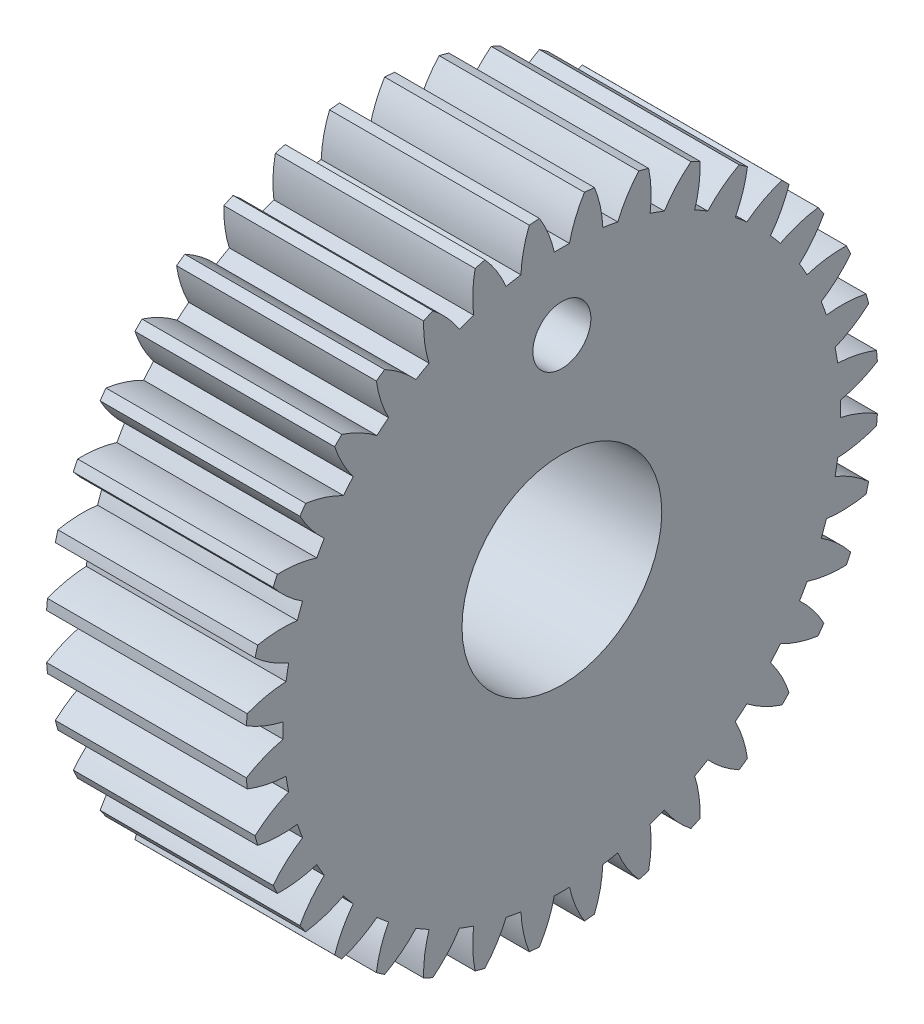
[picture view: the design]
ISO-10303-21;
HEADER;
FILE_DESCRIPTION(('STEP AP214'),'2;1');
FILE_NAME('part.step','',(''),(''),'','','');
FILE_SCHEMA(('AUTOMOTIVE_DESIGN { 1 0 10303 214 1 1 1 1 }'));
ENDSEC;
DATA;
#1=APPLICATION_CONTEXT('core data for automotive mechanical design processes');
#2=APPLICATION_PROTOCOL_DEFINITION('international standard','automotive_design',2000,#1);
#3=PRODUCT_CONTEXT('',#1,'mechanical');
#4=PRODUCT('Part','Part','',(#3));
#5=PRODUCT_RELATED_PRODUCT_CATEGORY('part','',(#4));
#6=PRODUCT_DEFINITION_FORMATION('','',#4);
#7=PRODUCT_DEFINITION_CONTEXT('part definition',#1,'design');
#8=PRODUCT_DEFINITION('design','',#6,#7);
#9=PRODUCT_DEFINITION_SHAPE('','',#8);
#10=(LENGTH_UNIT() NAMED_UNIT(*) SI_UNIT(.MILLI.,.METRE.));
#11=(NAMED_UNIT(*) PLANE_ANGLE_UNIT() SI_UNIT($,.RADIAN.));
#12=(NAMED_UNIT(*) SI_UNIT($,.STERADIAN.) SOLID_ANGLE_UNIT());
#13=UNCERTAINTY_MEASURE_WITH_UNIT(LENGTH_MEASURE(1.E-05),#10,'distance_accuracy_value','');
#14=(GEOMETRIC_REPRESENTATION_CONTEXT(3) GLOBAL_UNCERTAINTY_ASSIGNED_CONTEXT((#13)) GLOBAL_UNIT_ASSIGNED_CONTEXT((#10,
#11,#12)) REPRESENTATION_CONTEXT('',''));
#15=CARTESIAN_POINT('',(0.,0.,0.));
#16=DIRECTION('',(0.,0.,1.));
#17=DIRECTION('',(1.,0.,0.));
#18=AXIS2_PLACEMENT_3D('',#15,#16,#17);
#19=CARTESIAN_POINT('',(12.,0.,0.));
#20=DIRECTION('',(-1.,0.,0.));
#21=DIRECTION('',(0.,0.,1.));
#22=AXIS2_PLACEMENT_3D('',#19,#20,#21);
#23=PLANE('',#22);
#24=CARTESIAN_POINT('',(12.,12.2072193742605,0.));
#25=DIRECTION('',(-1.,0.,0.));
#26=DIRECTION('',(0.,0.,1.));
#27=AXIS2_PLACEMENT_3D('',#24,#25,#26);
#28=CIRCLE('',#27,1.74146852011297);
#29=CARTESIAN_POINT('',(12.,12.2072193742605,1.74146852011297));
#30=VERTEX_POINT('',#29);
#31=EDGE_CURVE('E1740',#30,#30,#28,.T.);
#32=ORIENTED_EDGE('',*,*,#31,.T.);
#33=EDGE_LOOP('',(#32));
#34=FACE_BOUND('',#33,.T.);
#35=CARTESIAN_POINT('',(12.,13.6407443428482,-10.001464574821));
#36=DIRECTION('',(-1.,0.,0.));
#37=DIRECTION('',(0.,-0.173648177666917,-0.984807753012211));
#38=AXIS2_PLACEMENT_3D('',#35,#36,#37);
#39=CIRCLE('',#38,7.2);
#40=CARTESIAN_POINT('',(12.,16.4095148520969,-3.35511897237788));
#41=VERTEX_POINT('',#40);
#42=CARTESIAN_POINT('',(12.,18.4287050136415,-4.624157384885));
#43=VERTEX_POINT('',#42);
#44=EDGE_CURVE('E934',#41,#43,#39,.T.);
#45=ORIENTED_EDGE('',*,*,#44,.F.);
#46=CARTESIAN_POINT('',(12.,0.,0.));
#47=DIRECTION('',(-1.,0.,0.));
#48=DIRECTION('',(0.,-0.173648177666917,-0.984807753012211));
#49=AXIS2_PLACEMENT_3D('',#46,#47,#48);
#50=CIRCLE('',#49,16.749);
#51=CARTESIAN_POINT('',(12.,16.5674182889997,-2.45960408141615));
#52=VERTEX_POINT('',#51);
#53=EDGE_CURVE('E1729',#52,#41,#50,.T.);
#54=ORIENTED_EDGE('',*,*,#53,.F.);
#55=CARTESIAN_POINT('',(12.,16.2388091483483,4.73289312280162));
#56=DIRECTION('',(-1.,0.,0.));
#57=DIRECTION('',(0.,-0.173648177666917,-0.984807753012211));
#58=AXIS2_PLACEMENT_3D('',#55,#56,#57);
#59=CIRCLE('',#58,7.2);
#60=CARTESIAN_POINT('',(12.,18.898873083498,-1.95770175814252));
#61=VERTEX_POINT('',#60);
#62=EDGE_CURVE('E924',#61,#52,#59,.T.);
#63=ORIENTED_EDGE('',*,*,#62,.F.);
#64=CARTESIAN_POINT('',(12.,0.,0.));
#65=DIRECTION('',(-1.,0.,0.));
#66=DIRECTION('',(0.,0.,1.));
#67=AXIS2_PLACEMENT_3D('',#64,#65,#66);
#68=CIRCLE('',#67,19.);
#69=CARTESIAN_POINT('',(12.,18.9517080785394,-1.3537950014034));
#70=VERTEX_POINT('',#69);
#71=EDGE_CURVE('E952',#70,#61,#68,.T.);
#72=ORIENTED_EDGE('',*,*,#71,.F.);
#73=CARTESIAN_POINT('',(12.,15.1702468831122,-7.48082945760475));
#74=DIRECTION('',(-1.,0.,0.));
#75=DIRECTION('',(0.,0.,-1.));
#76=AXIS2_PLACEMENT_3D('',#73,#74,#75);
#77=CIRCLE('',#76,7.2);
#78=CARTESIAN_POINT('',(12.,16.7428277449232,-0.454664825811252));
#79=VERTEX_POINT('',#78);
#80=EDGE_CURVE('E976',#79,#70,#77,.T.);
#81=ORIENTED_EDGE('',*,*,#80,.F.);
#82=CARTESIAN_POINT('',(12.,0.,0.));
#83=DIRECTION('',(-1.,0.,0.));
#84=DIRECTION('',(0.,0.,-1.));
#85=AXIS2_PLACEMENT_3D('',#82,#83,#84);
#86=CIRCLE('',#85,16.749);
#87=CARTESIAN_POINT('',(12.,16.7428277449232,0.454664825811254));
#88=VERTEX_POINT('',#87);
#89=EDGE_CURVE('E972',#88,#79,#86,.T.);
#90=ORIENTED_EDGE('',*,*,#89,.F.);
#91=CARTESIAN_POINT('',(12.,15.1702468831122,7.48082945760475));
#92=DIRECTION('',(-1.,0.,0.));
#93=DIRECTION('',(0.,0.,-1.));
#94=AXIS2_PLACEMENT_3D('',#91,#92,#93);
#95=CIRCLE('',#94,7.2);
#96=CARTESIAN_POINT('',(12.,18.9517080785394,1.3537950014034));
#97=VERTEX_POINT('',#96);
#98=EDGE_CURVE('E974',#97,#88,#95,.T.);
#99=ORIENTED_EDGE('',*,*,#98,.F.);
#100=CARTESIAN_POINT('',(12.,18.898873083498,1.95770175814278));
#101=VERTEX_POINT('',#100);
#102=EDGE_CURVE('E946',#101,#97,#68,.T.);
#103=ORIENTED_EDGE('',*,*,#102,.F.);
#104=CARTESIAN_POINT('',(12.,16.2388091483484,-4.73289312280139));
#105=DIRECTION('',(-1.,0.,0.));
#106=DIRECTION('',(0.,0.173648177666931,-0.984807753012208));
#107=AXIS2_PLACEMENT_3D('',#104,#105,#106);
#108=CIRCLE('',#107,7.2);
#109=CARTESIAN_POINT('',(12.,16.5674182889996,2.45960408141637));
#110=VERTEX_POINT('',#109);
#111=EDGE_CURVE('E995',#110,#101,#108,.T.);
#112=ORIENTED_EDGE('',*,*,#111,.F.);
#113=CARTESIAN_POINT('',(12.,0.,0.));
#114=DIRECTION('',(-1.,0.,0.));
#115=DIRECTION('',(0.,0.173648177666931,-0.984807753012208));
#116=AXIS2_PLACEMENT_3D('',#113,#114,#115);
#117=CIRCLE('',#116,16.749);
#118=CARTESIAN_POINT('',(12.,16.4095148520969,3.35511897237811));
#119=VERTEX_POINT('',#118);
#120=EDGE_CURVE('E991',#119,#110,#117,.T.);
#121=ORIENTED_EDGE('',*,*,#120,.F.);
#122=CARTESIAN_POINT('',(12.,13.6407443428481,10.0014645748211));
#123=DIRECTION('',(-1.,0.,0.));
#124=DIRECTION('',(0.,0.173648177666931,-0.984807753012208));
#125=AXIS2_PLACEMENT_3D('',#122,#123,#124);
#126=CIRCLE('',#125,7.2);
#127=CARTESIAN_POINT('',(12.,18.4287050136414,4.62415738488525));
#128=VERTEX_POINT('',#127);
#129=EDGE_CURVE('E993',#128,#119,#126,.T.);
#130=ORIENTED_EDGE('',*,*,#129,.F.);
#131=CARTESIAN_POINT('',(12.,18.2718053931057,5.20971474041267));
#132=VERTEX_POINT('',#131);
#133=EDGE_CURVE('E950',#132,#128,#68,.T.);
#134=ORIENTED_EDGE('',*,*,#133,.F.);
#135=CARTESIAN_POINT('',(12.,16.8139634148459,-1.8411502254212));
#136=DIRECTION('',(-1.,0.,0.));
#137=DIRECTION('',(0.,0.342020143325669,-0.939692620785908));
#138=AXIS2_PLACEMENT_3D('',#135,#136,#137);
#139=CIRCLE('',#138,7.2);
#140=CARTESIAN_POINT('',(12.,15.888616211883,5.29913916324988));
#141=VERTEX_POINT('',#140);
#142=EDGE_CURVE('E1016',#141,#132,#139,.T.);
#143=ORIENTED_EDGE('',*,*,#142,.F.);
#144=CARTESIAN_POINT('',(12.,0.,0.));
#145=DIRECTION('',(-1.,0.,0.));
#146=DIRECTION('',(0.,0.342020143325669,-0.939692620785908));
#147=AXIS2_PLACEMENT_3D('',#144,#145,#146);
#148=CIRCLE('',#147,16.749);
#149=CARTESIAN_POINT('',(12.,15.5776071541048,6.15362952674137));
#150=VERTEX_POINT('',#149);
#151=EDGE_CURVE('E1012',#150,#141,#148,.T.);
#152=ORIENTED_EDGE('',*,*,#151,.F.);
#153=CARTESIAN_POINT('',(12.,11.6967746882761,12.2182102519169));
#154=DIRECTION('',(-1.,0.,0.));
#155=DIRECTION('',(0.,0.342020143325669,-0.939692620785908));
#156=AXIS2_PLACEMENT_3D('',#153,#154,#155);
#157=CIRCLE('',#156,7.2);
#158=CARTESIAN_POINT('',(12.,17.3457550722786,7.75401708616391));
#159=VERTEX_POINT('',#158);
#160=EDGE_CURVE('E1014',#159,#150,#157,.T.);
#161=ORIENTED_EDGE('',*,*,#160,.F.);
#162=CARTESIAN_POINT('',(12.,17.0895581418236,8.30343317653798));
#163=VERTEX_POINT('',#162);
#164=EDGE_CURVE('E2058',#163,#159,#68,.T.);
#165=ORIENTED_EDGE('',*,*,#164,.F.);
#166=CARTESIAN_POINT('',(12.,16.8782339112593,1.10653508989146));
#167=DIRECTION('',(-1.,0.,0.));
#168=DIRECTION('',(0.,0.500000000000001,-0.866025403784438));
#169=AXIS2_PLACEMENT_3D('',#166,#167,#168);
#170=CIRCLE('',#169,7.2);
#171=CARTESIAN_POINT('',(12.,14.727046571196,7.97766258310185));
#172=VERTEX_POINT('',#171);
#173=EDGE_CURVE('E1038',#172,#163,#170,.T.);
#174=ORIENTED_EDGE('',*,*,#173,.F.);
#175=CARTESIAN_POINT('',(12.,0.,0.));
#176=DIRECTION('',(-1.,0.,0.));
#177=DIRECTION('',(0.,0.500000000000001,-0.866025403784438));
#178=AXIS2_PLACEMENT_3D('',#175,#176,#177);
#179=CIRCLE('',#178,16.749);
#180=CARTESIAN_POINT('',(12.,14.2723817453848,8.76516516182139));
#181=VERTEX_POINT('',#180);
#182=EDGE_CURVE('E1034',#181,#172,#179,.T.);
#183=ORIENTED_EDGE('',*,*,#182,.F.);
#184=CARTESIAN_POINT('',(12.,9.3974044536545,14.0637117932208));
#185=DIRECTION('',(-1.,0.,0.));
#186=DIRECTION('',(0.,0.500000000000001,-0.866025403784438));
#187=AXIS2_PLACEMENT_3D('',#184,#185,#186);
#188=CIRCLE('',#187,7.2);
#189=CARTESIAN_POINT('',(12.,15.7357631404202,10.6482749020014));
#190=VERTEX_POINT('',#189);
#191=EDGE_CURVE('E1036',#190,#181,#188,.T.);
#192=ORIENTED_EDGE('',*,*,#191,.F.);
#193=CARTESIAN_POINT('',(12.,15.3880533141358,11.1448559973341));
#194=VERTEX_POINT('',#193);
#195=EDGE_CURVE('E2053',#194,#190,#68,.T.);
#196=ORIENTED_EDGE('',*,*,#195,.F.);
#197=CARTESIAN_POINT('',(12.,16.4296678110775,4.02059889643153));
#198=DIRECTION('',(-1.,0.,0.));
#199=DIRECTION('',(0.,0.642787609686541,-0.766044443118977));
#200=AXIS2_PLACEMENT_3D('',#197,#198,#199);
#201=CIRCLE('',#200,7.2);
#202=CARTESIAN_POINT('',(12.,13.1180030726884,10.4137887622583));
#203=VERTEX_POINT('',#202);
#204=EDGE_CURVE('E1060',#203,#194,#201,.T.);
#205=ORIENTED_EDGE('',*,*,#204,.F.);
#206=CARTESIAN_POINT('',(12.,0.,0.));
#207=DIRECTION('',(-1.,0.,0.));
#208=DIRECTION('',(0.,0.642787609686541,-0.766044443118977));
#209=AXIS2_PLACEMENT_3D('',#206,#207,#208);
#210=CIRCLE('',#209,16.749);
#211=CARTESIAN_POINT('',(12.,12.5334972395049,11.110375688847));
#212=VERTEX_POINT('',#211);
#213=EDGE_CURVE('E1056',#212,#203,#210,.T.);
#214=ORIENTED_EDGE('',*,*,#213,.F.);
#215=CARTESIAN_POINT('',(12.,6.8124988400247,15.4818945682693));
#216=DIRECTION('',(-1.,0.,0.));
#217=DIRECTION('',(0.,0.642787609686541,-0.766044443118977));
#218=AXIS2_PLACEMENT_3D('',#215,#216,#217);
#219=CIRCLE('',#218,7.2);
#220=CARTESIAN_POINT('',(12.,13.6476480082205,13.2189902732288));
#221=VERTEX_POINT('',#220);
#222=EDGE_CURVE('E1058',#221,#212,#219,.T.);
#223=ORIENTED_EDGE('',*,*,#222,.F.);
#224=CARTESIAN_POINT('',(12.,13.2189902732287,13.6476480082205));
#225=VERTEX_POINT('',#224);
#226=EDGE_CURVE('E2048',#225,#221,#68,.T.);
#227=ORIENTED_EDGE('',*,*,#226,.F.);
#228=CARTESIAN_POINT('',(12.,15.4818945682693,6.81249884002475));
#229=DIRECTION('',(-1.,0.,0.));
#230=DIRECTION('',(0.,0.766044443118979,-0.642787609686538));
#231=AXIS2_PLACEMENT_3D('',#228,#229,#230);
#232=CIRCLE('',#231,7.2);
#233=CARTESIAN_POINT('',(12.,11.110375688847,12.5334972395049));
#234=VERTEX_POINT('',#233);
#235=EDGE_CURVE('E1082',#234,#225,#232,.T.);
#236=ORIENTED_EDGE('',*,*,#235,.F.);
#237=CARTESIAN_POINT('',(12.,0.,0.));
#238=DIRECTION('',(-1.,0.,0.));
#239=DIRECTION('',(0.,0.766044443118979,-0.642787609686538));
#240=AXIS2_PLACEMENT_3D('',#237,#238,#239);
#241=CIRCLE('',#240,16.749);
#242=CARTESIAN_POINT('',(12.,10.4137887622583,13.1180030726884));
#243=VERTEX_POINT('',#242);
#244=EDGE_CURVE('E1078',#243,#234,#241,.T.);
#245=ORIENTED_EDGE('',*,*,#244,.F.);
#246=CARTESIAN_POINT('',(12.,4.02059889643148,16.4296678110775));
#247=DIRECTION('',(-1.,0.,0.));
#248=DIRECTION('',(0.,0.766044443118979,-0.642787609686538));
#249=AXIS2_PLACEMENT_3D('',#246,#247,#248);
#250=CIRCLE('',#249,7.2);
#251=CARTESIAN_POINT('',(12.,11.1448559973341,15.3880533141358));
#252=VERTEX_POINT('',#251);
#253=EDGE_CURVE('E1080',#252,#243,#250,.T.);
#254=ORIENTED_EDGE('',*,*,#253,.F.);
#255=CARTESIAN_POINT('',(12.,10.6482749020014,15.7357631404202));
#256=VERTEX_POINT('',#255);
#257=EDGE_CURVE('E2043',#256,#252,#68,.T.);
#258=ORIENTED_EDGE('',*,*,#257,.F.);
#259=CARTESIAN_POINT('',(12.,14.0637117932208,9.39740445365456));
#260=DIRECTION('',(-1.,0.,0.));
#261=DIRECTION('',(0.,0.86602540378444,-0.499999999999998));
#262=AXIS2_PLACEMENT_3D('',#259,#260,#261);
#263=CIRCLE('',#262,7.2);
#264=CARTESIAN_POINT('',(12.,8.76516516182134,14.2723817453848));
#265=VERTEX_POINT('',#264);
#266=EDGE_CURVE('E1104',#265,#256,#263,.T.);
#267=ORIENTED_EDGE('',*,*,#266,.F.);
#268=CARTESIAN_POINT('',(12.,0.,0.));
#269=DIRECTION('',(-1.,0.,0.));
#270=DIRECTION('',(0.,0.86602540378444,-0.499999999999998));
#271=AXIS2_PLACEMENT_3D('',#268,#269,#270);
#272=CIRCLE('',#271,16.749);
#273=CARTESIAN_POINT('',(12.,7.97766258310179,14.7270465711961));
#274=VERTEX_POINT('',#273);
#275=EDGE_CURVE('E1100',#274,#265,#272,.T.);
#276=ORIENTED_EDGE('',*,*,#275,.F.);
#277=CARTESIAN_POINT('',(12.,1.1065350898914,16.8782339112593));
#278=DIRECTION('',(-1.,0.,0.));
#279=DIRECTION('',(0.,0.86602540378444,-0.499999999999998));
#280=AXIS2_PLACEMENT_3D('',#277,#278,#279);
#281=CIRCLE('',#280,7.2);
#282=CARTESIAN_POINT('',(12.,8.30343317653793,17.0895581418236));
#283=VERTEX_POINT('',#282);
#284=EDGE_CURVE('E1102',#283,#274,#281,.T.);
#285=ORIENTED_EDGE('',*,*,#284,.F.);
#286=CARTESIAN_POINT('',(12.,7.75401708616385,17.3457550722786));
#287=VERTEX_POINT('',#286);
#288=EDGE_CURVE('E2038',#287,#283,#68,.T.);
#289=ORIENTED_EDGE('',*,*,#288,.F.);
#290=CARTESIAN_POINT('',(12.,12.2182102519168,11.6967746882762));
#291=DIRECTION('',(-1.,0.,0.));
#292=DIRECTION('',(0.,0.939692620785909,-0.342020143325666));
#293=AXIS2_PLACEMENT_3D('',#290,#291,#292);
#294=CIRCLE('',#293,7.2);
#295=CARTESIAN_POINT('',(12.,6.15362952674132,15.5776071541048));
#296=VERTEX_POINT('',#295);
#297=EDGE_CURVE('E1126',#296,#287,#294,.T.);
#298=ORIENTED_EDGE('',*,*,#297,.F.);
#299=CARTESIAN_POINT('',(12.,0.,0.));
#300=DIRECTION('',(-1.,0.,0.));
#301=DIRECTION('',(0.,0.939692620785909,-0.342020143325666));
#302=AXIS2_PLACEMENT_3D('',#299,#300,#301);
#303=CIRCLE('',#302,16.749);
#304=CARTESIAN_POINT('',(12.,5.29913916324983,15.888616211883));
#305=VERTEX_POINT('',#304);
#306=EDGE_CURVE('E1122',#305,#296,#303,.T.);
#307=ORIENTED_EDGE('',*,*,#306,.F.);
#308=CARTESIAN_POINT('',(12.,-1.84115022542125,16.8139634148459));
#309=DIRECTION('',(-1.,0.,0.));
#310=DIRECTION('',(0.,0.939692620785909,-0.342020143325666));
#311=AXIS2_PLACEMENT_3D('',#308,#309,#310);
#312=CIRCLE('',#311,7.2);
#313=CARTESIAN_POINT('',(12.,5.20971474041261,18.2718053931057));
#314=VERTEX_POINT('',#313);
#315=EDGE_CURVE('E1124',#314,#305,#312,.T.);
#316=ORIENTED_EDGE('',*,*,#315,.F.);
#317=CARTESIAN_POINT('',(12.,4.62415738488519,18.4287050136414));
#318=VERTEX_POINT('',#317);
#319=EDGE_CURVE('E2033',#318,#314,#68,.T.);
#320=ORIENTED_EDGE('',*,*,#319,.F.);
#321=CARTESIAN_POINT('',(12.,10.0014645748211,13.6407443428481));
#322=DIRECTION('',(-1.,0.,0.));
#323=DIRECTION('',(0.,0.984807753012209,-0.173648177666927));
#324=AXIS2_PLACEMENT_3D('',#321,#322,#323);
#325=CIRCLE('',#324,7.2);
#326=CARTESIAN_POINT('',(12.,3.35511897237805,16.4095148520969));
#327=VERTEX_POINT('',#326);
#328=EDGE_CURVE('E1148',#327,#318,#325,.T.);
#329=ORIENTED_EDGE('',*,*,#328,.F.);
#330=CARTESIAN_POINT('',(12.,0.,0.));
#331=DIRECTION('',(-1.,0.,0.));
#332=DIRECTION('',(0.,0.984807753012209,-0.173648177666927));
#333=AXIS2_PLACEMENT_3D('',#330,#331,#332);
#334=CIRCLE('',#333,16.749);
#335=CARTESIAN_POINT('',(12.,2.45960408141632,16.5674182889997));
#336=VERTEX_POINT('',#335);
#337=EDGE_CURVE('E1144',#336,#327,#334,.T.);
#338=ORIENTED_EDGE('',*,*,#337,.F.);
#339=CARTESIAN_POINT('',(12.,-4.73289312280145,16.2388091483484));
#340=DIRECTION('',(-1.,0.,0.));
#341=DIRECTION('',(0.,0.984807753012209,-0.173648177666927));
#342=AXIS2_PLACEMENT_3D('',#339,#340,#341);
#343=CIRCLE('',#342,7.2);
#344=CARTESIAN_POINT('',(12.,1.95770175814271,18.898873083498));
#345=VERTEX_POINT('',#344);
#346=EDGE_CURVE('E1146',#345,#336,#343,.T.);
#347=ORIENTED_EDGE('',*,*,#346,.F.);
#348=CARTESIAN_POINT('',(12.,1.35379500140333,18.9517080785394));
#349=VERTEX_POINT('',#348);
#350=EDGE_CURVE('E2028',#349,#345,#68,.T.);
#351=ORIENTED_EDGE('',*,*,#350,.F.);
#352=CARTESIAN_POINT('',(12.,7.4808294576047,15.1702468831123));
#353=DIRECTION('',(-1.,0.,0.));
#354=DIRECTION('',(0.,1.,0.));
#355=AXIS2_PLACEMENT_3D('',#352,#353,#354);
#356=CIRCLE('',#355,7.2);
#357=CARTESIAN_POINT('',(12.,0.454664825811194,16.7428277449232));
#358=VERTEX_POINT('',#357);
#359=EDGE_CURVE('E1170',#358,#349,#356,.T.);
#360=ORIENTED_EDGE('',*,*,#359,.F.);
#361=CARTESIAN_POINT('',(12.,0.,0.));
#362=DIRECTION('',(-1.,0.,0.));
#363=DIRECTION('',(0.,1.,0.));
#364=AXIS2_PLACEMENT_3D('',#361,#362,#363);
#365=CIRCLE('',#364,16.749);
#366=CARTESIAN_POINT('',(12.,-0.454664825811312,16.7428277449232));
#367=VERTEX_POINT('',#366);
#368=EDGE_CURVE('E1166',#367,#358,#365,.T.);
#369=ORIENTED_EDGE('',*,*,#368,.F.);
#370=CARTESIAN_POINT('',(12.,-7.48082945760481,15.1702468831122));
#371=DIRECTION('',(-1.,0.,0.));
#372=DIRECTION('',(0.,1.,0.));
#373=AXIS2_PLACEMENT_3D('',#370,#371,#372);
#374=CIRCLE('',#373,7.2);
#375=CARTESIAN_POINT('',(12.,-1.35379500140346,18.9517080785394));
#376=VERTEX_POINT('',#375);
#377=EDGE_CURVE('E1168',#376,#367,#374,.T.);
#378=ORIENTED_EDGE('',*,*,#377,.F.);
#379=CARTESIAN_POINT('',(12.,-1.95770175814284,18.898873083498));
#380=VERTEX_POINT('',#379);
#381=EDGE_CURVE('E2023',#380,#376,#68,.T.);
#382=ORIENTED_EDGE('',*,*,#381,.F.);
#383=CARTESIAN_POINT('',(12.,4.73289312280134,16.2388091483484));
#384=DIRECTION('',(-1.,0.,0.));
#385=DIRECTION('',(0.,0.984807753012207,0.173648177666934));
#386=AXIS2_PLACEMENT_3D('',#383,#384,#385);
#387=CIRCLE('',#386,7.2);
#388=CARTESIAN_POINT('',(12.,-2.45960408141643,16.5674182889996));
#389=VERTEX_POINT('',#388);
#390=EDGE_CURVE('E1192',#389,#380,#387,.T.);
#391=ORIENTED_EDGE('',*,*,#390,.F.);
#392=CARTESIAN_POINT('',(12.,0.,0.));
#393=DIRECTION('',(-1.,0.,0.));
#394=DIRECTION('',(0.,0.984807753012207,0.173648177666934));
#395=AXIS2_PLACEMENT_3D('',#392,#393,#394);
#396=CIRCLE('',#395,16.749);
#397=CARTESIAN_POINT('',(12.,-3.35511897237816,16.4095148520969));
#398=VERTEX_POINT('',#397);
#399=EDGE_CURVE('E1188',#398,#389,#396,.T.);
#400=ORIENTED_EDGE('',*,*,#399,.F.);
#401=CARTESIAN_POINT('',(12.,-10.0014645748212,13.640744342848));
#402=DIRECTION('',(-1.,0.,0.));
#403=DIRECTION('',(0.,0.984807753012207,0.173648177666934));
#404=AXIS2_PLACEMENT_3D('',#401,#402,#403);
#405=CIRCLE('',#404,7.2);
#406=CARTESIAN_POINT('',(12.,-4.62415738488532,18.4287050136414));
#407=VERTEX_POINT('',#406);
#408=EDGE_CURVE('E1190',#407,#398,#405,.T.);
#409=ORIENTED_EDGE('',*,*,#408,.F.);
#410=CARTESIAN_POINT('',(12.,-5.20971474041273,18.2718053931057));
#411=VERTEX_POINT('',#410);
#412=EDGE_CURVE('E2018',#411,#407,#68,.T.);
#413=ORIENTED_EDGE('',*,*,#412,.F.);
#414=CARTESIAN_POINT('',(12.,1.84115022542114,16.8139634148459));
#415=DIRECTION('',(-1.,0.,0.));
#416=DIRECTION('',(0.,0.939692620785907,0.342020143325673));
#417=AXIS2_PLACEMENT_3D('',#414,#415,#416);
#418=CIRCLE('',#417,7.2);
#419=CARTESIAN_POINT('',(12.,-5.29913916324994,15.888616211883));
#420=VERTEX_POINT('',#419);
#421=EDGE_CURVE('E1214',#420,#411,#418,.T.);
#422=ORIENTED_EDGE('',*,*,#421,.F.);
#423=CARTESIAN_POINT('',(12.,0.,0.));
#424=DIRECTION('',(-1.,0.,0.));
#425=DIRECTION('',(0.,0.939692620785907,0.342020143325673));
#426=AXIS2_PLACEMENT_3D('',#423,#424,#425);
#427=CIRCLE('',#426,16.749);
#428=CARTESIAN_POINT('',(12.,-6.15362952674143,15.5776071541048));
#429=VERTEX_POINT('',#428);
#430=EDGE_CURVE('E1210',#429,#420,#427,.T.);
#431=ORIENTED_EDGE('',*,*,#430,.F.);
#432=CARTESIAN_POINT('',(12.,-12.2182102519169,11.6967746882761));
#433=DIRECTION('',(-1.,0.,0.));
#434=DIRECTION('',(0.,0.939692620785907,0.342020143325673));
#435=AXIS2_PLACEMENT_3D('',#432,#433,#434);
#436=CIRCLE('',#435,7.2);
#437=CARTESIAN_POINT('',(12.,-7.75401708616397,17.3457550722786));
#438=VERTEX_POINT('',#437);
#439=EDGE_CURVE('E1212',#438,#429,#436,.T.);
#440=ORIENTED_EDGE('',*,*,#439,.F.);
#441=CARTESIAN_POINT('',(12.,-8.30343317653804,17.0895581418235));
#442=VERTEX_POINT('',#441);
#443=EDGE_CURVE('E2013',#442,#438,#68,.T.);
#444=ORIENTED_EDGE('',*,*,#443,.F.);
#445=CARTESIAN_POINT('',(12.,-1.10653508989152,16.8782339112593));
#446=DIRECTION('',(-1.,0.,0.));
#447=DIRECTION('',(0.,0.866025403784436,0.500000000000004));
#448=AXIS2_PLACEMENT_3D('',#445,#446,#447);
#449=CIRCLE('',#448,7.2);
#450=CARTESIAN_POINT('',(12.,-7.9776625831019,14.727046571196));
#451=VERTEX_POINT('',#450);
#452=EDGE_CURVE('E1236',#451,#442,#449,.T.);
#453=ORIENTED_EDGE('',*,*,#452,.F.);
#454=CARTESIAN_POINT('',(12.,0.,0.));
#455=DIRECTION('',(-1.,0.,0.));
#456=DIRECTION('',(0.,0.866025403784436,0.500000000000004));
#457=AXIS2_PLACEMENT_3D('',#454,#455,#456);
#458=CIRCLE('',#457,16.749);
#459=CARTESIAN_POINT('',(12.,-8.76516516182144,14.2723817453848));
#460=VERTEX_POINT('',#459);
#461=EDGE_CURVE('E1232',#460,#451,#458,.T.);
#462=ORIENTED_EDGE('',*,*,#461,.F.);
#463=CARTESIAN_POINT('',(12.,-14.0637117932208,9.39740445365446));
#464=DIRECTION('',(-1.,0.,0.));
#465=DIRECTION('',(0.,0.866025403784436,0.500000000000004));
#466=AXIS2_PLACEMENT_3D('',#463,#464,#465);
#467=CIRCLE('',#466,7.2);
#468=CARTESIAN_POINT('',(12.,-10.6482749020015,15.7357631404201));
#469=VERTEX_POINT('',#468);
#470=EDGE_CURVE('E1234',#469,#460,#467,.T.);
#471=ORIENTED_EDGE('',*,*,#470,.F.);
#472=CARTESIAN_POINT('',(12.,-11.1448559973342,15.3880533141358));
#473=VERTEX_POINT('',#472);
#474=EDGE_CURVE('E2008',#473,#469,#68,.T.);
#475=ORIENTED_EDGE('',*,*,#474,.F.);
#476=CARTESIAN_POINT('',(12.,-4.02059889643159,16.4296678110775));
#477=DIRECTION('',(-1.,0.,0.));
#478=DIRECTION('',(0.,0.766044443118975,0.642787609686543));
#479=AXIS2_PLACEMENT_3D('',#476,#477,#478);
#480=CIRCLE('',#479,7.2);
#481=CARTESIAN_POINT('',(12.,-10.4137887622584,13.1180030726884));
#482=VERTEX_POINT('',#481);
#483=EDGE_CURVE('E1258',#482,#473,#480,.T.);
#484=ORIENTED_EDGE('',*,*,#483,.F.);
#485=CARTESIAN_POINT('',(12.,0.,0.));
#486=DIRECTION('',(-1.,0.,0.));
#487=DIRECTION('',(0.,0.766044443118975,0.642787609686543));
#488=AXIS2_PLACEMENT_3D('',#485,#486,#487);
#489=CIRCLE('',#488,16.749);
#490=CARTESIAN_POINT('',(12.,-11.1103756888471,12.5334972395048));
#491=VERTEX_POINT('',#490);
#492=EDGE_CURVE('E1254',#491,#482,#489,.T.);
#493=ORIENTED_EDGE('',*,*,#492,.F.);
#494=CARTESIAN_POINT('',(12.,-15.4818945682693,6.81249884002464));
#495=DIRECTION('',(-1.,0.,0.));
#496=DIRECTION('',(0.,0.766044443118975,0.642787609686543));
#497=AXIS2_PLACEMENT_3D('',#494,#495,#496);
#498=CIRCLE('',#497,7.2);
#499=CARTESIAN_POINT('',(12.,-13.2189902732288,13.6476480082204));
#500=VERTEX_POINT('',#499);
#501=EDGE_CURVE('E1256',#500,#491,#498,.T.);
#502=ORIENTED_EDGE('',*,*,#501,.F.);
#503=CARTESIAN_POINT('',(12.,-13.6476480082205,13.2189902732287));
#504=VERTEX_POINT('',#503);
#505=EDGE_CURVE('E2003',#504,#500,#68,.T.);
#506=ORIENTED_EDGE('',*,*,#505,.F.);
#507=CARTESIAN_POINT('',(12.,-6.8124988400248,15.4818945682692));
#508=DIRECTION('',(-1.,0.,0.));
#509=DIRECTION('',(0.,0.642787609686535,0.766044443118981));
#510=AXIS2_PLACEMENT_3D('',#507,#508,#509);
#511=CIRCLE('',#510,7.2);
#512=CARTESIAN_POINT('',(12.,-12.533497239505,11.110375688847));
#513=VERTEX_POINT('',#512);
#514=EDGE_CURVE('E1280',#513,#504,#511,.T.);
#515=ORIENTED_EDGE('',*,*,#514,.F.);
#516=CARTESIAN_POINT('',(12.,0.,0.));
#517=DIRECTION('',(-1.,0.,0.));
#518=DIRECTION('',(0.,0.642787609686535,0.766044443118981));
#519=AXIS2_PLACEMENT_3D('',#516,#517,#518);
#520=CIRCLE('',#519,16.749);
#521=CARTESIAN_POINT('',(12.,-13.1180030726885,10.4137887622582));
#522=VERTEX_POINT('',#521);
#523=EDGE_CURVE('E1276',#522,#513,#520,.T.);
#524=ORIENTED_EDGE('',*,*,#523,.F.);
#525=CARTESIAN_POINT('',(12.,-16.4296678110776,4.02059889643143));
#526=DIRECTION('',(-1.,0.,0.));
#527=DIRECTION('',(0.,0.642787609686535,0.766044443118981));
#528=AXIS2_PLACEMENT_3D('',#525,#526,#527);
#529=CIRCLE('',#528,7.2);
#530=CARTESIAN_POINT('',(12.,-15.3880533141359,11.144855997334));
#531=VERTEX_POINT('',#530);
#532=EDGE_CURVE('E1278',#531,#522,#529,.T.);
#533=ORIENTED_EDGE('',*,*,#532,.F.);
#534=CARTESIAN_POINT('',(12.,-15.7357631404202,10.6482749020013));
#535=VERTEX_POINT('',#534);
#536=EDGE_CURVE('E1998',#535,#531,#68,.T.);
#537=ORIENTED_EDGE('',*,*,#536,.F.);
#538=CARTESIAN_POINT('',(12.,-9.3974044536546,14.0637117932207));
#539=DIRECTION('',(-1.,0.,0.));
#540=DIRECTION('',(0.,0.499999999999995,0.866025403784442));
#541=AXIS2_PLACEMENT_3D('',#538,#539,#540);
#542=CIRCLE('',#541,7.2);
#543=CARTESIAN_POINT('',(12.,-14.2723817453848,8.76516516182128));
#544=VERTEX_POINT('',#543);
#545=EDGE_CURVE('E1302',#544,#535,#542,.T.);
#546=ORIENTED_EDGE('',*,*,#545,.F.);
#547=CARTESIAN_POINT('',(12.,0.,0.));
#548=DIRECTION('',(-1.,0.,0.));
#549=DIRECTION('',(0.,0.499999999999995,0.866025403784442));
#550=AXIS2_PLACEMENT_3D('',#547,#548,#549);
#551=CIRCLE('',#550,16.749);
#552=CARTESIAN_POINT('',(12.,-14.7270465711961,7.97766258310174));
#553=VERTEX_POINT('',#552);
#554=EDGE_CURVE('E1298',#553,#544,#551,.T.);
#555=ORIENTED_EDGE('',*,*,#554,.F.);
#556=CARTESIAN_POINT('',(12.,-16.8782339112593,1.10653508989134));
#557=DIRECTION('',(-1.,0.,0.));
#558=DIRECTION('',(0.,0.499999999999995,0.866025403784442));
#559=AXIS2_PLACEMENT_3D('',#556,#557,#558);
#560=CIRCLE('',#559,7.2);
#561=CARTESIAN_POINT('',(12.,-17.0895581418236,8.30343317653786));
#562=VERTEX_POINT('',#561);
#563=EDGE_CURVE('E1300',#562,#553,#560,.T.);
#564=ORIENTED_EDGE('',*,*,#563,.F.);
#565=CARTESIAN_POINT('',(12.,-17.3457550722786,7.75401708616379));
#566=VERTEX_POINT('',#565);
#567=EDGE_CURVE('E1993',#566,#562,#68,.T.);
#568=ORIENTED_EDGE('',*,*,#567,.F.);
#569=CARTESIAN_POINT('',(12.,-11.6967746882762,12.2182102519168));
#570=DIRECTION('',(-1.,0.,0.));
#571=DIRECTION('',(0.,0.342020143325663,0.939692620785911));
#572=AXIS2_PLACEMENT_3D('',#569,#570,#571);
#573=CIRCLE('',#572,7.2);
#574=CARTESIAN_POINT('',(12.,-15.5776071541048,6.15362952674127));
#575=VERTEX_POINT('',#574);
#576=EDGE_CURVE('E1324',#575,#566,#573,.T.);
#577=ORIENTED_EDGE('',*,*,#576,.F.);
#578=CARTESIAN_POINT('',(12.,0.,0.));
#579=DIRECTION('',(-1.,0.,0.));
#580=DIRECTION('',(0.,0.342020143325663,0.939692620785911));
#581=AXIS2_PLACEMENT_3D('',#578,#579,#580);
#582=CIRCLE('',#581,16.749);
#583=CARTESIAN_POINT('',(12.,-15.888616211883,5.29913916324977));
#584=VERTEX_POINT('',#583);
#585=EDGE_CURVE('E1320',#584,#575,#582,.T.);
#586=ORIENTED_EDGE('',*,*,#585,.F.);
#587=CARTESIAN_POINT('',(12.,-16.8139634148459,-1.84115022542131));
#588=DIRECTION('',(-1.,0.,0.));
#589=DIRECTION('',(0.,0.342020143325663,0.939692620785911));
#590=AXIS2_PLACEMENT_3D('',#587,#588,#589);
#591=CIRCLE('',#590,7.2);
#592=CARTESIAN_POINT('',(12.,-18.2718053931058,5.20971474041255));
#593=VERTEX_POINT('',#592);
#594=EDGE_CURVE('E1322',#593,#584,#591,.T.);
#595=ORIENTED_EDGE('',*,*,#594,.F.);
#596=CARTESIAN_POINT('',(12.,-18.4287050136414,4.62415738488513));
#597=VERTEX_POINT('',#596);
#598=EDGE_CURVE('E1988',#597,#593,#68,.T.);
#599=ORIENTED_EDGE('',*,*,#598,.F.);
#600=CARTESIAN_POINT('',(12.,-13.6407443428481,10.0014645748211));
#601=DIRECTION('',(-1.,0.,0.));
#602=DIRECTION('',(0.,0.173648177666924,0.984807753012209));
#603=AXIS2_PLACEMENT_3D('',#600,#601,#602);
#604=CIRCLE('',#603,7.2);
#605=CARTESIAN_POINT('',(12.,-16.4095148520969,3.355118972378));
#606=VERTEX_POINT('',#605);
#607=EDGE_CURVE('E1346',#606,#597,#604,.T.);
#608=ORIENTED_EDGE('',*,*,#607,.F.);
#609=CARTESIAN_POINT('',(12.,0.,0.));
#610=DIRECTION('',(-1.,0.,0.));
#611=DIRECTION('',(0.,0.173648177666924,0.984807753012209));
#612=AXIS2_PLACEMENT_3D('',#609,#610,#611);
#613=CIRCLE('',#612,16.749);
#614=CARTESIAN_POINT('',(12.,-16.5674182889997,2.45960408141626));
#615=VERTEX_POINT('',#614);
#616=EDGE_CURVE('E1342',#615,#606,#613,.T.);
#617=ORIENTED_EDGE('',*,*,#616,.F.);
#618=CARTESIAN_POINT('',(12.,-16.2388091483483,-4.7328931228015));
#619=DIRECTION('',(-1.,0.,0.));
#620=DIRECTION('',(0.,0.173648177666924,0.984807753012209));
#621=AXIS2_PLACEMENT_3D('',#618,#619,#620);
#622=CIRCLE('',#621,7.2);
#623=CARTESIAN_POINT('',(12.,-18.898873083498,1.95770175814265));
#624=VERTEX_POINT('',#623);
#625=EDGE_CURVE('E1344',#624,#615,#622,.T.);
#626=ORIENTED_EDGE('',*,*,#625,.F.);
#627=CARTESIAN_POINT('',(12.,-18.9517080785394,1.35379500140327));
#628=VERTEX_POINT('',#627);
#629=EDGE_CURVE('E1983',#628,#624,#68,.T.);
#630=ORIENTED_EDGE('',*,*,#629,.F.);
#631=CARTESIAN_POINT('',(12.,-15.1702468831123,7.48082945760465));
#632=DIRECTION('',(-1.,0.,0.));
#633=DIRECTION('',(0.,0.,1.));
#634=AXIS2_PLACEMENT_3D('',#631,#632,#633);
#635=CIRCLE('',#634,7.2);
#636=CARTESIAN_POINT('',(12.,-16.7428277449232,0.454664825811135));
#637=VERTEX_POINT('',#636);
#638=EDGE_CURVE('E1368',#637,#628,#635,.T.);
#639=ORIENTED_EDGE('',*,*,#638,.F.);
#640=CARTESIAN_POINT('',(12.,0.,0.));
#641=DIRECTION('',(-1.,0.,0.));
#642=DIRECTION('',(0.,0.,1.));
#643=AXIS2_PLACEMENT_3D('',#640,#641,#642);
#644=CIRCLE('',#643,16.749);
#645=CARTESIAN_POINT('',(12.,-16.7428277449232,-0.454664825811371));
#646=VERTEX_POINT('',#645);
#647=EDGE_CURVE('E1364',#646,#637,#644,.T.);
#648=ORIENTED_EDGE('',*,*,#647,.F.);
#649=CARTESIAN_POINT('',(12.,-15.1702468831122,-7.48082945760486));
#650=DIRECTION('',(-1.,0.,0.));
#651=DIRECTION('',(0.,0.,1.));
#652=AXIS2_PLACEMENT_3D('',#649,#650,#651);
#653=CIRCLE('',#652,7.2);
#654=CARTESIAN_POINT('',(12.,-18.9517080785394,-1.35379500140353));
#655=VERTEX_POINT('',#654);
#656=EDGE_CURVE('E1366',#655,#646,#653,.T.);
#657=ORIENTED_EDGE('',*,*,#656,.F.);
#658=CARTESIAN_POINT('',(12.,-18.898873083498,-1.9577017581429));
#659=VERTEX_POINT('',#658);
#660=EDGE_CURVE('E1978',#659,#655,#68,.T.);
#661=ORIENTED_EDGE('',*,*,#660,.F.);
#662=CARTESIAN_POINT('',(12.,-16.2388091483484,4.73289312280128));
#663=DIRECTION('',(-1.,0.,0.));
#664=DIRECTION('',(0.,-0.173648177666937,0.984807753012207));
#665=AXIS2_PLACEMENT_3D('',#662,#663,#664);
#666=CIRCLE('',#665,7.2);
#667=CARTESIAN_POINT('',(12.,-16.5674182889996,-2.45960408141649));
#668=VERTEX_POINT('',#667);
#669=EDGE_CURVE('E1390',#668,#659,#666,.T.);
#670=ORIENTED_EDGE('',*,*,#669,.F.);
#671=CARTESIAN_POINT('',(12.,0.,0.));
#672=DIRECTION('',(-1.,0.,0.));
#673=DIRECTION('',(0.,-0.173648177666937,0.984807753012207));
#674=AXIS2_PLACEMENT_3D('',#671,#672,#673);
#675=CIRCLE('',#674,16.749);
#676=CARTESIAN_POINT('',(12.,-16.4095148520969,-3.35511897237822));
#677=VERTEX_POINT('',#676);
#678=EDGE_CURVE('E1386',#677,#668,#675,.T.);
#679=ORIENTED_EDGE('',*,*,#678,.F.);
#680=CARTESIAN_POINT('',(12.,-13.640744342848,-10.0014645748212));
#681=DIRECTION('',(-1.,0.,0.));
#682=DIRECTION('',(0.,-0.173648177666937,0.984807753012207));
#683=AXIS2_PLACEMENT_3D('',#680,#681,#682);
#684=CIRCLE('',#683,7.2);
#685=CARTESIAN_POINT('',(12.,-18.4287050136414,-4.62415738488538));
#686=VERTEX_POINT('',#685);
#687=EDGE_CURVE('E1388',#686,#677,#684,.T.);
#688=ORIENTED_EDGE('',*,*,#687,.F.);
#689=CARTESIAN_POINT('',(12.,-18.2718053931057,-5.20971474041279));
#690=VERTEX_POINT('',#689);
#691=EDGE_CURVE('E1973',#690,#686,#68,.T.);
#692=ORIENTED_EDGE('',*,*,#691,.F.);
#693=CARTESIAN_POINT('',(12.,-16.8139634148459,1.84115022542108));
#694=DIRECTION('',(-1.,0.,0.));
#695=DIRECTION('',(0.,-0.342020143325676,0.939692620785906));
#696=AXIS2_PLACEMENT_3D('',#693,#694,#695);
#697=CIRCLE('',#696,7.2);
#698=CARTESIAN_POINT('',(12.,-15.888616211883,-5.29913916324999));
#699=VERTEX_POINT('',#698);
#700=EDGE_CURVE('E1412',#699,#690,#697,.T.);
#701=ORIENTED_EDGE('',*,*,#700,.F.);
#702=CARTESIAN_POINT('',(12.,0.,0.));
#703=DIRECTION('',(-1.,0.,0.));
#704=DIRECTION('',(0.,-0.342020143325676,0.939692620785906));
#705=AXIS2_PLACEMENT_3D('',#702,#703,#704);
#706=CIRCLE('',#705,16.749);
#707=CARTESIAN_POINT('',(12.,-15.5776071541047,-6.15362952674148));
#708=VERTEX_POINT('',#707);
#709=EDGE_CURVE('E1408',#708,#699,#706,.T.);
#710=ORIENTED_EDGE('',*,*,#709,.F.);
#711=CARTESIAN_POINT('',(12.,-11.696774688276,-12.2182102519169));
#712=DIRECTION('',(-1.,0.,0.));
#713=DIRECTION('',(0.,-0.342020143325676,0.939692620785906));
#714=AXIS2_PLACEMENT_3D('',#711,#712,#713);
#715=CIRCLE('',#714,7.2);
#716=CARTESIAN_POINT('',(12.,-17.3457550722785,-7.75401708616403));
#717=VERTEX_POINT('',#716);
#718=EDGE_CURVE('E1410',#717,#708,#715,.T.);
#719=ORIENTED_EDGE('',*,*,#718,.F.);
#720=CARTESIAN_POINT('',(12.,-17.0895581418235,-8.3034331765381));
#721=VERTEX_POINT('',#720);
#722=EDGE_CURVE('E1968',#721,#717,#68,.T.);
#723=ORIENTED_EDGE('',*,*,#722,.F.);
#724=CARTESIAN_POINT('',(12.,-16.8782339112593,-1.10653508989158));
#725=DIRECTION('',(-1.,0.,0.));
#726=DIRECTION('',(0.,-0.500000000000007,0.866025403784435));
#727=AXIS2_PLACEMENT_3D('',#724,#725,#726);
#728=CIRCLE('',#727,7.2);
#729=CARTESIAN_POINT('',(12.,-14.727046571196,-7.97766258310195));
#730=VERTEX_POINT('',#729);
#731=EDGE_CURVE('E1434',#730,#721,#728,.T.);
#732=ORIENTED_EDGE('',*,*,#731,.F.);
#733=CARTESIAN_POINT('',(12.,0.,0.));
#734=DIRECTION('',(-1.,0.,0.));
#735=DIRECTION('',(0.,-0.500000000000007,0.866025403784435));
#736=AXIS2_PLACEMENT_3D('',#733,#734,#735);
#737=CIRCLE('',#736,16.749);
#738=CARTESIAN_POINT('',(12.,-14.2723817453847,-8.76516516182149));
#739=VERTEX_POINT('',#738);
#740=EDGE_CURVE('E1430',#739,#730,#737,.T.);
#741=ORIENTED_EDGE('',*,*,#740,.F.);
#742=CARTESIAN_POINT('',(12.,-9.39740445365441,-14.0637117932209));
#743=DIRECTION('',(-1.,0.,0.));
#744=DIRECTION('',(0.,-0.500000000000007,0.866025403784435));
#745=AXIS2_PLACEMENT_3D('',#742,#743,#744);
#746=CIRCLE('',#745,7.2);
#747=CARTESIAN_POINT('',(12.,-15.7357631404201,-10.6482749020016));
#748=VERTEX_POINT('',#747);
#749=EDGE_CURVE('E1432',#748,#739,#746,.T.);
#750=ORIENTED_EDGE('',*,*,#749,.F.);
#751=CARTESIAN_POINT('',(12.,-15.3880533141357,-11.1448559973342));
#752=VERTEX_POINT('',#751);
#753=EDGE_CURVE('E1963',#752,#748,#68,.T.);
#754=ORIENTED_EDGE('',*,*,#753,.F.);
#755=CARTESIAN_POINT('',(12.,-16.4296678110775,-4.02059889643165));
#756=DIRECTION('',(-1.,0.,0.));
#757=DIRECTION('',(0.,-0.642787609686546,0.766044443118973));
#758=AXIS2_PLACEMENT_3D('',#755,#756,#757);
#759=CIRCLE('',#758,7.2);
#760=CARTESIAN_POINT('',(12.,-13.1180030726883,-10.4137887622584));
#761=VERTEX_POINT('',#760);
#762=EDGE_CURVE('E1456',#761,#752,#759,.T.);
#763=ORIENTED_EDGE('',*,*,#762,.F.);
#764=CARTESIAN_POINT('',(12.,0.,0.));
#765=DIRECTION('',(-1.,0.,0.));
#766=DIRECTION('',(0.,-0.642787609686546,0.766044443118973));
#767=AXIS2_PLACEMENT_3D('',#764,#765,#766);
#768=CIRCLE('',#767,16.749);
#769=CARTESIAN_POINT('',(12.,-12.5334972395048,-11.1103756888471));
#770=VERTEX_POINT('',#769);
#771=EDGE_CURVE('E1452',#770,#761,#768,.T.);
#772=ORIENTED_EDGE('',*,*,#771,.F.);
#773=CARTESIAN_POINT('',(12.,-6.81249884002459,-15.4818945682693));
#774=DIRECTION('',(-1.,0.,0.));
#775=DIRECTION('',(0.,-0.642787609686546,0.766044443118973));
#776=AXIS2_PLACEMENT_3D('',#773,#774,#775);
#777=CIRCLE('',#776,7.2);
#778=CARTESIAN_POINT('',(12.,-13.6476480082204,-13.2189902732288));
#779=VERTEX_POINT('',#778);
#780=EDGE_CURVE('E1454',#779,#770,#777,.T.);
#781=ORIENTED_EDGE('',*,*,#780,.F.);
#782=CARTESIAN_POINT('',(12.,-13.2189902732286,-13.6476480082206));
#783=VERTEX_POINT('',#782);
#784=EDGE_CURVE('E1958',#783,#779,#68,.T.);
#785=ORIENTED_EDGE('',*,*,#784,.F.);
#786=CARTESIAN_POINT('',(12.,-15.4818945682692,-6.81249884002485));
#787=DIRECTION('',(-1.,0.,0.));
#788=DIRECTION('',(0.,-0.766044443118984,0.642787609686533));
#789=AXIS2_PLACEMENT_3D('',#786,#787,#788);
#790=CIRCLE('',#789,7.2);
#791=CARTESIAN_POINT('',(12.,-11.1103756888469,-12.533497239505));
#792=VERTEX_POINT('',#791);
#793=EDGE_CURVE('E1478',#792,#783,#790,.T.);
#794=ORIENTED_EDGE('',*,*,#793,.F.);
#795=CARTESIAN_POINT('',(12.,0.,0.));
#796=DIRECTION('',(-1.,0.,0.));
#797=DIRECTION('',(0.,-0.766044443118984,0.642787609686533));
#798=AXIS2_PLACEMENT_3D('',#795,#796,#797);
#799=CIRCLE('',#798,16.749);
#800=CARTESIAN_POINT('',(12.,-10.4137887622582,-13.1180030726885));
#801=VERTEX_POINT('',#800);
#802=EDGE_CURVE('E1474',#801,#792,#799,.T.);
#803=ORIENTED_EDGE('',*,*,#802,.F.);
#804=CARTESIAN_POINT('',(12.,-4.02059889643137,-16.4296678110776));
#805=DIRECTION('',(-1.,0.,0.));
#806=DIRECTION('',(0.,-0.766044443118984,0.642787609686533));
#807=AXIS2_PLACEMENT_3D('',#804,#805,#806);
#808=CIRCLE('',#807,7.2);
#809=CARTESIAN_POINT('',(12.,-11.144855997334,-15.3880533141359));
#810=VERTEX_POINT('',#809);
#811=EDGE_CURVE('E1476',#810,#801,#808,.T.);
#812=ORIENTED_EDGE('',*,*,#811,.F.);
#813=CARTESIAN_POINT('',(12.,-10.6482749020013,-15.7357631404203));
#814=VERTEX_POINT('',#813);
#815=EDGE_CURVE('E1953',#814,#810,#68,.T.);
#816=ORIENTED_EDGE('',*,*,#815,.F.);
#817=CARTESIAN_POINT('',(12.,-14.0637117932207,-9.39740445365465));
#818=DIRECTION('',(-1.,0.,0.));
#819=DIRECTION('',(0.,-0.866025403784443,0.499999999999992));
#820=AXIS2_PLACEMENT_3D('',#817,#818,#819);
#821=CIRCLE('',#820,7.2);
#822=CARTESIAN_POINT('',(12.,-8.76516516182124,-14.2723817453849));
#823=VERTEX_POINT('',#822);
#824=EDGE_CURVE('E1500',#823,#814,#821,.T.);
#825=ORIENTED_EDGE('',*,*,#824,.F.);
#826=CARTESIAN_POINT('',(12.,0.,0.));
#827=DIRECTION('',(-1.,0.,0.));
#828=DIRECTION('',(0.,-0.866025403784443,0.499999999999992));
#829=AXIS2_PLACEMENT_3D('',#826,#827,#828);
#830=CIRCLE('',#829,16.749);
#831=CARTESIAN_POINT('',(12.,-7.97766258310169,-14.7270465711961));
#832=VERTEX_POINT('',#831);
#833=EDGE_CURVE('E1496',#832,#823,#830,.T.);
#834=ORIENTED_EDGE('',*,*,#833,.F.);
#835=CARTESIAN_POINT('',(12.,-1.10653508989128,-16.8782339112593));
#836=DIRECTION('',(-1.,0.,0.));
#837=DIRECTION('',(0.,-0.866025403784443,0.499999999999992));
#838=AXIS2_PLACEMENT_3D('',#835,#836,#837);
#839=CIRCLE('',#838,7.2);
#840=CARTESIAN_POINT('',(12.,-8.30343317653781,-17.0895581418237));
#841=VERTEX_POINT('',#840);
#842=EDGE_CURVE('E1498',#841,#832,#839,.T.);
#843=ORIENTED_EDGE('',*,*,#842,.F.);
#844=CARTESIAN_POINT('',(12.,-7.75401708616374,-17.3457550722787));
#845=VERTEX_POINT('',#844);
#846=EDGE_CURVE('E1948',#845,#841,#68,.T.);
#847=ORIENTED_EDGE('',*,*,#846,.F.);
#848=CARTESIAN_POINT('',(12.,-12.2182102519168,-11.6967746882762));
#849=DIRECTION('',(-1.,0.,0.));
#850=DIRECTION('',(0.,-0.939692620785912,0.34202014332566));
#851=AXIS2_PLACEMENT_3D('',#848,#849,#850);
#852=CIRCLE('',#851,7.2);
#853=CARTESIAN_POINT('',(12.,-6.15362952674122,-15.5776071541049));
#854=VERTEX_POINT('',#853);
#855=EDGE_CURVE('E1522',#854,#845,#852,.T.);
#856=ORIENTED_EDGE('',*,*,#855,.F.);
#857=CARTESIAN_POINT('',(12.,0.,0.));
#858=DIRECTION('',(-1.,0.,0.));
#859=DIRECTION('',(0.,-0.939692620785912,0.34202014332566));
#860=AXIS2_PLACEMENT_3D('',#857,#858,#859);
#861=CIRCLE('',#860,16.749);
#862=CARTESIAN_POINT('',(12.,-5.29913916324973,-15.8886162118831));
#863=VERTEX_POINT('',#862);
#864=EDGE_CURVE('E1518',#863,#854,#861,.T.);
#865=ORIENTED_EDGE('',*,*,#864,.F.);
#866=CARTESIAN_POINT('',(12.,1.84115022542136,-16.8139634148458));
#867=DIRECTION('',(-1.,0.,0.));
#868=DIRECTION('',(0.,-0.939692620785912,0.34202014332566));
#869=AXIS2_PLACEMENT_3D('',#866,#867,#868);
#870=CIRCLE('',#869,7.2);
#871=CARTESIAN_POINT('',(12.,-5.20971474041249,-18.2718053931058));
#872=VERTEX_POINT('',#871);
#873=EDGE_CURVE('E1520',#872,#863,#870,.T.);
#874=ORIENTED_EDGE('',*,*,#873,.F.);
#875=CARTESIAN_POINT('',(12.,-4.62415738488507,-18.4287050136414));
#876=VERTEX_POINT('',#875);
#877=EDGE_CURVE('E1943',#876,#872,#68,.T.);
#878=ORIENTED_EDGE('',*,*,#877,.F.);
#879=CARTESIAN_POINT('',(12.,-10.001464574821,-13.6407443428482));
#880=DIRECTION('',(-1.,0.,0.));
#881=DIRECTION('',(0.,-0.98480775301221,0.173648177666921));
#882=AXIS2_PLACEMENT_3D('',#879,#880,#881);
#883=CIRCLE('',#882,7.2);
#884=CARTESIAN_POINT('',(12.,-3.35511897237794,-16.4095148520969));
#885=VERTEX_POINT('',#884);
#886=EDGE_CURVE('E1544',#885,#876,#883,.T.);
#887=ORIENTED_EDGE('',*,*,#886,.F.);
#888=CARTESIAN_POINT('',(12.,0.,0.));
#889=DIRECTION('',(-1.,0.,0.));
#890=DIRECTION('',(0.,-0.98480775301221,0.173648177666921));
#891=AXIS2_PLACEMENT_3D('',#888,#889,#890);
#892=CIRCLE('',#891,16.749);
#893=CARTESIAN_POINT('',(12.,-2.4596040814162,-16.5674182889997));
#894=VERTEX_POINT('',#893);
#895=EDGE_CURVE('E1540',#894,#885,#892,.T.);
#896=ORIENTED_EDGE('',*,*,#895,.F.);
#897=CARTESIAN_POINT('',(12.,4.73289312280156,-16.2388091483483));
#898=DIRECTION('',(-1.,0.,0.));
#899=DIRECTION('',(0.,-0.98480775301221,0.173648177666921));
#900=AXIS2_PLACEMENT_3D('',#897,#898,#899);
#901=CIRCLE('',#900,7.2);
#902=CARTESIAN_POINT('',(12.,-1.95770175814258,-18.898873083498));
#903=VERTEX_POINT('',#902);
#904=EDGE_CURVE('E1542',#903,#894,#901,.T.);
#905=ORIENTED_EDGE('',*,*,#904,.F.);
#906=CARTESIAN_POINT('',(12.,-1.3537950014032,-18.9517080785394));
#907=VERTEX_POINT('',#906);
#908=EDGE_CURVE('E1938',#907,#903,#68,.T.);
#909=ORIENTED_EDGE('',*,*,#908,.F.);
#910=CARTESIAN_POINT('',(12.,-7.48082945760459,-15.1702468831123));
#911=DIRECTION('',(-1.,0.,0.));
#912=DIRECTION('',(0.,-1.,0.));
#913=AXIS2_PLACEMENT_3D('',#910,#911,#912);
#914=CIRCLE('',#913,7.2);
#915=CARTESIAN_POINT('',(12.,-0.454664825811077,-16.7428277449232));
#916=VERTEX_POINT('',#915);
#917=EDGE_CURVE('E1566',#916,#907,#914,.T.);
#918=ORIENTED_EDGE('',*,*,#917,.F.);
#919=CARTESIAN_POINT('',(12.,0.,0.));
#920=DIRECTION('',(-1.,0.,0.));
#921=DIRECTION('',(0.,-1.,0.));
#922=AXIS2_PLACEMENT_3D('',#919,#920,#921);
#923=CIRCLE('',#922,16.749);
#924=CARTESIAN_POINT('',(12.,0.454664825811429,-16.7428277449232));
#925=VERTEX_POINT('',#924);
#926=EDGE_CURVE('E1562',#925,#916,#923,.T.);
#927=ORIENTED_EDGE('',*,*,#926,.F.);
#928=CARTESIAN_POINT('',(12.,7.48082945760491,-15.1702468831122));
#929=DIRECTION('',(-1.,0.,0.));
#930=DIRECTION('',(0.,-1.,0.));
#931=AXIS2_PLACEMENT_3D('',#928,#929,#930);
#932=CIRCLE('',#931,7.2);
#933=CARTESIAN_POINT('',(12.,1.3537950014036,-18.9517080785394));
#934=VERTEX_POINT('',#933);
#935=EDGE_CURVE('E1564',#934,#925,#932,.T.);
#936=ORIENTED_EDGE('',*,*,#935,.F.);
#937=CARTESIAN_POINT('',(12.,1.95770175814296,-18.898873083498));
#938=VERTEX_POINT('',#937);
#939=EDGE_CURVE('E1933',#938,#934,#68,.T.);
#940=ORIENTED_EDGE('',*,*,#939,.F.);
#941=CARTESIAN_POINT('',(12.,-4.73289312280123,-16.2388091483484));
#942=DIRECTION('',(-1.,0.,0.));
#943=DIRECTION('',(0.,-0.984807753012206,-0.17364817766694));
#944=AXIS2_PLACEMENT_3D('',#941,#942,#943);
#945=CIRCLE('',#944,7.2);
#946=CARTESIAN_POINT('',(12.,2.45960408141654,-16.5674182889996));
#947=VERTEX_POINT('',#946);
#948=EDGE_CURVE('E1588',#947,#938,#945,.T.);
#949=ORIENTED_EDGE('',*,*,#948,.F.);
#950=CARTESIAN_POINT('',(12.,0.,0.));
#951=DIRECTION('',(-1.,0.,0.));
#952=DIRECTION('',(0.,-0.984807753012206,-0.17364817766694));
#953=AXIS2_PLACEMENT_3D('',#950,#951,#952);
#954=CIRCLE('',#953,16.749);
#955=CARTESIAN_POINT('',(12.,3.35511897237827,-16.4095148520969));
#956=VERTEX_POINT('',#955);
#957=EDGE_CURVE('E1584',#956,#947,#954,.T.);
#958=ORIENTED_EDGE('',*,*,#957,.F.);
#959=CARTESIAN_POINT('',(12.,10.0014645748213,-13.640744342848));
#960=DIRECTION('',(-1.,0.,0.));
#961=DIRECTION('',(0.,-0.984807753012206,-0.17364817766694));
#962=AXIS2_PLACEMENT_3D('',#959,#960,#961);
#963=CIRCLE('',#962,7.2);
#964=CARTESIAN_POINT('',(12.,4.62415738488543,-18.4287050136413));
#965=VERTEX_POINT('',#964);
#966=EDGE_CURVE('E1586',#965,#956,#963,.T.);
#967=ORIENTED_EDGE('',*,*,#966,.F.);
#968=CARTESIAN_POINT('',(12.,5.20971474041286,-18.2718053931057));
#969=VERTEX_POINT('',#968);
#970=EDGE_CURVE('E1928',#969,#965,#68,.T.);
#971=ORIENTED_EDGE('',*,*,#970,.F.);
#972=CARTESIAN_POINT('',(12.,-1.84115022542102,-16.8139634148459));
#973=DIRECTION('',(-1.,0.,0.));
#974=DIRECTION('',(0.,-0.939692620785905,-0.342020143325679));
#975=AXIS2_PLACEMENT_3D('',#972,#973,#974);
#976=CIRCLE('',#975,7.2);
#977=CARTESIAN_POINT('',(12.,5.29913916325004,-15.8886162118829));
#978=VERTEX_POINT('',#977);
#979=EDGE_CURVE('E1610',#978,#969,#976,.T.);
#980=ORIENTED_EDGE('',*,*,#979,.F.);
#981=CARTESIAN_POINT('',(12.,0.,0.));
#982=DIRECTION('',(-1.,0.,0.));
#983=DIRECTION('',(0.,-0.939692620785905,-0.342020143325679));
#984=AXIS2_PLACEMENT_3D('',#981,#982,#983);
#985=CIRCLE('',#984,16.749);
#986=CARTESIAN_POINT('',(12.,6.15362952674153,-15.5776071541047));
#987=VERTEX_POINT('',#986);
#988=EDGE_CURVE('E1606',#987,#978,#985,.T.);
#989=ORIENTED_EDGE('',*,*,#988,.F.);
#990=CARTESIAN_POINT('',(12.,12.218210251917,-11.696774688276));
#991=DIRECTION('',(-1.,0.,0.));
#992=DIRECTION('',(0.,-0.939692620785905,-0.342020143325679));
#993=AXIS2_PLACEMENT_3D('',#990,#991,#992);
#994=CIRCLE('',#993,7.2);
#995=CARTESIAN_POINT('',(12.,7.75401708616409,-17.3457550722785));
#996=VERTEX_POINT('',#995);
#997=EDGE_CURVE('E1608',#996,#987,#994,.T.);
#998=ORIENTED_EDGE('',*,*,#997,.F.);
#999=CARTESIAN_POINT('',(12.,8.30343317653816,-17.0895581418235));
#1000=VERTEX_POINT('',#999);
#1001=EDGE_CURVE('E1923',#1000,#996,#68,.T.);
#1002=ORIENTED_EDGE('',*,*,#1001,.F.);
#1003=CARTESIAN_POINT('',(12.,1.10653508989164,-16.8782339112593));
#1004=DIRECTION('',(-1.,0.,0.));
#1005=DIRECTION('',(0.,-0.866025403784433,-0.50000000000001));
#1006=AXIS2_PLACEMENT_3D('',#1003,#1004,#1005);
#1007=CIRCLE('',#1006,7.2);
#1008=CARTESIAN_POINT('',(12.,7.977662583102,-14.7270465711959));
#1009=VERTEX_POINT('',#1008);
#1010=EDGE_CURVE('E1632',#1009,#1000,#1007,.T.);
#1011=ORIENTED_EDGE('',*,*,#1010,.F.);
#1012=CARTESIAN_POINT('',(12.,0.,0.));
#1013=DIRECTION('',(-1.,0.,0.));
#1014=DIRECTION('',(0.,-0.866025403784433,-0.50000000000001));
#1015=AXIS2_PLACEMENT_3D('',#1012,#1013,#1014);
#1016=CIRCLE('',#1015,16.749);
#1017=CARTESIAN_POINT('',(12.,8.76516516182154,-14.2723817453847));
#1018=VERTEX_POINT('',#1017);
#1019=EDGE_CURVE('E1628',#1018,#1009,#1016,.T.);
#1020=ORIENTED_EDGE('',*,*,#1019,.F.);
#1021=CARTESIAN_POINT('',(12.,14.0637117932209,-9.39740445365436));
#1022=DIRECTION('',(-1.,0.,0.));
#1023=DIRECTION('',(0.,-0.866025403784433,-0.50000000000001));
#1024=AXIS2_PLACEMENT_3D('',#1021,#1022,#1023);
#1025=CIRCLE('',#1024,7.2);
#1026=CARTESIAN_POINT('',(12.,10.6482749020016,-15.7357631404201));
#1027=VERTEX_POINT('',#1026);
#1028=EDGE_CURVE('E1630',#1027,#1018,#1025,.T.);
#1029=ORIENTED_EDGE('',*,*,#1028,.F.);
#1030=CARTESIAN_POINT('',(12.,11.1448559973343,-15.3880533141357));
#1031=VERTEX_POINT('',#1030);
#1032=EDGE_CURVE('E1918',#1031,#1027,#68,.T.);
#1033=ORIENTED_EDGE('',*,*,#1032,.F.);
#1034=CARTESIAN_POINT('',(12.,4.0205988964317,-16.4296678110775));
#1035=DIRECTION('',(-1.,0.,0.));
#1036=DIRECTION('',(0.,-0.766044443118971,-0.642787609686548));
#1037=AXIS2_PLACEMENT_3D('',#1034,#1035,#1036);
#1038=CIRCLE('',#1037,7.2);
#1039=CARTESIAN_POINT('',(12.,10.4137887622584,-13.1180030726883));
#1040=VERTEX_POINT('',#1039);
#1041=EDGE_CURVE('E1654',#1040,#1031,#1038,.T.);
#1042=ORIENTED_EDGE('',*,*,#1041,.F.);
#1043=CARTESIAN_POINT('',(12.,0.,0.));
#1044=DIRECTION('',(-1.,0.,0.));
#1045=DIRECTION('',(0.,-0.766044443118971,-0.642787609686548));
#1046=AXIS2_PLACEMENT_3D('',#1043,#1044,#1045);
#1047=CIRCLE('',#1046,16.749);
#1048=CARTESIAN_POINT('',(12.,11.1103756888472,-12.5334972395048));
#1049=VERTEX_POINT('',#1048);
#1050=EDGE_CURVE('E1650',#1049,#1040,#1047,.T.);
#1051=ORIENTED_EDGE('',*,*,#1050,.F.);
#1052=CARTESIAN_POINT('',(12.,15.4818945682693,-6.81249884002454));
#1053=DIRECTION('',(-1.,0.,0.));
#1054=DIRECTION('',(0.,-0.766044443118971,-0.642787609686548));
#1055=AXIS2_PLACEMENT_3D('',#1052,#1053,#1054);
#1056=CIRCLE('',#1055,7.2);
#1057=CARTESIAN_POINT('',(12.,13.2189902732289,-13.6476480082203));
#1058=VERTEX_POINT('',#1057);
#1059=EDGE_CURVE('E1652',#1058,#1049,#1056,.T.);
#1060=ORIENTED_EDGE('',*,*,#1059,.F.);
#1061=CARTESIAN_POINT('',(12.,13.6476480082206,-13.2189902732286));
#1062=VERTEX_POINT('',#1061);
#1063=EDGE_CURVE('E1913',#1062,#1058,#68,.T.);
#1064=ORIENTED_EDGE('',*,*,#1063,.F.);
#1065=CARTESIAN_POINT('',(12.,6.81249884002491,-15.4818945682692));
#1066=DIRECTION('',(-1.,0.,0.));
#1067=DIRECTION('',(0.,-0.64278760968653,-0.766044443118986));
#1068=AXIS2_PLACEMENT_3D('',#1065,#1066,#1067);
#1069=CIRCLE('',#1068,7.2);
#1070=CARTESIAN_POINT('',(12.,12.533497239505,-11.1103756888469));
#1071=VERTEX_POINT('',#1070);
#1072=EDGE_CURVE('E1676',#1071,#1062,#1069,.T.);
#1073=ORIENTED_EDGE('',*,*,#1072,.F.);
#1074=CARTESIAN_POINT('',(12.,0.,0.));
#1075=DIRECTION('',(-1.,0.,0.));
#1076=DIRECTION('',(0.,-0.64278760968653,-0.766044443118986));
#1077=AXIS2_PLACEMENT_3D('',#1074,#1075,#1076);
#1078=CIRCLE('',#1077,16.749);
#1079=CARTESIAN_POINT('',(12.,13.1180030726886,-10.4137887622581));
#1080=VERTEX_POINT('',#1079);
#1081=EDGE_CURVE('E1672',#1080,#1071,#1078,.T.);
#1082=ORIENTED_EDGE('',*,*,#1081,.F.);
#1083=CARTESIAN_POINT('',(12.,16.4296678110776,-4.02059889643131));
#1084=DIRECTION('',(-1.,0.,0.));
#1085=DIRECTION('',(0.,-0.64278760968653,-0.766044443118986));
#1086=AXIS2_PLACEMENT_3D('',#1083,#1084,#1085);
#1087=CIRCLE('',#1086,7.2);
#1088=CARTESIAN_POINT('',(12.,15.388053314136,-11.1448559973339));
#1089=VERTEX_POINT('',#1088);
#1090=EDGE_CURVE('E1674',#1089,#1080,#1087,.T.);
#1091=ORIENTED_EDGE('',*,*,#1090,.F.);
#1092=CARTESIAN_POINT('',(12.,15.7357631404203,-10.6482749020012));
#1093=VERTEX_POINT('',#1092);
#1094=EDGE_CURVE('E1908',#1093,#1089,#68,.T.);
#1095=ORIENTED_EDGE('',*,*,#1094,.F.);
#1096=CARTESIAN_POINT('',(12.,9.3974044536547,-14.0637117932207));
#1097=DIRECTION('',(-1.,0.,0.));
#1098=DIRECTION('',(0.,-0.499999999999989,-0.866025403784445));
#1099=AXIS2_PLACEMENT_3D('',#1096,#1097,#1098);
#1100=CIRCLE('',#1099,7.2);
#1101=CARTESIAN_POINT('',(12.,14.2723817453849,-8.76516516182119));
#1102=VERTEX_POINT('',#1101);
#1103=EDGE_CURVE('E1698',#1102,#1093,#1100,.T.);
#1104=ORIENTED_EDGE('',*,*,#1103,.F.);
#1105=CARTESIAN_POINT('',(12.,0.,0.));
#1106=DIRECTION('',(-1.,0.,0.));
#1107=DIRECTION('',(0.,-0.499999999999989,-0.866025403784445));
#1108=AXIS2_PLACEMENT_3D('',#1105,#1106,#1107);
#1109=CIRCLE('',#1108,16.749);
#1110=CARTESIAN_POINT('',(12.,14.7270465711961,-7.97766258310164));
#1111=VERTEX_POINT('',#1110);
#1112=EDGE_CURVE('E1694',#1111,#1102,#1109,.T.);
#1113=ORIENTED_EDGE('',*,*,#1112,.F.);
#1114=CARTESIAN_POINT('',(12.,16.8782339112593,-1.10653508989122));
#1115=DIRECTION('',(-1.,0.,0.));
#1116=DIRECTION('',(0.,-0.499999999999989,-0.866025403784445));
#1117=AXIS2_PLACEMENT_3D('',#1114,#1115,#1116);
#1118=CIRCLE('',#1117,7.2);
#1119=CARTESIAN_POINT('',(12.,17.0895581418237,-8.30343317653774));
#1120=VERTEX_POINT('',#1119);
#1121=EDGE_CURVE('E1696',#1120,#1111,#1118,.T.);
#1122=ORIENTED_EDGE('',*,*,#1121,.F.);
#1123=CARTESIAN_POINT('',(12.,17.3457550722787,-7.75401708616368));
#1124=VERTEX_POINT('',#1123);
#1125=EDGE_CURVE('E1907',#1124,#1120,#68,.T.);
#1126=ORIENTED_EDGE('',*,*,#1125,.F.);
#1127=CARTESIAN_POINT('',(12.,11.6967746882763,-12.2182102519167));
#1128=DIRECTION('',(-1.,0.,0.));
#1129=DIRECTION('',(0.,-0.342020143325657,-0.939692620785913));
#1130=AXIS2_PLACEMENT_3D('',#1127,#1128,#1129);
#1131=CIRCLE('',#1130,7.2);
#1132=CARTESIAN_POINT('',(12.,15.5776071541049,-6.15362952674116));
#1133=VERTEX_POINT('',#1132);
#1134=EDGE_CURVE('E1719',#1133,#1124,#1131,.T.);
#1135=ORIENTED_EDGE('',*,*,#1134,.F.);
#1136=CARTESIAN_POINT('',(12.,0.,0.));
#1137=DIRECTION('',(-1.,0.,0.));
#1138=DIRECTION('',(0.,-0.342020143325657,-0.939692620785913));
#1139=AXIS2_PLACEMENT_3D('',#1136,#1137,#1138);
#1140=CIRCLE('',#1139,16.749);
#1141=CARTESIAN_POINT('',(12.,15.8886162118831,-5.29913916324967));
#1142=VERTEX_POINT('',#1141);
#1143=EDGE_CURVE('E1715',#1142,#1133,#1140,.T.);
#1144=ORIENTED_EDGE('',*,*,#1143,.F.);
#1145=CARTESIAN_POINT('',(12.,16.8139634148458,1.84115022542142));
#1146=DIRECTION('',(-1.,0.,0.));
#1147=DIRECTION('',(0.,-0.342020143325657,-0.939692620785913));
#1148=AXIS2_PLACEMENT_3D('',#1145,#1146,#1147);
#1149=CIRCLE('',#1148,7.2);
#1150=CARTESIAN_POINT('',(12.,18.2718053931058,-5.20971474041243));
#1151=VERTEX_POINT('',#1150);
#1152=EDGE_CURVE('E1717',#1151,#1142,#1149,.T.);
#1153=ORIENTED_EDGE('',*,*,#1152,.F.);
#1154=EDGE_CURVE('E1799',#43,#1151,#68,.T.);
#1155=ORIENTED_EDGE('',*,*,#1154,.F.);
#1156=EDGE_LOOP('',(#45,#54,#63,#72,#81,#90,#99,#103,#112,#121,#130,#134,#143,#152,#161,#165,
#174,#183,#192,#196,#205,#214,#223,#227,#236,#245,#254,#258,#267,#276,#285,#289,#298,#307,#316,
#320,#329,#338,#347,#351,#360,#369,#378,#382,#391,#400,#409,#413,#422,#431,#440,#444,#453,#462,
#471,#475,#484,#493,#502,#506,#515,#524,#533,#537,#546,#555,#564,#568,#577,#586,#595,#599,#608,
#617,#626,#630,#639,#648,#657,#661,#670,#679,#688,#692,#701,#710,#719,#723,#732,#741,#750,#754,
#763,#772,#781,#785,#794,#803,#812,#816,#825,#834,#843,#847,#856,#865,#874,#878,#887,#896,#905,
#909,#918,#927,#936,#940,#949,#958,#967,#971,#980,#989,#998,#1002,#1011,#1020,#1029,#1033,#1042,
#1051,#1060,#1064,#1073,#1082,#1091,#1095,#1104,#1113,#1122,#1126,#1135,#1144,#1153,#1155));
#1157=FACE_BOUND('',#1156,.T.);
#1158=CARTESIAN_POINT('',(12.,0.,0.));
#1159=DIRECTION('',(-1.,0.,0.));
#1160=DIRECTION('',(0.,0.,1.));
#1161=AXIS2_PLACEMENT_3D('',#1158,#1159,#1160);
#1162=CIRCLE('',#1161,6.);
#1163=CARTESIAN_POINT('',(12.,0.,6.));
#1164=VERTEX_POINT('',#1163);
#1165=EDGE_CURVE('E1734',#1164,#1164,#1162,.F.);
#1166=ORIENTED_EDGE('',*,*,#1165,.F.);
#1167=EDGE_LOOP('',(#1166));
#1168=FACE_BOUND('',#1167,.T.);
#1169=ADVANCED_FACE('F37',(#34,#1157,#1168),#23,.F.);
#1170=CARTESIAN_POINT('',(0.,0.,0.));
#1171=DIRECTION('',(1.,0.,0.));
#1172=DIRECTION('',(0.,0.,-1.));
#1173=AXIS2_PLACEMENT_3D('',#1170,#1171,#1172);
#1174=PLANE('',#1173);
#1175=CARTESIAN_POINT('',(0.,12.2072193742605,0.));
#1176=DIRECTION('',(-1.,0.,0.));
#1177=DIRECTION('',(0.,0.,1.));
#1178=AXIS2_PLACEMENT_3D('',#1175,#1176,#1177);
#1179=CIRCLE('',#1178,1.74146852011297);
#1180=CARTESIAN_POINT('',(0.,12.2072193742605,1.74146852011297));
#1181=VERTEX_POINT('',#1180);
#1182=EDGE_CURVE('E1737',#1181,#1181,#1179,.T.);
#1183=ORIENTED_EDGE('',*,*,#1182,.F.);
#1184=EDGE_LOOP('',(#1183));
#1185=FACE_BOUND('',#1184,.T.);
#1186=CARTESIAN_POINT('',(0.,13.6407443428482,-10.001464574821));
#1187=DIRECTION('',(-1.,0.,0.));
#1188=DIRECTION('',(0.,-0.173648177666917,-0.984807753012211));
#1189=AXIS2_PLACEMENT_3D('',#1186,#1187,#1188);
#1190=CIRCLE('',#1189,7.2);
#1191=CARTESIAN_POINT('',(0.,16.4095148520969,-3.35511897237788));
#1192=VERTEX_POINT('',#1191);
#1193=CARTESIAN_POINT('',(0.,18.4287050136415,-4.624157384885));
#1194=VERTEX_POINT('',#1193);
#1195=EDGE_CURVE('E52',#1192,#1194,#1190,.T.);
#1196=ORIENTED_EDGE('',*,*,#1195,.T.);
#1197=CARTESIAN_POINT('',(0.,0.,0.));
#1198=DIRECTION('',(-1.,0.,0.));
#1199=DIRECTION('',(0.,0.,1.));
#1200=AXIS2_PLACEMENT_3D('',#1197,#1198,#1199);
#1201=CIRCLE('',#1200,19.);
#1202=CARTESIAN_POINT('',(0.,18.2718053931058,-5.20971474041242));
#1203=VERTEX_POINT('',#1202);
#1204=EDGE_CURVE('E947',#1194,#1203,#1201,.T.);
#1205=ORIENTED_EDGE('',*,*,#1204,.T.);
#1206=CARTESIAN_POINT('',(0.,16.8139634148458,1.84115022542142));
#1207=DIRECTION('',(1.,0.,0.));
#1208=DIRECTION('',(0.,0.,-1.));
#1209=AXIS2_PLACEMENT_3D('',#1206,#1207,#1208);
#1210=CIRCLE('',#1209,7.2);
#1211=CARTESIAN_POINT('',(0.,15.8886162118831,-5.29913916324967));
#1212=VERTEX_POINT('',#1211);
#1213=EDGE_CURVE('E45',#1212,#1203,#1210,.T.);
#1214=ORIENTED_EDGE('',*,*,#1213,.F.);
#1215=CARTESIAN_POINT('',(0.,0.,0.));
#1216=DIRECTION('',(-1.,0.,0.));
#1217=DIRECTION('',(0.,-0.342020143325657,-0.939692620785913));
#1218=AXIS2_PLACEMENT_3D('',#1215,#1216,#1217);
#1219=CIRCLE('',#1218,16.749);
#1220=CARTESIAN_POINT('',(0.,15.5776071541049,-6.15362952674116));
#1221=VERTEX_POINT('',#1220);
#1222=EDGE_CURVE('E1721',#1212,#1221,#1219,.T.);
#1223=ORIENTED_EDGE('',*,*,#1222,.T.);
#1224=CARTESIAN_POINT('',(0.,11.6967746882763,-12.2182102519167));
#1225=DIRECTION('',(-1.,0.,0.));
#1226=DIRECTION('',(0.,-0.342020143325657,-0.939692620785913));
#1227=AXIS2_PLACEMENT_3D('',#1224,#1225,#1226);
#1228=CIRCLE('',#1227,7.2);
#1229=CARTESIAN_POINT('',(0.,17.3457550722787,-7.75401708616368));
#1230=VERTEX_POINT('',#1229);
#1231=EDGE_CURVE('E60',#1221,#1230,#1228,.T.);
#1232=ORIENTED_EDGE('',*,*,#1231,.T.);
#1233=CARTESIAN_POINT('',(0.,17.0895581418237,-8.30343317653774));
#1234=VERTEX_POINT('',#1233);
#1235=EDGE_CURVE('E953',#1230,#1234,#1201,.T.);
#1236=ORIENTED_EDGE('',*,*,#1235,.T.);
#1237=CARTESIAN_POINT('',(0.,16.8782339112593,-1.10653508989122));
#1238=DIRECTION('',(1.,0.,0.));
#1239=DIRECTION('',(0.,0.,-1.));
#1240=AXIS2_PLACEMENT_3D('',#1237,#1238,#1239);
#1241=CIRCLE('',#1240,7.2);
#1242=CARTESIAN_POINT('',(0.,14.7270465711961,-7.97766258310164));
#1243=VERTEX_POINT('',#1242);
#1244=EDGE_CURVE('E1893',#1243,#1234,#1241,.T.);
#1245=ORIENTED_EDGE('',*,*,#1244,.F.);
#1246=CARTESIAN_POINT('',(0.,0.,0.));
#1247=DIRECTION('',(-1.,0.,0.));
#1248=DIRECTION('',(0.,-0.499999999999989,-0.866025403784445));
#1249=AXIS2_PLACEMENT_3D('',#1246,#1247,#1248);
#1250=CIRCLE('',#1249,16.749);
#1251=CARTESIAN_POINT('',(0.,14.2723817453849,-8.76516516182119));
#1252=VERTEX_POINT('',#1251);
#1253=EDGE_CURVE('E1700',#1243,#1252,#1250,.T.);
#1254=ORIENTED_EDGE('',*,*,#1253,.T.);
#1255=CARTESIAN_POINT('',(0.,9.3974044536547,-14.0637117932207));
#1256=DIRECTION('',(-1.,0.,0.));
#1257=DIRECTION('',(0.,-0.499999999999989,-0.866025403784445));
#1258=AXIS2_PLACEMENT_3D('',#1255,#1256,#1257);
#1259=CIRCLE('',#1258,7.2);
#1260=CARTESIAN_POINT('',(0.,15.7357631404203,-10.6482749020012));
#1261=VERTEX_POINT('',#1260);
#1262=EDGE_CURVE('E1703',#1252,#1261,#1259,.T.);
#1263=ORIENTED_EDGE('',*,*,#1262,.T.);
#1264=CARTESIAN_POINT('',(0.,15.388053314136,-11.1448559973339));
#1265=VERTEX_POINT('',#1264);
#1266=EDGE_CURVE('E2181',#1261,#1265,#1201,.T.);
#1267=ORIENTED_EDGE('',*,*,#1266,.T.);
#1268=CARTESIAN_POINT('',(0.,16.4296678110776,-4.02059889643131));
#1269=DIRECTION('',(1.,0.,0.));
#1270=DIRECTION('',(0.,0.,-1.));
#1271=AXIS2_PLACEMENT_3D('',#1268,#1269,#1270);
#1272=CIRCLE('',#1271,7.2);
#1273=CARTESIAN_POINT('',(0.,13.1180030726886,-10.4137887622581));
#1274=VERTEX_POINT('',#1273);
#1275=EDGE_CURVE('E1890',#1274,#1265,#1272,.T.);
#1276=ORIENTED_EDGE('',*,*,#1275,.F.);
#1277=CARTESIAN_POINT('',(0.,0.,0.));
#1278=DIRECTION('',(-1.,0.,0.));
#1279=DIRECTION('',(0.,-0.64278760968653,-0.766044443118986));
#1280=AXIS2_PLACEMENT_3D('',#1277,#1278,#1279);
#1281=CIRCLE('',#1280,16.749);
#1282=CARTESIAN_POINT('',(0.,12.533497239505,-11.1103756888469));
#1283=VERTEX_POINT('',#1282);
#1284=EDGE_CURVE('E1678',#1274,#1283,#1281,.T.);
#1285=ORIENTED_EDGE('',*,*,#1284,.T.);
#1286=CARTESIAN_POINT('',(0.,6.81249884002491,-15.4818945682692));
#1287=DIRECTION('',(-1.,0.,0.));
#1288=DIRECTION('',(0.,-0.64278760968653,-0.766044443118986));
#1289=AXIS2_PLACEMENT_3D('',#1286,#1287,#1288);
#1290=CIRCLE('',#1289,7.2);
#1291=CARTESIAN_POINT('',(0.,13.6476480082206,-13.2189902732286));
#1292=VERTEX_POINT('',#1291);
#1293=EDGE_CURVE('E1681',#1283,#1292,#1290,.T.);
#1294=ORIENTED_EDGE('',*,*,#1293,.T.);
#1295=CARTESIAN_POINT('',(0.,13.2189902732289,-13.6476480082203));
#1296=VERTEX_POINT('',#1295);
#1297=EDGE_CURVE('E2178',#1292,#1296,#1201,.T.);
#1298=ORIENTED_EDGE('',*,*,#1297,.T.);
#1299=CARTESIAN_POINT('',(0.,15.4818945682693,-6.81249884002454));
#1300=DIRECTION('',(1.,0.,0.));
#1301=DIRECTION('',(0.,0.,-1.));
#1302=AXIS2_PLACEMENT_3D('',#1299,#1300,#1301);
#1303=CIRCLE('',#1302,7.2);
#1304=CARTESIAN_POINT('',(0.,11.1103756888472,-12.5334972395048));
#1305=VERTEX_POINT('',#1304);
#1306=EDGE_CURVE('E1887',#1305,#1296,#1303,.T.);
#1307=ORIENTED_EDGE('',*,*,#1306,.F.);
#1308=CARTESIAN_POINT('',(0.,0.,0.));
#1309=DIRECTION('',(-1.,0.,0.));
#1310=DIRECTION('',(0.,-0.766044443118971,-0.642787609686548));
#1311=AXIS2_PLACEMENT_3D('',#1308,#1309,#1310);
#1312=CIRCLE('',#1311,16.749);
#1313=CARTESIAN_POINT('',(0.,10.4137887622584,-13.1180030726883));
#1314=VERTEX_POINT('',#1313);
#1315=EDGE_CURVE('E1656',#1305,#1314,#1312,.T.);
#1316=ORIENTED_EDGE('',*,*,#1315,.T.);
#1317=CARTESIAN_POINT('',(0.,4.0205988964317,-16.4296678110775));
#1318=DIRECTION('',(-1.,0.,0.));
#1319=DIRECTION('',(0.,-0.766044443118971,-0.642787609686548));
#1320=AXIS2_PLACEMENT_3D('',#1317,#1318,#1319);
#1321=CIRCLE('',#1320,7.2);
#1322=CARTESIAN_POINT('',(0.,11.1448559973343,-15.3880533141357));
#1323=VERTEX_POINT('',#1322);
#1324=EDGE_CURVE('E1659',#1314,#1323,#1321,.T.);
#1325=ORIENTED_EDGE('',*,*,#1324,.T.);
#1326=CARTESIAN_POINT('',(0.,10.6482749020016,-15.7357631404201));
#1327=VERTEX_POINT('',#1326);
#1328=EDGE_CURVE('E2175',#1323,#1327,#1201,.T.);
#1329=ORIENTED_EDGE('',*,*,#1328,.T.);
#1330=CARTESIAN_POINT('',(0.,14.0637117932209,-9.39740445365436));
#1331=DIRECTION('',(1.,0.,0.));
#1332=DIRECTION('',(0.,0.,-1.));
#1333=AXIS2_PLACEMENT_3D('',#1330,#1331,#1332);
#1334=CIRCLE('',#1333,7.2);
#1335=CARTESIAN_POINT('',(0.,8.76516516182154,-14.2723817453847));
#1336=VERTEX_POINT('',#1335);
#1337=EDGE_CURVE('E1884',#1336,#1327,#1334,.T.);
#1338=ORIENTED_EDGE('',*,*,#1337,.F.);
#1339=CARTESIAN_POINT('',(0.,0.,0.));
#1340=DIRECTION('',(-1.,0.,0.));
#1341=DIRECTION('',(0.,-0.866025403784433,-0.50000000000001));
#1342=AXIS2_PLACEMENT_3D('',#1339,#1340,#1341);
#1343=CIRCLE('',#1342,16.749);
#1344=CARTESIAN_POINT('',(0.,7.977662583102,-14.7270465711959));
#1345=VERTEX_POINT('',#1344);
#1346=EDGE_CURVE('E1634',#1336,#1345,#1343,.T.);
#1347=ORIENTED_EDGE('',*,*,#1346,.T.);
#1348=CARTESIAN_POINT('',(0.,1.10653508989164,-16.8782339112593));
#1349=DIRECTION('',(-1.,0.,0.));
#1350=DIRECTION('',(0.,-0.866025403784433,-0.50000000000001));
#1351=AXIS2_PLACEMENT_3D('',#1348,#1349,#1350);
#1352=CIRCLE('',#1351,7.2);
#1353=CARTESIAN_POINT('',(0.,8.30343317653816,-17.0895581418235));
#1354=VERTEX_POINT('',#1353);
#1355=EDGE_CURVE('E1637',#1345,#1354,#1352,.T.);
#1356=ORIENTED_EDGE('',*,*,#1355,.T.);
#1357=CARTESIAN_POINT('',(0.,7.75401708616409,-17.3457550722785));
#1358=VERTEX_POINT('',#1357);
#1359=EDGE_CURVE('E2172',#1354,#1358,#1201,.T.);
#1360=ORIENTED_EDGE('',*,*,#1359,.T.);
#1361=CARTESIAN_POINT('',(0.,12.218210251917,-11.696774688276));
#1362=DIRECTION('',(1.,0.,0.));
#1363=DIRECTION('',(0.,0.,-1.));
#1364=AXIS2_PLACEMENT_3D('',#1361,#1362,#1363);
#1365=CIRCLE('',#1364,7.2);
#1366=CARTESIAN_POINT('',(0.,6.15362952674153,-15.5776071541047));
#1367=VERTEX_POINT('',#1366);
#1368=EDGE_CURVE('E1881',#1367,#1358,#1365,.T.);
#1369=ORIENTED_EDGE('',*,*,#1368,.F.);
#1370=CARTESIAN_POINT('',(0.,0.,0.));
#1371=DIRECTION('',(-1.,0.,0.));
#1372=DIRECTION('',(0.,-0.939692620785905,-0.342020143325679));
#1373=AXIS2_PLACEMENT_3D('',#1370,#1371,#1372);
#1374=CIRCLE('',#1373,16.749);
#1375=CARTESIAN_POINT('',(0.,5.29913916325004,-15.8886162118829));
#1376=VERTEX_POINT('',#1375);
#1377=EDGE_CURVE('E1612',#1367,#1376,#1374,.T.);
#1378=ORIENTED_EDGE('',*,*,#1377,.T.);
#1379=CARTESIAN_POINT('',(0.,-1.84115022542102,-16.8139634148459));
#1380=DIRECTION('',(-1.,0.,0.));
#1381=DIRECTION('',(0.,-0.939692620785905,-0.342020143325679));
#1382=AXIS2_PLACEMENT_3D('',#1379,#1380,#1381);
#1383=CIRCLE('',#1382,7.2);
#1384=CARTESIAN_POINT('',(0.,5.20971474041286,-18.2718053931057));
#1385=VERTEX_POINT('',#1384);
#1386=EDGE_CURVE('E1615',#1376,#1385,#1383,.T.);
#1387=ORIENTED_EDGE('',*,*,#1386,.T.);
#1388=CARTESIAN_POINT('',(0.,4.62415738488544,-18.4287050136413));
#1389=VERTEX_POINT('',#1388);
#1390=EDGE_CURVE('E2169',#1385,#1389,#1201,.T.);
#1391=ORIENTED_EDGE('',*,*,#1390,.T.);
#1392=CARTESIAN_POINT('',(0.,10.0014645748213,-13.640744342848));
#1393=DIRECTION('',(1.,0.,0.));
#1394=DIRECTION('',(0.,0.,-1.));
#1395=AXIS2_PLACEMENT_3D('',#1392,#1393,#1394);
#1396=CIRCLE('',#1395,7.2);
#1397=CARTESIAN_POINT('',(0.,3.35511897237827,-16.4095148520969));
#1398=VERTEX_POINT('',#1397);
#1399=EDGE_CURVE('E1878',#1398,#1389,#1396,.T.);
#1400=ORIENTED_EDGE('',*,*,#1399,.F.);
#1401=CARTESIAN_POINT('',(0.,0.,0.));
#1402=DIRECTION('',(-1.,0.,0.));
#1403=DIRECTION('',(0.,-0.984807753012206,-0.17364817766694));
#1404=AXIS2_PLACEMENT_3D('',#1401,#1402,#1403);
#1405=CIRCLE('',#1404,16.749);
#1406=CARTESIAN_POINT('',(0.,2.45960408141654,-16.5674182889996));
#1407=VERTEX_POINT('',#1406);
#1408=EDGE_CURVE('E1590',#1398,#1407,#1405,.T.);
#1409=ORIENTED_EDGE('',*,*,#1408,.T.);
#1410=CARTESIAN_POINT('',(0.,-4.73289312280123,-16.2388091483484));
#1411=DIRECTION('',(-1.,0.,0.));
#1412=DIRECTION('',(0.,-0.984807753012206,-0.17364817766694));
#1413=AXIS2_PLACEMENT_3D('',#1410,#1411,#1412);
#1414=CIRCLE('',#1413,7.2);
#1415=CARTESIAN_POINT('',(0.,1.95770175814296,-18.898873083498));
#1416=VERTEX_POINT('',#1415);
#1417=EDGE_CURVE('E1593',#1407,#1416,#1414,.T.);
#1418=ORIENTED_EDGE('',*,*,#1417,.T.);
#1419=CARTESIAN_POINT('',(0.,1.3537950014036,-18.9517080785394));
#1420=VERTEX_POINT('',#1419);
#1421=EDGE_CURVE('E2166',#1416,#1420,#1201,.T.);
#1422=ORIENTED_EDGE('',*,*,#1421,.T.);
#1423=CARTESIAN_POINT('',(0.,7.48082945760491,-15.1702468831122));
#1424=DIRECTION('',(1.,0.,0.));
#1425=DIRECTION('',(0.,0.,-1.));
#1426=AXIS2_PLACEMENT_3D('',#1423,#1424,#1425);
#1427=CIRCLE('',#1426,7.2);
#1428=CARTESIAN_POINT('',(0.,0.454664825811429,-16.7428277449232));
#1429=VERTEX_POINT('',#1428);
#1430=EDGE_CURVE('E1875',#1429,#1420,#1427,.T.);
#1431=ORIENTED_EDGE('',*,*,#1430,.F.);
#1432=CARTESIAN_POINT('',(0.,0.,0.));
#1433=DIRECTION('',(-1.,0.,0.));
#1434=DIRECTION('',(0.,-1.,0.));
#1435=AXIS2_PLACEMENT_3D('',#1432,#1433,#1434);
#1436=CIRCLE('',#1435,16.749);
#1437=CARTESIAN_POINT('',(0.,-0.454664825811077,-16.7428277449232));
#1438=VERTEX_POINT('',#1437);
#1439=EDGE_CURVE('E1568',#1429,#1438,#1436,.T.);
#1440=ORIENTED_EDGE('',*,*,#1439,.T.);
#1441=CARTESIAN_POINT('',(0.,-7.48082945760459,-15.1702468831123));
#1442=DIRECTION('',(-1.,0.,0.));
#1443=DIRECTION('',(0.,-1.,0.));
#1444=AXIS2_PLACEMENT_3D('',#1441,#1442,#1443);
#1445=CIRCLE('',#1444,7.2);
#1446=CARTESIAN_POINT('',(0.,-1.3537950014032,-18.9517080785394));
#1447=VERTEX_POINT('',#1446);
#1448=EDGE_CURVE('E1571',#1438,#1447,#1445,.T.);
#1449=ORIENTED_EDGE('',*,*,#1448,.T.);
#1450=CARTESIAN_POINT('',(0.,-1.95770175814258,-18.898873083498));
#1451=VERTEX_POINT('',#1450);
#1452=EDGE_CURVE('E2163',#1447,#1451,#1201,.T.);
#1453=ORIENTED_EDGE('',*,*,#1452,.T.);
#1454=CARTESIAN_POINT('',(0.,4.73289312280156,-16.2388091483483));
#1455=DIRECTION('',(1.,0.,0.));
#1456=DIRECTION('',(0.,0.,-1.));
#1457=AXIS2_PLACEMENT_3D('',#1454,#1455,#1456);
#1458=CIRCLE('',#1457,7.2);
#1459=CARTESIAN_POINT('',(0.,-2.4596040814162,-16.5674182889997));
#1460=VERTEX_POINT('',#1459);
#1461=EDGE_CURVE('E1872',#1460,#1451,#1458,.T.);
#1462=ORIENTED_EDGE('',*,*,#1461,.F.);
#1463=CARTESIAN_POINT('',(0.,0.,0.));
#1464=DIRECTION('',(-1.,0.,0.));
#1465=DIRECTION('',(0.,-0.98480775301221,0.173648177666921));
#1466=AXIS2_PLACEMENT_3D('',#1463,#1464,#1465);
#1467=CIRCLE('',#1466,16.749);
#1468=CARTESIAN_POINT('',(0.,-3.35511897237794,-16.4095148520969));
#1469=VERTEX_POINT('',#1468);
#1470=EDGE_CURVE('E1546',#1460,#1469,#1467,.T.);
#1471=ORIENTED_EDGE('',*,*,#1470,.T.);
#1472=CARTESIAN_POINT('',(0.,-10.001464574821,-13.6407443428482));
#1473=DIRECTION('',(-1.,0.,0.));
#1474=DIRECTION('',(0.,-0.98480775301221,0.173648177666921));
#1475=AXIS2_PLACEMENT_3D('',#1472,#1473,#1474);
#1476=CIRCLE('',#1475,7.2);
#1477=CARTESIAN_POINT('',(0.,-4.62415738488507,-18.4287050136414));
#1478=VERTEX_POINT('',#1477);
#1479=EDGE_CURVE('E1549',#1469,#1478,#1476,.T.);
#1480=ORIENTED_EDGE('',*,*,#1479,.T.);
#1481=CARTESIAN_POINT('',(0.,-5.20971474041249,-18.2718053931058));
#1482=VERTEX_POINT('',#1481);
#1483=EDGE_CURVE('E2160',#1478,#1482,#1201,.T.);
#1484=ORIENTED_EDGE('',*,*,#1483,.T.);
#1485=CARTESIAN_POINT('',(0.,1.84115022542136,-16.8139634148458));
#1486=DIRECTION('',(1.,0.,0.));
#1487=DIRECTION('',(0.,0.,-1.));
#1488=AXIS2_PLACEMENT_3D('',#1485,#1486,#1487);
#1489=CIRCLE('',#1488,7.2);
#1490=CARTESIAN_POINT('',(0.,-5.29913916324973,-15.8886162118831));
#1491=VERTEX_POINT('',#1490);
#1492=EDGE_CURVE('E1869',#1491,#1482,#1489,.T.);
#1493=ORIENTED_EDGE('',*,*,#1492,.F.);
#1494=CARTESIAN_POINT('',(0.,0.,0.));
#1495=DIRECTION('',(-1.,0.,0.));
#1496=DIRECTION('',(0.,-0.939692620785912,0.34202014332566));
#1497=AXIS2_PLACEMENT_3D('',#1494,#1495,#1496);
#1498=CIRCLE('',#1497,16.749);
#1499=CARTESIAN_POINT('',(0.,-6.15362952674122,-15.5776071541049));
#1500=VERTEX_POINT('',#1499);
#1501=EDGE_CURVE('E1524',#1491,#1500,#1498,.T.);
#1502=ORIENTED_EDGE('',*,*,#1501,.T.);
#1503=CARTESIAN_POINT('',(0.,-12.2182102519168,-11.6967746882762));
#1504=DIRECTION('',(-1.,0.,0.));
#1505=DIRECTION('',(0.,-0.939692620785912,0.34202014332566));
#1506=AXIS2_PLACEMENT_3D('',#1503,#1504,#1505);
#1507=CIRCLE('',#1506,7.2);
#1508=CARTESIAN_POINT('',(0.,-7.75401708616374,-17.3457550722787));
#1509=VERTEX_POINT('',#1508);
#1510=EDGE_CURVE('E1527',#1500,#1509,#1507,.T.);
#1511=ORIENTED_EDGE('',*,*,#1510,.T.);
#1512=CARTESIAN_POINT('',(0.,-8.3034331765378,-17.0895581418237));
#1513=VERTEX_POINT('',#1512);
#1514=EDGE_CURVE('E2157',#1509,#1513,#1201,.T.);
#1515=ORIENTED_EDGE('',*,*,#1514,.T.);
#1516=CARTESIAN_POINT('',(0.,-1.10653508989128,-16.8782339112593));
#1517=DIRECTION('',(1.,0.,0.));
#1518=DIRECTION('',(0.,0.,-1.));
#1519=AXIS2_PLACEMENT_3D('',#1516,#1517,#1518);
#1520=CIRCLE('',#1519,7.2);
#1521=CARTESIAN_POINT('',(0.,-7.97766258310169,-14.7270465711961));
#1522=VERTEX_POINT('',#1521);
#1523=EDGE_CURVE('E1866',#1522,#1513,#1520,.T.);
#1524=ORIENTED_EDGE('',*,*,#1523,.F.);
#1525=CARTESIAN_POINT('',(0.,0.,0.));
#1526=DIRECTION('',(-1.,0.,0.));
#1527=DIRECTION('',(0.,-0.866025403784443,0.499999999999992));
#1528=AXIS2_PLACEMENT_3D('',#1525,#1526,#1527);
#1529=CIRCLE('',#1528,16.749);
#1530=CARTESIAN_POINT('',(0.,-8.76516516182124,-14.2723817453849));
#1531=VERTEX_POINT('',#1530);
#1532=EDGE_CURVE('E1502',#1522,#1531,#1529,.T.);
#1533=ORIENTED_EDGE('',*,*,#1532,.T.);
#1534=CARTESIAN_POINT('',(0.,-14.0637117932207,-9.39740445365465));
#1535=DIRECTION('',(-1.,0.,0.));
#1536=DIRECTION('',(0.,-0.866025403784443,0.499999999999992));
#1537=AXIS2_PLACEMENT_3D('',#1534,#1535,#1536);
#1538=CIRCLE('',#1537,7.2);
#1539=CARTESIAN_POINT('',(0.,-10.6482749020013,-15.7357631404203));
#1540=VERTEX_POINT('',#1539);
#1541=EDGE_CURVE('E1505',#1531,#1540,#1538,.T.);
#1542=ORIENTED_EDGE('',*,*,#1541,.T.);
#1543=CARTESIAN_POINT('',(0.,-11.144855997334,-15.3880533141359));
#1544=VERTEX_POINT('',#1543);
#1545=EDGE_CURVE('E2154',#1540,#1544,#1201,.T.);
#1546=ORIENTED_EDGE('',*,*,#1545,.T.);
#1547=CARTESIAN_POINT('',(0.,-4.02059889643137,-16.4296678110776));
#1548=DIRECTION('',(1.,0.,0.));
#1549=DIRECTION('',(0.,0.,-1.));
#1550=AXIS2_PLACEMENT_3D('',#1547,#1548,#1549);
#1551=CIRCLE('',#1550,7.2);
#1552=CARTESIAN_POINT('',(0.,-10.4137887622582,-13.1180030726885));
#1553=VERTEX_POINT('',#1552);
#1554=EDGE_CURVE('E1863',#1553,#1544,#1551,.T.);
#1555=ORIENTED_EDGE('',*,*,#1554,.F.);
#1556=CARTESIAN_POINT('',(0.,0.,0.));
#1557=DIRECTION('',(-1.,0.,0.));
#1558=DIRECTION('',(0.,-0.766044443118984,0.642787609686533));
#1559=AXIS2_PLACEMENT_3D('',#1556,#1557,#1558);
#1560=CIRCLE('',#1559,16.749);
#1561=CARTESIAN_POINT('',(0.,-11.1103756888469,-12.533497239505));
#1562=VERTEX_POINT('',#1561);
#1563=EDGE_CURVE('E1480',#1553,#1562,#1560,.T.);
#1564=ORIENTED_EDGE('',*,*,#1563,.T.);
#1565=CARTESIAN_POINT('',(0.,-15.4818945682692,-6.81249884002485));
#1566=DIRECTION('',(-1.,0.,0.));
#1567=DIRECTION('',(0.,-0.766044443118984,0.642787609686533));
#1568=AXIS2_PLACEMENT_3D('',#1565,#1566,#1567);
#1569=CIRCLE('',#1568,7.2);
#1570=CARTESIAN_POINT('',(0.,-13.2189902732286,-13.6476480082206));
#1571=VERTEX_POINT('',#1570);
#1572=EDGE_CURVE('E1483',#1562,#1571,#1569,.T.);
#1573=ORIENTED_EDGE('',*,*,#1572,.T.);
#1574=CARTESIAN_POINT('',(0.,-13.6476480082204,-13.2189902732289));
#1575=VERTEX_POINT('',#1574);
#1576=EDGE_CURVE('E2151',#1571,#1575,#1201,.T.);
#1577=ORIENTED_EDGE('',*,*,#1576,.T.);
#1578=CARTESIAN_POINT('',(0.,-6.81249884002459,-15.4818945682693));
#1579=DIRECTION('',(1.,0.,0.));
#1580=DIRECTION('',(0.,0.,-1.));
#1581=AXIS2_PLACEMENT_3D('',#1578,#1579,#1580);
#1582=CIRCLE('',#1581,7.2);
#1583=CARTESIAN_POINT('',(0.,-12.5334972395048,-11.1103756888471));
#1584=VERTEX_POINT('',#1583);
#1585=EDGE_CURVE('E1860',#1584,#1575,#1582,.T.);
#1586=ORIENTED_EDGE('',*,*,#1585,.F.);
#1587=CARTESIAN_POINT('',(0.,0.,0.));
#1588=DIRECTION('',(-1.,0.,0.));
#1589=DIRECTION('',(0.,-0.642787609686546,0.766044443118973));
#1590=AXIS2_PLACEMENT_3D('',#1587,#1588,#1589);
#1591=CIRCLE('',#1590,16.749);
#1592=CARTESIAN_POINT('',(0.,-13.1180030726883,-10.4137887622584));
#1593=VERTEX_POINT('',#1592);
#1594=EDGE_CURVE('E1458',#1584,#1593,#1591,.T.);
#1595=ORIENTED_EDGE('',*,*,#1594,.T.);
#1596=CARTESIAN_POINT('',(0.,-16.4296678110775,-4.02059889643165));
#1597=DIRECTION('',(-1.,0.,0.));
#1598=DIRECTION('',(0.,-0.642787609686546,0.766044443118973));
#1599=AXIS2_PLACEMENT_3D('',#1596,#1597,#1598);
#1600=CIRCLE('',#1599,7.2);
#1601=CARTESIAN_POINT('',(0.,-15.3880533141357,-11.1448559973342));
#1602=VERTEX_POINT('',#1601);
#1603=EDGE_CURVE('E1461',#1593,#1602,#1600,.T.);
#1604=ORIENTED_EDGE('',*,*,#1603,.T.);
#1605=CARTESIAN_POINT('',(0.,-15.7357631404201,-10.6482749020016));
#1606=VERTEX_POINT('',#1605);
#1607=EDGE_CURVE('E2148',#1602,#1606,#1201,.T.);
#1608=ORIENTED_EDGE('',*,*,#1607,.T.);
#1609=CARTESIAN_POINT('',(0.,-9.39740445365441,-14.0637117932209));
#1610=DIRECTION('',(1.,0.,0.));
#1611=DIRECTION('',(0.,0.,-1.));
#1612=AXIS2_PLACEMENT_3D('',#1609,#1610,#1611);
#1613=CIRCLE('',#1612,7.2);
#1614=CARTESIAN_POINT('',(0.,-14.2723817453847,-8.76516516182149));
#1615=VERTEX_POINT('',#1614);
#1616=EDGE_CURVE('E1857',#1615,#1606,#1613,.T.);
#1617=ORIENTED_EDGE('',*,*,#1616,.F.);
#1618=CARTESIAN_POINT('',(0.,0.,0.));
#1619=DIRECTION('',(-1.,0.,0.));
#1620=DIRECTION('',(0.,-0.500000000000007,0.866025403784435));
#1621=AXIS2_PLACEMENT_3D('',#1618,#1619,#1620);
#1622=CIRCLE('',#1621,16.749);
#1623=CARTESIAN_POINT('',(0.,-14.727046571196,-7.97766258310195));
#1624=VERTEX_POINT('',#1623);
#1625=EDGE_CURVE('E1436',#1615,#1624,#1622,.T.);
#1626=ORIENTED_EDGE('',*,*,#1625,.T.);
#1627=CARTESIAN_POINT('',(0.,-16.8782339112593,-1.10653508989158));
#1628=DIRECTION('',(-1.,0.,0.));
#1629=DIRECTION('',(0.,-0.500000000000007,0.866025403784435));
#1630=AXIS2_PLACEMENT_3D('',#1627,#1628,#1629);
#1631=CIRCLE('',#1630,7.2);
#1632=CARTESIAN_POINT('',(0.,-17.0895581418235,-8.3034331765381));
#1633=VERTEX_POINT('',#1632);
#1634=EDGE_CURVE('E1439',#1624,#1633,#1631,.T.);
#1635=ORIENTED_EDGE('',*,*,#1634,.T.);
#1636=CARTESIAN_POINT('',(0.,-17.3457550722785,-7.75401708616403));
#1637=VERTEX_POINT('',#1636);
#1638=EDGE_CURVE('E2145',#1633,#1637,#1201,.T.);
#1639=ORIENTED_EDGE('',*,*,#1638,.T.);
#1640=CARTESIAN_POINT('',(0.,-11.696774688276,-12.2182102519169));
#1641=DIRECTION('',(1.,0.,0.));
#1642=DIRECTION('',(0.,0.,-1.));
#1643=AXIS2_PLACEMENT_3D('',#1640,#1641,#1642);
#1644=CIRCLE('',#1643,7.2);
#1645=CARTESIAN_POINT('',(0.,-15.5776071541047,-6.15362952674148));
#1646=VERTEX_POINT('',#1645);
#1647=EDGE_CURVE('E1854',#1646,#1637,#1644,.T.);
#1648=ORIENTED_EDGE('',*,*,#1647,.F.);
#1649=CARTESIAN_POINT('',(0.,0.,0.));
#1650=DIRECTION('',(-1.,0.,0.));
#1651=DIRECTION('',(0.,-0.342020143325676,0.939692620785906));
#1652=AXIS2_PLACEMENT_3D('',#1649,#1650,#1651);
#1653=CIRCLE('',#1652,16.749);
#1654=CARTESIAN_POINT('',(0.,-15.888616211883,-5.29913916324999));
#1655=VERTEX_POINT('',#1654);
#1656=EDGE_CURVE('E1414',#1646,#1655,#1653,.T.);
#1657=ORIENTED_EDGE('',*,*,#1656,.T.);
#1658=CARTESIAN_POINT('',(0.,-16.8139634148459,1.84115022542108));
#1659=DIRECTION('',(-1.,0.,0.));
#1660=DIRECTION('',(0.,-0.342020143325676,0.939692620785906));
#1661=AXIS2_PLACEMENT_3D('',#1658,#1659,#1660);
#1662=CIRCLE('',#1661,7.2);
#1663=CARTESIAN_POINT('',(0.,-18.2718053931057,-5.20971474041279));
#1664=VERTEX_POINT('',#1663);
#1665=EDGE_CURVE('E1417',#1655,#1664,#1662,.T.);
#1666=ORIENTED_EDGE('',*,*,#1665,.T.);
#1667=CARTESIAN_POINT('',(0.,-18.4287050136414,-4.62415738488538));
#1668=VERTEX_POINT('',#1667);
#1669=EDGE_CURVE('E2142',#1664,#1668,#1201,.T.);
#1670=ORIENTED_EDGE('',*,*,#1669,.T.);
#1671=CARTESIAN_POINT('',(0.,-13.640744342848,-10.0014645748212));
#1672=DIRECTION('',(1.,0.,0.));
#1673=DIRECTION('',(0.,0.,-1.));
#1674=AXIS2_PLACEMENT_3D('',#1671,#1672,#1673);
#1675=CIRCLE('',#1674,7.2);
#1676=CARTESIAN_POINT('',(0.,-16.4095148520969,-3.35511897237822));
#1677=VERTEX_POINT('',#1676);
#1678=EDGE_CURVE('E1851',#1677,#1668,#1675,.T.);
#1679=ORIENTED_EDGE('',*,*,#1678,.F.);
#1680=CARTESIAN_POINT('',(0.,0.,0.));
#1681=DIRECTION('',(-1.,0.,0.));
#1682=DIRECTION('',(0.,-0.173648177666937,0.984807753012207));
#1683=AXIS2_PLACEMENT_3D('',#1680,#1681,#1682);
#1684=CIRCLE('',#1683,16.749);
#1685=CARTESIAN_POINT('',(0.,-16.5674182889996,-2.45960408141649));
#1686=VERTEX_POINT('',#1685);
#1687=EDGE_CURVE('E1392',#1677,#1686,#1684,.T.);
#1688=ORIENTED_EDGE('',*,*,#1687,.T.);
#1689=CARTESIAN_POINT('',(0.,-16.2388091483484,4.73289312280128));
#1690=DIRECTION('',(-1.,0.,0.));
#1691=DIRECTION('',(0.,-0.173648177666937,0.984807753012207));
#1692=AXIS2_PLACEMENT_3D('',#1689,#1690,#1691);
#1693=CIRCLE('',#1692,7.2);
#1694=CARTESIAN_POINT('',(0.,-18.898873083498,-1.95770175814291));
#1695=VERTEX_POINT('',#1694);
#1696=EDGE_CURVE('E1395',#1686,#1695,#1693,.T.);
#1697=ORIENTED_EDGE('',*,*,#1696,.T.);
#1698=CARTESIAN_POINT('',(0.,-18.9517080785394,-1.35379500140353));
#1699=VERTEX_POINT('',#1698);
#1700=EDGE_CURVE('E2139',#1695,#1699,#1201,.T.);
#1701=ORIENTED_EDGE('',*,*,#1700,.T.);
#1702=CARTESIAN_POINT('',(0.,-15.1702468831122,-7.48082945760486));
#1703=DIRECTION('',(1.,0.,0.));
#1704=DIRECTION('',(0.,0.,-1.));
#1705=AXIS2_PLACEMENT_3D('',#1702,#1703,#1704);
#1706=CIRCLE('',#1705,7.2);
#1707=CARTESIAN_POINT('',(0.,-16.7428277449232,-0.454664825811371));
#1708=VERTEX_POINT('',#1707);
#1709=EDGE_CURVE('E1848',#1708,#1699,#1706,.T.);
#1710=ORIENTED_EDGE('',*,*,#1709,.F.);
#1711=CARTESIAN_POINT('',(0.,0.,0.));
#1712=DIRECTION('',(-1.,0.,0.));
#1713=DIRECTION('',(0.,0.,1.));
#1714=AXIS2_PLACEMENT_3D('',#1711,#1712,#1713);
#1715=CIRCLE('',#1714,16.749);
#1716=CARTESIAN_POINT('',(0.,-16.7428277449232,0.454664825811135));
#1717=VERTEX_POINT('',#1716);
#1718=EDGE_CURVE('E1370',#1708,#1717,#1715,.T.);
#1719=ORIENTED_EDGE('',*,*,#1718,.T.);
#1720=CARTESIAN_POINT('',(0.,-15.1702468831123,7.48082945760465));
#1721=DIRECTION('',(-1.,0.,0.));
#1722=DIRECTION('',(0.,0.,1.));
#1723=AXIS2_PLACEMENT_3D('',#1720,#1721,#1722);
#1724=CIRCLE('',#1723,7.2);
#1725=CARTESIAN_POINT('',(0.,-18.9517080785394,1.35379500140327));
#1726=VERTEX_POINT('',#1725);
#1727=EDGE_CURVE('E1373',#1717,#1726,#1724,.T.);
#1728=ORIENTED_EDGE('',*,*,#1727,.T.);
#1729=CARTESIAN_POINT('',(0.,-18.898873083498,1.95770175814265));
#1730=VERTEX_POINT('',#1729);
#1731=EDGE_CURVE('E2136',#1726,#1730,#1201,.T.);
#1732=ORIENTED_EDGE('',*,*,#1731,.T.);
#1733=CARTESIAN_POINT('',(0.,-16.2388091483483,-4.7328931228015));
#1734=DIRECTION('',(1.,0.,0.));
#1735=DIRECTION('',(0.,0.,-1.));
#1736=AXIS2_PLACEMENT_3D('',#1733,#1734,#1735);
#1737=CIRCLE('',#1736,7.2);
#1738=CARTESIAN_POINT('',(0.,-16.5674182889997,2.45960408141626));
#1739=VERTEX_POINT('',#1738);
#1740=EDGE_CURVE('E1845',#1739,#1730,#1737,.T.);
#1741=ORIENTED_EDGE('',*,*,#1740,.F.);
#1742=CARTESIAN_POINT('',(0.,0.,0.));
#1743=DIRECTION('',(-1.,0.,0.));
#1744=DIRECTION('',(0.,0.173648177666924,0.984807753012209));
#1745=AXIS2_PLACEMENT_3D('',#1742,#1743,#1744);
#1746=CIRCLE('',#1745,16.749);
#1747=CARTESIAN_POINT('',(0.,-16.4095148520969,3.355118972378));
#1748=VERTEX_POINT('',#1747);
#1749=EDGE_CURVE('E1348',#1739,#1748,#1746,.T.);
#1750=ORIENTED_EDGE('',*,*,#1749,.T.);
#1751=CARTESIAN_POINT('',(0.,-13.6407443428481,10.0014645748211));
#1752=DIRECTION('',(-1.,0.,0.));
#1753=DIRECTION('',(0.,0.173648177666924,0.984807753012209));
#1754=AXIS2_PLACEMENT_3D('',#1751,#1752,#1753);
#1755=CIRCLE('',#1754,7.2);
#1756=CARTESIAN_POINT('',(0.,-18.4287050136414,4.62415738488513));
#1757=VERTEX_POINT('',#1756);
#1758=EDGE_CURVE('E1351',#1748,#1757,#1755,.T.);
#1759=ORIENTED_EDGE('',*,*,#1758,.T.);
#1760=CARTESIAN_POINT('',(0.,-18.2718053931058,5.20971474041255));
#1761=VERTEX_POINT('',#1760);
#1762=EDGE_CURVE('E2133',#1757,#1761,#1201,.T.);
#1763=ORIENTED_EDGE('',*,*,#1762,.T.);
#1764=CARTESIAN_POINT('',(0.,-16.8139634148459,-1.84115022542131));
#1765=DIRECTION('',(1.,0.,0.));
#1766=DIRECTION('',(0.,0.,-1.));
#1767=AXIS2_PLACEMENT_3D('',#1764,#1765,#1766);
#1768=CIRCLE('',#1767,7.2);
#1769=CARTESIAN_POINT('',(0.,-15.888616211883,5.29913916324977));
#1770=VERTEX_POINT('',#1769);
#1771=EDGE_CURVE('E1842',#1770,#1761,#1768,.T.);
#1772=ORIENTED_EDGE('',*,*,#1771,.F.);
#1773=CARTESIAN_POINT('',(0.,0.,0.));
#1774=DIRECTION('',(-1.,0.,0.));
#1775=DIRECTION('',(0.,0.342020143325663,0.939692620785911));
#1776=AXIS2_PLACEMENT_3D('',#1773,#1774,#1775);
#1777=CIRCLE('',#1776,16.749);
#1778=CARTESIAN_POINT('',(0.,-15.5776071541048,6.15362952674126));
#1779=VERTEX_POINT('',#1778);
#1780=EDGE_CURVE('E1326',#1770,#1779,#1777,.T.);
#1781=ORIENTED_EDGE('',*,*,#1780,.T.);
#1782=CARTESIAN_POINT('',(0.,-11.6967746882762,12.2182102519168));
#1783=DIRECTION('',(-1.,0.,0.));
#1784=DIRECTION('',(0.,0.342020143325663,0.939692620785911));
#1785=AXIS2_PLACEMENT_3D('',#1782,#1783,#1784);
#1786=CIRCLE('',#1785,7.2);
#1787=CARTESIAN_POINT('',(0.,-17.3457550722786,7.75401708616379));
#1788=VERTEX_POINT('',#1787);
#1789=EDGE_CURVE('E1329',#1779,#1788,#1786,.T.);
#1790=ORIENTED_EDGE('',*,*,#1789,.T.);
#1791=CARTESIAN_POINT('',(0.,-17.0895581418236,8.30343317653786));
#1792=VERTEX_POINT('',#1791);
#1793=EDGE_CURVE('E2130',#1788,#1792,#1201,.T.);
#1794=ORIENTED_EDGE('',*,*,#1793,.T.);
#1795=CARTESIAN_POINT('',(0.,-16.8782339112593,1.10653508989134));
#1796=DIRECTION('',(1.,0.,0.));
#1797=DIRECTION('',(0.,0.,-1.));
#1798=AXIS2_PLACEMENT_3D('',#1795,#1796,#1797);
#1799=CIRCLE('',#1798,7.2);
#1800=CARTESIAN_POINT('',(0.,-14.7270465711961,7.97766258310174));
#1801=VERTEX_POINT('',#1800);
#1802=EDGE_CURVE('E1839',#1801,#1792,#1799,.T.);
#1803=ORIENTED_EDGE('',*,*,#1802,.F.);
#1804=CARTESIAN_POINT('',(0.,0.,0.));
#1805=DIRECTION('',(-1.,0.,0.));
#1806=DIRECTION('',(0.,0.499999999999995,0.866025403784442));
#1807=AXIS2_PLACEMENT_3D('',#1804,#1805,#1806);
#1808=CIRCLE('',#1807,16.749);
#1809=CARTESIAN_POINT('',(0.,-14.2723817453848,8.76516516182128));
#1810=VERTEX_POINT('',#1809);
#1811=EDGE_CURVE('E1304',#1801,#1810,#1808,.T.);
#1812=ORIENTED_EDGE('',*,*,#1811,.T.);
#1813=CARTESIAN_POINT('',(0.,-9.3974044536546,14.0637117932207));
#1814=DIRECTION('',(-1.,0.,0.));
#1815=DIRECTION('',(0.,0.499999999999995,0.866025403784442));
#1816=AXIS2_PLACEMENT_3D('',#1813,#1814,#1815);
#1817=CIRCLE('',#1816,7.2);
#1818=CARTESIAN_POINT('',(0.,-15.7357631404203,10.6482749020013));
#1819=VERTEX_POINT('',#1818);
#1820=EDGE_CURVE('E1307',#1810,#1819,#1817,.T.);
#1821=ORIENTED_EDGE('',*,*,#1820,.T.);
#1822=CARTESIAN_POINT('',(0.,-15.3880533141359,11.144855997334));
#1823=VERTEX_POINT('',#1822);
#1824=EDGE_CURVE('E2127',#1819,#1823,#1201,.T.);
#1825=ORIENTED_EDGE('',*,*,#1824,.T.);
#1826=CARTESIAN_POINT('',(0.,-16.4296678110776,4.02059889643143));
#1827=DIRECTION('',(1.,0.,0.));
#1828=DIRECTION('',(0.,0.,-1.));
#1829=AXIS2_PLACEMENT_3D('',#1826,#1827,#1828);
#1830=CIRCLE('',#1829,7.2);
#1831=CARTESIAN_POINT('',(0.,-13.1180030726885,10.4137887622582));
#1832=VERTEX_POINT('',#1831);
#1833=EDGE_CURVE('E1836',#1832,#1823,#1830,.T.);
#1834=ORIENTED_EDGE('',*,*,#1833,.F.);
#1835=CARTESIAN_POINT('',(0.,0.,0.));
#1836=DIRECTION('',(-1.,0.,0.));
#1837=DIRECTION('',(0.,0.642787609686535,0.766044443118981));
#1838=AXIS2_PLACEMENT_3D('',#1835,#1836,#1837);
#1839=CIRCLE('',#1838,16.749);
#1840=CARTESIAN_POINT('',(0.,-12.533497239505,11.110375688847));
#1841=VERTEX_POINT('',#1840);
#1842=EDGE_CURVE('E1282',#1832,#1841,#1839,.T.);
#1843=ORIENTED_EDGE('',*,*,#1842,.T.);
#1844=CARTESIAN_POINT('',(0.,-6.8124988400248,15.4818945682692));
#1845=DIRECTION('',(-1.,0.,0.));
#1846=DIRECTION('',(0.,0.642787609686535,0.766044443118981));
#1847=AXIS2_PLACEMENT_3D('',#1844,#1845,#1846);
#1848=CIRCLE('',#1847,7.2);
#1849=CARTESIAN_POINT('',(0.,-13.6476480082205,13.2189902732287));
#1850=VERTEX_POINT('',#1849);
#1851=EDGE_CURVE('E1285',#1841,#1850,#1848,.T.);
#1852=ORIENTED_EDGE('',*,*,#1851,.T.);
#1853=CARTESIAN_POINT('',(0.,-13.2189902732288,13.6476480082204));
#1854=VERTEX_POINT('',#1853);
#1855=EDGE_CURVE('E2124',#1850,#1854,#1201,.T.);
#1856=ORIENTED_EDGE('',*,*,#1855,.T.);
#1857=CARTESIAN_POINT('',(0.,-15.4818945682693,6.81249884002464));
#1858=DIRECTION('',(1.,0.,0.));
#1859=DIRECTION('',(0.,0.,-1.));
#1860=AXIS2_PLACEMENT_3D('',#1857,#1858,#1859);
#1861=CIRCLE('',#1860,7.2);
#1862=CARTESIAN_POINT('',(0.,-11.1103756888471,12.5334972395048));
#1863=VERTEX_POINT('',#1862);
#1864=EDGE_CURVE('E1833',#1863,#1854,#1861,.T.);
#1865=ORIENTED_EDGE('',*,*,#1864,.F.);
#1866=CARTESIAN_POINT('',(0.,0.,0.));
#1867=DIRECTION('',(-1.,0.,0.));
#1868=DIRECTION('',(0.,0.766044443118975,0.642787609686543));
#1869=AXIS2_PLACEMENT_3D('',#1866,#1867,#1868);
#1870=CIRCLE('',#1869,16.749);
#1871=CARTESIAN_POINT('',(0.,-10.4137887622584,13.1180030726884));
#1872=VERTEX_POINT('',#1871);
#1873=EDGE_CURVE('E1260',#1863,#1872,#1870,.T.);
#1874=ORIENTED_EDGE('',*,*,#1873,.T.);
#1875=CARTESIAN_POINT('',(0.,-4.02059889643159,16.4296678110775));
#1876=DIRECTION('',(-1.,0.,0.));
#1877=DIRECTION('',(0.,0.766044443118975,0.642787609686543));
#1878=AXIS2_PLACEMENT_3D('',#1875,#1876,#1877);
#1879=CIRCLE('',#1878,7.2);
#1880=CARTESIAN_POINT('',(0.,-11.1448559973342,15.3880533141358));
#1881=VERTEX_POINT('',#1880);
#1882=EDGE_CURVE('E1263',#1872,#1881,#1879,.T.);
#1883=ORIENTED_EDGE('',*,*,#1882,.T.);
#1884=CARTESIAN_POINT('',(0.,-10.6482749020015,15.7357631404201));
#1885=VERTEX_POINT('',#1884);
#1886=EDGE_CURVE('E2121',#1881,#1885,#1201,.T.);
#1887=ORIENTED_EDGE('',*,*,#1886,.T.);
#1888=CARTESIAN_POINT('',(0.,-14.0637117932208,9.39740445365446));
#1889=DIRECTION('',(1.,0.,0.));
#1890=DIRECTION('',(0.,0.,-1.));
#1891=AXIS2_PLACEMENT_3D('',#1888,#1889,#1890);
#1892=CIRCLE('',#1891,7.2);
#1893=CARTESIAN_POINT('',(0.,-8.76516516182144,14.2723817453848));
#1894=VERTEX_POINT('',#1893);
#1895=EDGE_CURVE('E1830',#1894,#1885,#1892,.T.);
#1896=ORIENTED_EDGE('',*,*,#1895,.F.);
#1897=CARTESIAN_POINT('',(0.,0.,0.));
#1898=DIRECTION('',(-1.,0.,0.));
#1899=DIRECTION('',(0.,0.866025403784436,0.500000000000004));
#1900=AXIS2_PLACEMENT_3D('',#1897,#1898,#1899);
#1901=CIRCLE('',#1900,16.749);
#1902=CARTESIAN_POINT('',(0.,-7.9776625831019,14.727046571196));
#1903=VERTEX_POINT('',#1902);
#1904=EDGE_CURVE('E1238',#1894,#1903,#1901,.T.);
#1905=ORIENTED_EDGE('',*,*,#1904,.T.);
#1906=CARTESIAN_POINT('',(0.,-1.10653508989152,16.8782339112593));
#1907=DIRECTION('',(-1.,0.,0.));
#1908=DIRECTION('',(0.,0.866025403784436,0.500000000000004));
#1909=AXIS2_PLACEMENT_3D('',#1906,#1907,#1908);
#1910=CIRCLE('',#1909,7.2);
#1911=CARTESIAN_POINT('',(0.,-8.30343317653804,17.0895581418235));
#1912=VERTEX_POINT('',#1911);
#1913=EDGE_CURVE('E1241',#1903,#1912,#1910,.T.);
#1914=ORIENTED_EDGE('',*,*,#1913,.T.);
#1915=CARTESIAN_POINT('',(0.,-7.75401708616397,17.3457550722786));
#1916=VERTEX_POINT('',#1915);
#1917=EDGE_CURVE('E2118',#1912,#1916,#1201,.T.);
#1918=ORIENTED_EDGE('',*,*,#1917,.T.);
#1919=CARTESIAN_POINT('',(0.,-12.2182102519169,11.6967746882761));
#1920=DIRECTION('',(1.,0.,0.));
#1921=DIRECTION('',(0.,0.,-1.));
#1922=AXIS2_PLACEMENT_3D('',#1919,#1920,#1921);
#1923=CIRCLE('',#1922,7.2);
#1924=CARTESIAN_POINT('',(0.,-6.15362952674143,15.5776071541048));
#1925=VERTEX_POINT('',#1924);
#1926=EDGE_CURVE('E1827',#1925,#1916,#1923,.T.);
#1927=ORIENTED_EDGE('',*,*,#1926,.F.);
#1928=CARTESIAN_POINT('',(0.,0.,0.));
#1929=DIRECTION('',(-1.,0.,0.));
#1930=DIRECTION('',(0.,0.939692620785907,0.342020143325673));
#1931=AXIS2_PLACEMENT_3D('',#1928,#1929,#1930);
#1932=CIRCLE('',#1931,16.749);
#1933=CARTESIAN_POINT('',(0.,-5.29913916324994,15.888616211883));
#1934=VERTEX_POINT('',#1933);
#1935=EDGE_CURVE('E1216',#1925,#1934,#1932,.T.);
#1936=ORIENTED_EDGE('',*,*,#1935,.T.);
#1937=CARTESIAN_POINT('',(0.,1.84115022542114,16.8139634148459));
#1938=DIRECTION('',(-1.,0.,0.));
#1939=DIRECTION('',(0.,0.939692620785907,0.342020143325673));
#1940=AXIS2_PLACEMENT_3D('',#1937,#1938,#1939);
#1941=CIRCLE('',#1940,7.2);
#1942=CARTESIAN_POINT('',(0.,-5.20971474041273,18.2718053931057));
#1943=VERTEX_POINT('',#1942);
#1944=EDGE_CURVE('E1219',#1934,#1943,#1941,.T.);
#1945=ORIENTED_EDGE('',*,*,#1944,.T.);
#1946=CARTESIAN_POINT('',(0.,-4.62415738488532,18.4287050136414));
#1947=VERTEX_POINT('',#1946);
#1948=EDGE_CURVE('E2115',#1943,#1947,#1201,.T.);
#1949=ORIENTED_EDGE('',*,*,#1948,.T.);
#1950=CARTESIAN_POINT('',(0.,-10.0014645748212,13.640744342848));
#1951=DIRECTION('',(1.,0.,0.));
#1952=DIRECTION('',(0.,0.,-1.));
#1953=AXIS2_PLACEMENT_3D('',#1950,#1951,#1952);
#1954=CIRCLE('',#1953,7.2);
#1955=CARTESIAN_POINT('',(0.,-3.35511897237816,16.4095148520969));
#1956=VERTEX_POINT('',#1955);
#1957=EDGE_CURVE('E1824',#1956,#1947,#1954,.T.);
#1958=ORIENTED_EDGE('',*,*,#1957,.F.);
#1959=CARTESIAN_POINT('',(0.,0.,0.));
#1960=DIRECTION('',(-1.,0.,0.));
#1961=DIRECTION('',(0.,0.984807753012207,0.173648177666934));
#1962=AXIS2_PLACEMENT_3D('',#1959,#1960,#1961);
#1963=CIRCLE('',#1962,16.749);
#1964=CARTESIAN_POINT('',(0.,-2.45960408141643,16.5674182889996));
#1965=VERTEX_POINT('',#1964);
#1966=EDGE_CURVE('E1194',#1956,#1965,#1963,.T.);
#1967=ORIENTED_EDGE('',*,*,#1966,.T.);
#1968=CARTESIAN_POINT('',(0.,4.73289312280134,16.2388091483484));
#1969=DIRECTION('',(-1.,0.,0.));
#1970=DIRECTION('',(0.,0.984807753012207,0.173648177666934));
#1971=AXIS2_PLACEMENT_3D('',#1968,#1969,#1970);
#1972=CIRCLE('',#1971,7.2);
#1973=CARTESIAN_POINT('',(0.,-1.95770175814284,18.898873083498));
#1974=VERTEX_POINT('',#1973);
#1975=EDGE_CURVE('E1197',#1965,#1974,#1972,.T.);
#1976=ORIENTED_EDGE('',*,*,#1975,.T.);
#1977=CARTESIAN_POINT('',(0.,-1.35379500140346,18.9517080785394));
#1978=VERTEX_POINT('',#1977);
#1979=EDGE_CURVE('E2112',#1974,#1978,#1201,.T.);
#1980=ORIENTED_EDGE('',*,*,#1979,.T.);
#1981=CARTESIAN_POINT('',(0.,-7.48082945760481,15.1702468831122));
#1982=DIRECTION('',(1.,0.,0.));
#1983=DIRECTION('',(0.,0.,-1.));
#1984=AXIS2_PLACEMENT_3D('',#1981,#1982,#1983);
#1985=CIRCLE('',#1984,7.2);
#1986=CARTESIAN_POINT('',(0.,-0.454664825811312,16.7428277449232));
#1987=VERTEX_POINT('',#1986);
#1988=EDGE_CURVE('E1821',#1987,#1978,#1985,.T.);
#1989=ORIENTED_EDGE('',*,*,#1988,.F.);
#1990=CARTESIAN_POINT('',(0.,0.,0.));
#1991=DIRECTION('',(-1.,0.,0.));
#1992=DIRECTION('',(0.,1.,0.));
#1993=AXIS2_PLACEMENT_3D('',#1990,#1991,#1992);
#1994=CIRCLE('',#1993,16.749);
#1995=CARTESIAN_POINT('',(0.,0.454664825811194,16.7428277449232));
#1996=VERTEX_POINT('',#1995);
#1997=EDGE_CURVE('E1172',#1987,#1996,#1994,.T.);
#1998=ORIENTED_EDGE('',*,*,#1997,.T.);
#1999=CARTESIAN_POINT('',(0.,7.4808294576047,15.1702468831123));
#2000=DIRECTION('',(-1.,0.,0.));
#2001=DIRECTION('',(0.,1.,0.));
#2002=AXIS2_PLACEMENT_3D('',#1999,#2000,#2001);
#2003=CIRCLE('',#2002,7.2);
#2004=CARTESIAN_POINT('',(0.,1.35379500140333,18.9517080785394));
#2005=VERTEX_POINT('',#2004);
#2006=EDGE_CURVE('E1175',#1996,#2005,#2003,.T.);
#2007=ORIENTED_EDGE('',*,*,#2006,.T.);
#2008=CARTESIAN_POINT('',(0.,1.95770175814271,18.898873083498));
#2009=VERTEX_POINT('',#2008);
#2010=EDGE_CURVE('E2109',#2005,#2009,#1201,.T.);
#2011=ORIENTED_EDGE('',*,*,#2010,.T.);
#2012=CARTESIAN_POINT('',(0.,-4.73289312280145,16.2388091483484));
#2013=DIRECTION('',(1.,0.,0.));
#2014=DIRECTION('',(0.,0.,-1.));
#2015=AXIS2_PLACEMENT_3D('',#2012,#2013,#2014);
#2016=CIRCLE('',#2015,7.2);
#2017=CARTESIAN_POINT('',(0.,2.45960408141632,16.5674182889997));
#2018=VERTEX_POINT('',#2017);
#2019=EDGE_CURVE('E1818',#2018,#2009,#2016,.T.);
#2020=ORIENTED_EDGE('',*,*,#2019,.F.);
#2021=CARTESIAN_POINT('',(0.,0.,0.));
#2022=DIRECTION('',(-1.,0.,0.));
#2023=DIRECTION('',(0.,0.984807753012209,-0.173648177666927));
#2024=AXIS2_PLACEMENT_3D('',#2021,#2022,#2023);
#2025=CIRCLE('',#2024,16.749);
#2026=CARTESIAN_POINT('',(0.,3.35511897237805,16.4095148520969));
#2027=VERTEX_POINT('',#2026);
#2028=EDGE_CURVE('E1150',#2018,#2027,#2025,.T.);
#2029=ORIENTED_EDGE('',*,*,#2028,.T.);
#2030=CARTESIAN_POINT('',(0.,10.0014645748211,13.6407443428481));
#2031=DIRECTION('',(-1.,0.,0.));
#2032=DIRECTION('',(0.,0.984807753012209,-0.173648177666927));
#2033=AXIS2_PLACEMENT_3D('',#2030,#2031,#2032);
#2034=CIRCLE('',#2033,7.2);
#2035=CARTESIAN_POINT('',(0.,4.62415738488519,18.4287050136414));
#2036=VERTEX_POINT('',#2035);
#2037=EDGE_CURVE('E1153',#2027,#2036,#2034,.T.);
#2038=ORIENTED_EDGE('',*,*,#2037,.T.);
#2039=CARTESIAN_POINT('',(0.,5.20971474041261,18.2718053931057));
#2040=VERTEX_POINT('',#2039);
#2041=EDGE_CURVE('E2106',#2036,#2040,#1201,.T.);
#2042=ORIENTED_EDGE('',*,*,#2041,.T.);
#2043=CARTESIAN_POINT('',(0.,-1.84115022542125,16.8139634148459));
#2044=DIRECTION('',(1.,0.,0.));
#2045=DIRECTION('',(0.,0.,-1.));
#2046=AXIS2_PLACEMENT_3D('',#2043,#2044,#2045);
#2047=CIRCLE('',#2046,7.2);
#2048=CARTESIAN_POINT('',(0.,5.29913916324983,15.888616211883));
#2049=VERTEX_POINT('',#2048);
#2050=EDGE_CURVE('E1815',#2049,#2040,#2047,.T.);
#2051=ORIENTED_EDGE('',*,*,#2050,.F.);
#2052=CARTESIAN_POINT('',(0.,0.,0.));
#2053=DIRECTION('',(-1.,0.,0.));
#2054=DIRECTION('',(0.,0.939692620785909,-0.342020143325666));
#2055=AXIS2_PLACEMENT_3D('',#2052,#2053,#2054);
#2056=CIRCLE('',#2055,16.749);
#2057=CARTESIAN_POINT('',(0.,6.15362952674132,15.5776071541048));
#2058=VERTEX_POINT('',#2057);
#2059=EDGE_CURVE('E1128',#2049,#2058,#2056,.T.);
#2060=ORIENTED_EDGE('',*,*,#2059,.T.);
#2061=CARTESIAN_POINT('',(0.,12.2182102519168,11.6967746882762));
#2062=DIRECTION('',(-1.,0.,0.));
#2063=DIRECTION('',(0.,0.939692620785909,-0.342020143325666));
#2064=AXIS2_PLACEMENT_3D('',#2061,#2062,#2063);
#2065=CIRCLE('',#2064,7.2);
#2066=CARTESIAN_POINT('',(0.,7.75401708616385,17.3457550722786));
#2067=VERTEX_POINT('',#2066);
#2068=EDGE_CURVE('E1131',#2058,#2067,#2065,.T.);
#2069=ORIENTED_EDGE('',*,*,#2068,.T.);
#2070=CARTESIAN_POINT('',(0.,8.30343317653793,17.0895581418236));
#2071=VERTEX_POINT('',#2070);
#2072=EDGE_CURVE('E2103',#2067,#2071,#1201,.T.);
#2073=ORIENTED_EDGE('',*,*,#2072,.T.);
#2074=CARTESIAN_POINT('',(0.,1.1065350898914,16.8782339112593));
#2075=DIRECTION('',(1.,0.,0.));
#2076=DIRECTION('',(0.,0.,-1.));
#2077=AXIS2_PLACEMENT_3D('',#2074,#2075,#2076);
#2078=CIRCLE('',#2077,7.2);
#2079=CARTESIAN_POINT('',(0.,7.97766258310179,14.7270465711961));
#2080=VERTEX_POINT('',#2079);
#2081=EDGE_CURVE('E1812',#2080,#2071,#2078,.T.);
#2082=ORIENTED_EDGE('',*,*,#2081,.F.);
#2083=CARTESIAN_POINT('',(0.,0.,0.));
#2084=DIRECTION('',(-1.,0.,0.));
#2085=DIRECTION('',(0.,0.86602540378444,-0.499999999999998));
#2086=AXIS2_PLACEMENT_3D('',#2083,#2084,#2085);
#2087=CIRCLE('',#2086,16.749);
#2088=CARTESIAN_POINT('',(0.,8.76516516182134,14.2723817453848));
#2089=VERTEX_POINT('',#2088);
#2090=EDGE_CURVE('E1106',#2080,#2089,#2087,.T.);
#2091=ORIENTED_EDGE('',*,*,#2090,.T.);
#2092=CARTESIAN_POINT('',(0.,14.0637117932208,9.39740445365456));
#2093=DIRECTION('',(-1.,0.,0.));
#2094=DIRECTION('',(0.,0.86602540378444,-0.499999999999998));
#2095=AXIS2_PLACEMENT_3D('',#2092,#2093,#2094);
#2096=CIRCLE('',#2095,7.2);
#2097=CARTESIAN_POINT('',(0.,10.6482749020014,15.7357631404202));
#2098=VERTEX_POINT('',#2097);
#2099=EDGE_CURVE('E1109',#2089,#2098,#2096,.T.);
#2100=ORIENTED_EDGE('',*,*,#2099,.T.);
#2101=CARTESIAN_POINT('',(0.,11.1448559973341,15.3880533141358));
#2102=VERTEX_POINT('',#2101);
#2103=EDGE_CURVE('E2100',#2098,#2102,#1201,.T.);
#2104=ORIENTED_EDGE('',*,*,#2103,.T.);
#2105=CARTESIAN_POINT('',(0.,4.02059889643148,16.4296678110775));
#2106=DIRECTION('',(1.,0.,0.));
#2107=DIRECTION('',(0.,0.,-1.));
#2108=AXIS2_PLACEMENT_3D('',#2105,#2106,#2107);
#2109=CIRCLE('',#2108,7.2);
#2110=CARTESIAN_POINT('',(0.,10.4137887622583,13.1180030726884));
#2111=VERTEX_POINT('',#2110);
#2112=EDGE_CURVE('E1809',#2111,#2102,#2109,.T.);
#2113=ORIENTED_EDGE('',*,*,#2112,.F.);
#2114=CARTESIAN_POINT('',(0.,0.,0.));
#2115=DIRECTION('',(-1.,0.,0.));
#2116=DIRECTION('',(0.,0.766044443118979,-0.642787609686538));
#2117=AXIS2_PLACEMENT_3D('',#2114,#2115,#2116);
#2118=CIRCLE('',#2117,16.749);
#2119=CARTESIAN_POINT('',(0.,11.110375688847,12.5334972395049));
#2120=VERTEX_POINT('',#2119);
#2121=EDGE_CURVE('E1084',#2111,#2120,#2118,.T.);
#2122=ORIENTED_EDGE('',*,*,#2121,.T.);
#2123=CARTESIAN_POINT('',(0.,15.4818945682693,6.81249884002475));
#2124=DIRECTION('',(-1.,0.,0.));
#2125=DIRECTION('',(0.,0.766044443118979,-0.642787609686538));
#2126=AXIS2_PLACEMENT_3D('',#2123,#2124,#2125);
#2127=CIRCLE('',#2126,7.2);
#2128=CARTESIAN_POINT('',(0.,13.2189902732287,13.6476480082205));
#2129=VERTEX_POINT('',#2128);
#2130=EDGE_CURVE('E1087',#2120,#2129,#2127,.T.);
#2131=ORIENTED_EDGE('',*,*,#2130,.T.);
#2132=CARTESIAN_POINT('',(0.,13.6476480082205,13.2189902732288));
#2133=VERTEX_POINT('',#2132);
#2134=EDGE_CURVE('E2097',#2129,#2133,#1201,.T.);
#2135=ORIENTED_EDGE('',*,*,#2134,.T.);
#2136=CARTESIAN_POINT('',(0.,6.8124988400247,15.4818945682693));
#2137=DIRECTION('',(1.,0.,0.));
#2138=DIRECTION('',(0.,0.,-1.));
#2139=AXIS2_PLACEMENT_3D('',#2136,#2137,#2138);
#2140=CIRCLE('',#2139,7.2);
#2141=CARTESIAN_POINT('',(0.,12.5334972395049,11.110375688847));
#2142=VERTEX_POINT('',#2141);
#2143=EDGE_CURVE('E1806',#2142,#2133,#2140,.T.);
#2144=ORIENTED_EDGE('',*,*,#2143,.F.);
#2145=CARTESIAN_POINT('',(0.,0.,0.));
#2146=DIRECTION('',(-1.,0.,0.));
#2147=DIRECTION('',(0.,0.642787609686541,-0.766044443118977));
#2148=AXIS2_PLACEMENT_3D('',#2145,#2146,#2147);
#2149=CIRCLE('',#2148,16.749);
#2150=CARTESIAN_POINT('',(0.,13.1180030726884,10.4137887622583));
#2151=VERTEX_POINT('',#2150);
#2152=EDGE_CURVE('E1062',#2142,#2151,#2149,.T.);
#2153=ORIENTED_EDGE('',*,*,#2152,.T.);
#2154=CARTESIAN_POINT('',(0.,16.4296678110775,4.02059889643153));
#2155=DIRECTION('',(-1.,0.,0.));
#2156=DIRECTION('',(0.,0.642787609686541,-0.766044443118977));
#2157=AXIS2_PLACEMENT_3D('',#2154,#2155,#2156);
#2158=CIRCLE('',#2157,7.2);
#2159=CARTESIAN_POINT('',(0.,15.3880533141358,11.1448559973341));
#2160=VERTEX_POINT('',#2159);
#2161=EDGE_CURVE('E1065',#2151,#2160,#2158,.T.);
#2162=ORIENTED_EDGE('',*,*,#2161,.T.);
#2163=CARTESIAN_POINT('',(0.,15.7357631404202,10.6482749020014));
#2164=VERTEX_POINT('',#2163);
#2165=EDGE_CURVE('E2096',#2160,#2164,#1201,.T.);
#2166=ORIENTED_EDGE('',*,*,#2165,.T.);
#2167=CARTESIAN_POINT('',(0.,9.3974044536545,14.0637117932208));
#2168=DIRECTION('',(1.,0.,0.));
#2169=DIRECTION('',(0.,0.,-1.));
#2170=AXIS2_PLACEMENT_3D('',#2167,#2168,#2169);
#2171=CIRCLE('',#2170,7.2);
#2172=CARTESIAN_POINT('',(0.,14.2723817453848,8.76516516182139));
#2173=VERTEX_POINT('',#2172);
#2174=EDGE_CURVE('E1803',#2173,#2164,#2171,.T.);
#2175=ORIENTED_EDGE('',*,*,#2174,.F.);
#2176=CARTESIAN_POINT('',(0.,0.,0.));
#2177=DIRECTION('',(-1.,0.,0.));
#2178=DIRECTION('',(0.,0.500000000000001,-0.866025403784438));
#2179=AXIS2_PLACEMENT_3D('',#2176,#2177,#2178);
#2180=CIRCLE('',#2179,16.749);
#2181=CARTESIAN_POINT('',(0.,14.727046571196,7.97766258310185));
#2182=VERTEX_POINT('',#2181);
#2183=EDGE_CURVE('E1040',#2173,#2182,#2180,.T.);
#2184=ORIENTED_EDGE('',*,*,#2183,.T.);
#2185=CARTESIAN_POINT('',(0.,16.8782339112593,1.10653508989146));
#2186=DIRECTION('',(-1.,0.,0.));
#2187=DIRECTION('',(0.,0.500000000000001,-0.866025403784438));
#2188=AXIS2_PLACEMENT_3D('',#2185,#2186,#2187);
#2189=CIRCLE('',#2188,7.2);
#2190=CARTESIAN_POINT('',(0.,17.0895581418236,8.30343317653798));
#2191=VERTEX_POINT('',#2190);
#2192=EDGE_CURVE('E1043',#2182,#2191,#2189,.T.);
#2193=ORIENTED_EDGE('',*,*,#2192,.T.);
#2194=CARTESIAN_POINT('',(0.,17.3457550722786,7.75401708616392));
#2195=VERTEX_POINT('',#2194);
#2196=EDGE_CURVE('E961',#2191,#2195,#1201,.T.);
#2197=ORIENTED_EDGE('',*,*,#2196,.T.);
#2198=CARTESIAN_POINT('',(0.,11.6967746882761,12.2182102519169));
#2199=DIRECTION('',(1.,0.,0.));
#2200=DIRECTION('',(0.,0.,-1.));
#2201=AXIS2_PLACEMENT_3D('',#2198,#2199,#2200);
#2202=CIRCLE('',#2201,7.2);
#2203=CARTESIAN_POINT('',(0.,15.5776071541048,6.15362952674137));
#2204=VERTEX_POINT('',#2203);
#2205=EDGE_CURVE('E1796',#2204,#2195,#2202,.T.);
#2206=ORIENTED_EDGE('',*,*,#2205,.F.);
#2207=CARTESIAN_POINT('',(0.,0.,0.));
#2208=DIRECTION('',(-1.,0.,0.));
#2209=DIRECTION('',(0.,0.342020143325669,-0.939692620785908));
#2210=AXIS2_PLACEMENT_3D('',#2207,#2208,#2209);
#2211=CIRCLE('',#2210,16.749);
#2212=CARTESIAN_POINT('',(0.,15.888616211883,5.29913916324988));
#2213=VERTEX_POINT('',#2212);
#2214=EDGE_CURVE('E1018',#2204,#2213,#2211,.T.);
#2215=ORIENTED_EDGE('',*,*,#2214,.T.);
#2216=CARTESIAN_POINT('',(0.,16.8139634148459,-1.8411502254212));
#2217=DIRECTION('',(-1.,0.,0.));
#2218=DIRECTION('',(0.,0.342020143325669,-0.939692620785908));
#2219=AXIS2_PLACEMENT_3D('',#2216,#2217,#2218);
#2220=CIRCLE('',#2219,7.2);
#2221=CARTESIAN_POINT('',(0.,18.2718053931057,5.20971474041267));
#2222=VERTEX_POINT('',#2221);
#2223=EDGE_CURVE('E1021',#2213,#2222,#2220,.T.);
#2224=ORIENTED_EDGE('',*,*,#2223,.T.);
#2225=CARTESIAN_POINT('',(0.,18.4287050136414,4.62415738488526));
#2226=VERTEX_POINT('',#2225);
#2227=EDGE_CURVE('E955',#2222,#2226,#1201,.T.);
#2228=ORIENTED_EDGE('',*,*,#2227,.T.);
#2229=CARTESIAN_POINT('',(0.,13.6407443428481,10.0014645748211));
#2230=DIRECTION('',(1.,0.,0.));
#2231=DIRECTION('',(0.,0.,-1.));
#2232=AXIS2_PLACEMENT_3D('',#2229,#2230,#2231);
#2233=CIRCLE('',#2232,7.2);
#2234=CARTESIAN_POINT('',(0.,16.4095148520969,3.35511897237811));
#2235=VERTEX_POINT('',#2234);
#2236=EDGE_CURVE('E1793',#2235,#2226,#2233,.T.);
#2237=ORIENTED_EDGE('',*,*,#2236,.F.);
#2238=CARTESIAN_POINT('',(0.,0.,0.));
#2239=DIRECTION('',(-1.,0.,0.));
#2240=DIRECTION('',(0.,0.173648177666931,-0.984807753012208));
#2241=AXIS2_PLACEMENT_3D('',#2238,#2239,#2240);
#2242=CIRCLE('',#2241,16.749);
#2243=CARTESIAN_POINT('',(0.,16.5674182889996,2.45960408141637));
#2244=VERTEX_POINT('',#2243);
#2245=EDGE_CURVE('E997',#2235,#2244,#2242,.T.);
#2246=ORIENTED_EDGE('',*,*,#2245,.T.);
#2247=CARTESIAN_POINT('',(0.,16.2388091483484,-4.73289312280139));
#2248=DIRECTION('',(-1.,0.,0.));
#2249=DIRECTION('',(0.,0.173648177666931,-0.984807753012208));
#2250=AXIS2_PLACEMENT_3D('',#2247,#2248,#2249);
#2251=CIRCLE('',#2250,7.2);
#2252=CARTESIAN_POINT('',(0.,18.898873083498,1.95770175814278));
#2253=VERTEX_POINT('',#2252);
#2254=EDGE_CURVE('E1000',#2244,#2253,#2251,.T.);
#2255=ORIENTED_EDGE('',*,*,#2254,.T.);
#2256=CARTESIAN_POINT('',(0.,18.9517080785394,1.3537950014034));
#2257=VERTEX_POINT('',#2256);
#2258=EDGE_CURVE('E949',#2253,#2257,#1201,.T.);
#2259=ORIENTED_EDGE('',*,*,#2258,.T.);
#2260=CARTESIAN_POINT('',(0.,15.1702468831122,7.48082945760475));
#2261=DIRECTION('',(1.,0.,0.));
#2262=DIRECTION('',(0.,0.,-1.));
#2263=AXIS2_PLACEMENT_3D('',#2260,#2261,#2262);
#2264=CIRCLE('',#2263,7.2);
#2265=CARTESIAN_POINT('',(0.,16.7428277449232,0.454664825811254));
#2266=VERTEX_POINT('',#2265);
#2267=EDGE_CURVE('E1792',#2266,#2257,#2264,.T.);
#2268=ORIENTED_EDGE('',*,*,#2267,.F.);
#2269=CARTESIAN_POINT('',(0.,0.,0.));
#2270=DIRECTION('',(-1.,0.,0.));
#2271=DIRECTION('',(0.,0.,-1.));
#2272=AXIS2_PLACEMENT_3D('',#2269,#2270,#2271);
#2273=CIRCLE('',#2272,16.749);
#2274=CARTESIAN_POINT('',(0.,16.7428277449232,-0.454664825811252));
#2275=VERTEX_POINT('',#2274);
#2276=EDGE_CURVE('E978',#2266,#2275,#2273,.T.);
#2277=ORIENTED_EDGE('',*,*,#2276,.T.);
#2278=CARTESIAN_POINT('',(0.,15.1702468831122,-7.48082945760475));
#2279=DIRECTION('',(-1.,0.,0.));
#2280=DIRECTION('',(0.,0.,-1.));
#2281=AXIS2_PLACEMENT_3D('',#2278,#2279,#2280);
#2282=CIRCLE('',#2281,7.2);
#2283=CARTESIAN_POINT('',(0.,18.9517080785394,-1.3537950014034));
#2284=VERTEX_POINT('',#2283);
#2285=EDGE_CURVE('E943',#2275,#2284,#2282,.T.);
#2286=ORIENTED_EDGE('',*,*,#2285,.T.);
#2287=CARTESIAN_POINT('',(0.,18.898873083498,-1.95770175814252));
#2288=VERTEX_POINT('',#2287);
#2289=EDGE_CURVE('E941',#2284,#2288,#1201,.T.);
#2290=ORIENTED_EDGE('',*,*,#2289,.T.);
#2291=CARTESIAN_POINT('',(0.,16.2388091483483,4.73289312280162));
#2292=DIRECTION('',(1.,0.,0.));
#2293=DIRECTION('',(0.,0.,-1.));
#2294=AXIS2_PLACEMENT_3D('',#2291,#2292,#2293);
#2295=CIRCLE('',#2294,7.2);
#2296=CARTESIAN_POINT('',(0.,16.5674182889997,-2.45960408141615));
#2297=VERTEX_POINT('',#2296);
#2298=EDGE_CURVE('E11',#2297,#2288,#2295,.T.);
#2299=ORIENTED_EDGE('',*,*,#2298,.F.);
#2300=CARTESIAN_POINT('',(0.,0.,0.));
#2301=DIRECTION('',(-1.,0.,0.));
#2302=DIRECTION('',(0.,-0.173648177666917,-0.984807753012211));
#2303=AXIS2_PLACEMENT_3D('',#2300,#2301,#2302);
#2304=CIRCLE('',#2303,16.749);
#2305=EDGE_CURVE('E931',#2297,#1192,#2304,.T.);
#2306=ORIENTED_EDGE('',*,*,#2305,.T.);
#2307=EDGE_LOOP('',(#1196,#1205,#1214,#1223,#1232,#1236,#1245,#1254,#1263,#1267,#1276,#1285,
#1294,#1298,#1307,#1316,#1325,#1329,#1338,#1347,#1356,#1360,#1369,#1378,#1387,#1391,#1400,#1409,
#1418,#1422,#1431,#1440,#1449,#1453,#1462,#1471,#1480,#1484,#1493,#1502,#1511,#1515,#1524,#1533,
#1542,#1546,#1555,#1564,#1573,#1577,#1586,#1595,#1604,#1608,#1617,#1626,#1635,#1639,#1648,#1657,
#1666,#1670,#1679,#1688,#1697,#1701,#1710,#1719,#1728,#1732,#1741,#1750,#1759,#1763,#1772,#1781,
#1790,#1794,#1803,#1812,#1821,#1825,#1834,#1843,#1852,#1856,#1865,#1874,#1883,#1887,#1896,#1905,
#1914,#1918,#1927,#1936,#1945,#1949,#1958,#1967,#1976,#1980,#1989,#1998,#2007,#2011,#2020,#2029,
#2038,#2042,#2051,#2060,#2069,#2073,#2082,#2091,#2100,#2104,#2113,#2122,#2131,#2135,#2144,#2153,
#2162,#2166,#2175,#2184,#2193,#2197,#2206,#2215,#2224,#2228,#2237,#2246,#2255,#2259,#2268,#2277,
#2286,#2290,#2299,#2306));
#2308=FACE_BOUND('',#2307,.T.);
#2309=CARTESIAN_POINT('',(0.,0.,0.));
#2310=DIRECTION('',(1.,0.,0.));
#2311=DIRECTION('',(0.,0.,-1.));
#2312=AXIS2_PLACEMENT_3D('',#2309,#2310,#2311);
#2313=CIRCLE('',#2312,6.);
#2314=CARTESIAN_POINT('',(0.,0.,-6.));
#2315=VERTEX_POINT('',#2314);
#2316=EDGE_CURVE('E40',#2315,#2315,#2313,.F.);
#2317=ORIENTED_EDGE('',*,*,#2316,.F.);
#2318=EDGE_LOOP('',(#2317));
#2319=FACE_BOUND('',#2318,.T.);
#2320=ADVANCED_FACE('F937',(#1185,#2308,#2319),#1174,.F.);
#2321=CARTESIAN_POINT('',(-10.,0.,0.));
#2322=DIRECTION('',(-1.,0.,0.));
#2323=DIRECTION('',(0.,0.,1.));
#2324=AXIS2_PLACEMENT_3D('',#2321,#2322,#2323);
#2325=CYLINDRICAL_SURFACE('',#2324,19.);
#2326=DIRECTION('',(-1.,0.,0.));
#2327=VECTOR('',#2326,1.);
#2328=CARTESIAN_POINT('',(6.,18.4287050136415,-4.624157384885));
#2329=LINE('',#2328,#2327);
#2330=EDGE_CURVE('E1725',#43,#1194,#2329,.T.);
#2331=ORIENTED_EDGE('',*,*,#2330,.F.);
#2332=ORIENTED_EDGE('',*,*,#1154,.T.);
#2333=DIRECTION('',(-1.,0.,0.));
#2334=VECTOR('',#2333,1.);
#2335=CARTESIAN_POINT('',(6.,18.2718053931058,-5.20971474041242));
#2336=LINE('',#2335,#2334);
#2337=EDGE_CURVE('E1708',#1203,#1151,#2336,.F.);
#2338=ORIENTED_EDGE('',*,*,#2337,.F.);
#2339=ORIENTED_EDGE('',*,*,#1204,.F.);
#2340=EDGE_LOOP('',(#2331,#2332,#2338,#2339));
#2341=FACE_BOUND('',#2340,.T.);
#2342=ADVANCED_FACE('F1750',(#2341),#2325,.T.);
#2343=DIRECTION('',(-1.,0.,0.));
#2344=VECTOR('',#2343,1.);
#2345=CARTESIAN_POINT('',(6.,18.898873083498,-1.95770175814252));
#2346=LINE('',#2345,#2344);
#2347=EDGE_CURVE('E927',#2288,#61,#2346,.F.);
#2348=ORIENTED_EDGE('',*,*,#2347,.F.);
#2349=ORIENTED_EDGE('',*,*,#2289,.F.);
#2350=DIRECTION('',(-1.,0.,0.));
#2351=VECTOR('',#2350,1.);
#2352=CARTESIAN_POINT('',(6.,18.9517080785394,-1.3537950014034));
#2353=LINE('',#2352,#2351);
#2354=EDGE_CURVE('E956',#70,#2284,#2353,.T.);
#2355=ORIENTED_EDGE('',*,*,#2354,.F.);
#2356=ORIENTED_EDGE('',*,*,#71,.T.);
#2357=EDGE_LOOP('',(#2348,#2349,#2355,#2356));
#2358=FACE_BOUND('',#2357,.T.);
#2359=ADVANCED_FACE('F1757',(#2358),#2325,.T.);
#2360=DIRECTION('',(-1.,0.,0.));
#2361=VECTOR('',#2360,1.);
#2362=CARTESIAN_POINT('',(6.,17.3457550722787,-7.75401708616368));
#2363=LINE('',#2362,#2361);
#2364=EDGE_CURVE('E1706',#1124,#1230,#2363,.T.);
#2365=ORIENTED_EDGE('',*,*,#2364,.F.);
#2366=ORIENTED_EDGE('',*,*,#1125,.T.);
#2367=DIRECTION('',(-1.,0.,0.));
#2368=VECTOR('',#2367,1.);
#2369=CARTESIAN_POINT('',(6.,17.0895581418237,-8.30343317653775));
#2370=LINE('',#2369,#2368);
#2371=EDGE_CURVE('E1686',#1234,#1120,#2370,.F.);
#2372=ORIENTED_EDGE('',*,*,#2371,.F.);
#2373=ORIENTED_EDGE('',*,*,#1235,.F.);
#2374=EDGE_LOOP('',(#2365,#2366,#2372,#2373));
#2375=FACE_BOUND('',#2374,.T.);
#2376=ADVANCED_FACE('F2193',(#2375),#2325,.T.);
#2377=DIRECTION('',(-1.,0.,0.));
#2378=VECTOR('',#2377,1.);
#2379=CARTESIAN_POINT('',(6.,15.7357631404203,-10.6482749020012));
#2380=LINE('',#2379,#2378);
#2381=EDGE_CURVE('E1684',#1093,#1261,#2380,.T.);
#2382=ORIENTED_EDGE('',*,*,#2381,.F.);
#2383=ORIENTED_EDGE('',*,*,#1094,.T.);
#2384=DIRECTION('',(-1.,0.,0.));
#2385=VECTOR('',#2384,1.);
#2386=CARTESIAN_POINT('',(6.,15.388053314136,-11.1448559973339));
#2387=LINE('',#2386,#2385);
#2388=EDGE_CURVE('E1664',#1265,#1089,#2387,.F.);
#2389=ORIENTED_EDGE('',*,*,#2388,.F.);
#2390=ORIENTED_EDGE('',*,*,#1266,.F.);
#2391=EDGE_LOOP('',(#2382,#2383,#2389,#2390));
#2392=FACE_BOUND('',#2391,.T.);
#2393=ADVANCED_FACE('F2195',(#2392),#2325,.T.);
#2394=DIRECTION('',(-1.,0.,0.));
#2395=VECTOR('',#2394,1.);
#2396=CARTESIAN_POINT('',(6.,13.6476480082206,-13.2189902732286));
#2397=LINE('',#2396,#2395);
#2398=EDGE_CURVE('E1662',#1062,#1292,#2397,.T.);
#2399=ORIENTED_EDGE('',*,*,#2398,.F.);
#2400=ORIENTED_EDGE('',*,*,#1063,.T.);
#2401=DIRECTION('',(-1.,0.,0.));
#2402=VECTOR('',#2401,1.);
#2403=CARTESIAN_POINT('',(6.,13.2189902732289,-13.6476480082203));
#2404=LINE('',#2403,#2402);
#2405=EDGE_CURVE('E1642',#1296,#1058,#2404,.F.);
#2406=ORIENTED_EDGE('',*,*,#2405,.F.);
#2407=ORIENTED_EDGE('',*,*,#1297,.F.);
#2408=EDGE_LOOP('',(#2399,#2400,#2406,#2407));
#2409=FACE_BOUND('',#2408,.T.);
#2410=ADVANCED_FACE('F2200',(#2409),#2325,.T.);
#2411=DIRECTION('',(-1.,0.,0.));
#2412=VECTOR('',#2411,1.);
#2413=CARTESIAN_POINT('',(6.,11.1448559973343,-15.3880533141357));
#2414=LINE('',#2413,#2412);
#2415=EDGE_CURVE('E1640',#1031,#1323,#2414,.T.);
#2416=ORIENTED_EDGE('',*,*,#2415,.F.);
#2417=ORIENTED_EDGE('',*,*,#1032,.T.);
#2418=DIRECTION('',(-1.,0.,0.));
#2419=VECTOR('',#2418,1.);
#2420=CARTESIAN_POINT('',(6.,10.6482749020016,-15.7357631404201));
#2421=LINE('',#2420,#2419);
#2422=EDGE_CURVE('E1620',#1327,#1027,#2421,.F.);
#2423=ORIENTED_EDGE('',*,*,#2422,.F.);
#2424=ORIENTED_EDGE('',*,*,#1328,.F.);
#2425=EDGE_LOOP('',(#2416,#2417,#2423,#2424));
#2426=FACE_BOUND('',#2425,.T.);
#2427=ADVANCED_FACE('F3376',(#2426),#2325,.T.);
#2428=DIRECTION('',(-1.,0.,0.));
#2429=VECTOR('',#2428,1.);
#2430=CARTESIAN_POINT('',(6.,8.30343317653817,-17.0895581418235));
#2431=LINE('',#2430,#2429);
#2432=EDGE_CURVE('E1618',#1000,#1354,#2431,.T.);
#2433=ORIENTED_EDGE('',*,*,#2432,.F.);
#2434=ORIENTED_EDGE('',*,*,#1001,.T.);
#2435=DIRECTION('',(-1.,0.,0.));
#2436=VECTOR('',#2435,1.);
#2437=CARTESIAN_POINT('',(6.,7.75401708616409,-17.3457550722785));
#2438=LINE('',#2437,#2436);
#2439=EDGE_CURVE('E1598',#1358,#996,#2438,.F.);
#2440=ORIENTED_EDGE('',*,*,#2439,.F.);
#2441=ORIENTED_EDGE('',*,*,#1359,.F.);
#2442=EDGE_LOOP('',(#2433,#2434,#2440,#2441));
#2443=FACE_BOUND('',#2442,.T.);
#2444=ADVANCED_FACE('F3369',(#2443),#2325,.T.);
#2445=DIRECTION('',(-1.,0.,0.));
#2446=VECTOR('',#2445,1.);
#2447=CARTESIAN_POINT('',(6.,5.20971474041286,-18.2718053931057));
#2448=LINE('',#2447,#2446);
#2449=EDGE_CURVE('E1596',#969,#1385,#2448,.T.);
#2450=ORIENTED_EDGE('',*,*,#2449,.F.);
#2451=ORIENTED_EDGE('',*,*,#970,.T.);
#2452=DIRECTION('',(-1.,0.,0.));
#2453=VECTOR('',#2452,1.);
#2454=CARTESIAN_POINT('',(6.,4.62415738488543,-18.4287050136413));
#2455=LINE('',#2454,#2453);
#2456=EDGE_CURVE('E1576',#1389,#965,#2455,.F.);
#2457=ORIENTED_EDGE('',*,*,#2456,.F.);
#2458=ORIENTED_EDGE('',*,*,#1390,.F.);
#2459=EDGE_LOOP('',(#2450,#2451,#2457,#2458));
#2460=FACE_BOUND('',#2459,.T.);
#2461=ADVANCED_FACE('F3362',(#2460),#2325,.T.);
#2462=DIRECTION('',(-1.,0.,0.));
#2463=VECTOR('',#2462,1.);
#2464=CARTESIAN_POINT('',(6.,1.95770175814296,-18.898873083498));
#2465=LINE('',#2464,#2463);
#2466=EDGE_CURVE('E1574',#938,#1416,#2465,.T.);
#2467=ORIENTED_EDGE('',*,*,#2466,.F.);
#2468=ORIENTED_EDGE('',*,*,#939,.T.);
#2469=DIRECTION('',(-1.,0.,0.));
#2470=VECTOR('',#2469,1.);
#2471=CARTESIAN_POINT('',(6.,1.3537950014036,-18.9517080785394));
#2472=LINE('',#2471,#2470);
#2473=EDGE_CURVE('E1554',#1420,#934,#2472,.F.);
#2474=ORIENTED_EDGE('',*,*,#2473,.F.);
#2475=ORIENTED_EDGE('',*,*,#1421,.F.);
#2476=EDGE_LOOP('',(#2467,#2468,#2474,#2475));
#2477=FACE_BOUND('',#2476,.T.);
#2478=ADVANCED_FACE('F3355',(#2477),#2325,.T.);
#2479=DIRECTION('',(-1.,0.,0.));
#2480=VECTOR('',#2479,1.);
#2481=CARTESIAN_POINT('',(6.,-1.3537950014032,-18.9517080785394));
#2482=LINE('',#2481,#2480);
#2483=EDGE_CURVE('E1552',#907,#1447,#2482,.T.);
#2484=ORIENTED_EDGE('',*,*,#2483,.F.);
#2485=ORIENTED_EDGE('',*,*,#908,.T.);
#2486=DIRECTION('',(-1.,0.,0.));
#2487=VECTOR('',#2486,1.);
#2488=CARTESIAN_POINT('',(6.,-1.95770175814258,-18.898873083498));
#2489=LINE('',#2488,#2487);
#2490=EDGE_CURVE('E1532',#1451,#903,#2489,.F.);
#2491=ORIENTED_EDGE('',*,*,#2490,.F.);
#2492=ORIENTED_EDGE('',*,*,#1452,.F.);
#2493=EDGE_LOOP('',(#2484,#2485,#2491,#2492));
#2494=FACE_BOUND('',#2493,.T.);
#2495=ADVANCED_FACE('F3348',(#2494),#2325,.T.);
#2496=DIRECTION('',(-1.,0.,0.));
#2497=VECTOR('',#2496,1.);
#2498=CARTESIAN_POINT('',(6.,-4.62415738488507,-18.4287050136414));
#2499=LINE('',#2498,#2497);
#2500=EDGE_CURVE('E1530',#876,#1478,#2499,.T.);
#2501=ORIENTED_EDGE('',*,*,#2500,.F.);
#2502=ORIENTED_EDGE('',*,*,#877,.T.);
#2503=DIRECTION('',(-1.,0.,0.));
#2504=VECTOR('',#2503,1.);
#2505=CARTESIAN_POINT('',(6.,-5.20971474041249,-18.2718053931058));
#2506=LINE('',#2505,#2504);
#2507=EDGE_CURVE('E1510',#1482,#872,#2506,.F.);
#2508=ORIENTED_EDGE('',*,*,#2507,.F.);
#2509=ORIENTED_EDGE('',*,*,#1483,.F.);
#2510=EDGE_LOOP('',(#2501,#2502,#2508,#2509));
#2511=FACE_BOUND('',#2510,.T.);
#2512=ADVANCED_FACE('F3341',(#2511),#2325,.T.);
#2513=DIRECTION('',(-1.,0.,0.));
#2514=VECTOR('',#2513,1.);
#2515=CARTESIAN_POINT('',(6.,-7.75401708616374,-17.3457550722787));
#2516=LINE('',#2515,#2514);
#2517=EDGE_CURVE('E1508',#845,#1509,#2516,.T.);
#2518=ORIENTED_EDGE('',*,*,#2517,.F.);
#2519=ORIENTED_EDGE('',*,*,#846,.T.);
#2520=DIRECTION('',(-1.,0.,0.));
#2521=VECTOR('',#2520,1.);
#2522=CARTESIAN_POINT('',(6.,-8.30343317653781,-17.0895581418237));
#2523=LINE('',#2522,#2521);
#2524=EDGE_CURVE('E1488',#1513,#841,#2523,.F.);
#2525=ORIENTED_EDGE('',*,*,#2524,.F.);
#2526=ORIENTED_EDGE('',*,*,#1514,.F.);
#2527=EDGE_LOOP('',(#2518,#2519,#2525,#2526));
#2528=FACE_BOUND('',#2527,.T.);
#2529=ADVANCED_FACE('F3334',(#2528),#2325,.T.);
#2530=DIRECTION('',(-1.,0.,0.));
#2531=VECTOR('',#2530,1.);
#2532=CARTESIAN_POINT('',(6.,-10.6482749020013,-15.7357631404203));
#2533=LINE('',#2532,#2531);
#2534=EDGE_CURVE('E1486',#814,#1540,#2533,.T.);
#2535=ORIENTED_EDGE('',*,*,#2534,.F.);
#2536=ORIENTED_EDGE('',*,*,#815,.T.);
#2537=DIRECTION('',(-1.,0.,0.));
#2538=VECTOR('',#2537,1.);
#2539=CARTESIAN_POINT('',(6.,-11.144855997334,-15.3880533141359));
#2540=LINE('',#2539,#2538);
#2541=EDGE_CURVE('E1466',#1544,#810,#2540,.F.);
#2542=ORIENTED_EDGE('',*,*,#2541,.F.);
#2543=ORIENTED_EDGE('',*,*,#1545,.F.);
#2544=EDGE_LOOP('',(#2535,#2536,#2542,#2543));
#2545=FACE_BOUND('',#2544,.T.);
#2546=ADVANCED_FACE('F3327',(#2545),#2325,.T.);
#2547=DIRECTION('',(-1.,0.,0.));
#2548=VECTOR('',#2547,1.);
#2549=CARTESIAN_POINT('',(6.,-13.2189902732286,-13.6476480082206));
#2550=LINE('',#2549,#2548);
#2551=EDGE_CURVE('E1464',#783,#1571,#2550,.T.);
#2552=ORIENTED_EDGE('',*,*,#2551,.F.);
#2553=ORIENTED_EDGE('',*,*,#784,.T.);
#2554=DIRECTION('',(-1.,0.,0.));
#2555=VECTOR('',#2554,1.);
#2556=CARTESIAN_POINT('',(6.,-13.6476480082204,-13.2189902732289));
#2557=LINE('',#2556,#2555);
#2558=EDGE_CURVE('E1444',#1575,#779,#2557,.F.);
#2559=ORIENTED_EDGE('',*,*,#2558,.F.);
#2560=ORIENTED_EDGE('',*,*,#1576,.F.);
#2561=EDGE_LOOP('',(#2552,#2553,#2559,#2560));
#2562=FACE_BOUND('',#2561,.T.);
#2563=ADVANCED_FACE('F3320',(#2562),#2325,.T.);
#2564=DIRECTION('',(-1.,0.,0.));
#2565=VECTOR('',#2564,1.);
#2566=CARTESIAN_POINT('',(6.,-15.3880533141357,-11.1448559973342));
#2567=LINE('',#2566,#2565);
#2568=EDGE_CURVE('E1442',#752,#1602,#2567,.T.);
#2569=ORIENTED_EDGE('',*,*,#2568,.F.);
#2570=ORIENTED_EDGE('',*,*,#753,.T.);
#2571=DIRECTION('',(-1.,0.,0.));
#2572=VECTOR('',#2571,1.);
#2573=CARTESIAN_POINT('',(6.,-15.7357631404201,-10.6482749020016));
#2574=LINE('',#2573,#2572);
#2575=EDGE_CURVE('E1422',#1606,#748,#2574,.F.);
#2576=ORIENTED_EDGE('',*,*,#2575,.F.);
#2577=ORIENTED_EDGE('',*,*,#1607,.F.);
#2578=EDGE_LOOP('',(#2569,#2570,#2576,#2577));
#2579=FACE_BOUND('',#2578,.T.);
#2580=ADVANCED_FACE('F3313',(#2579),#2325,.T.);
#2581=DIRECTION('',(-1.,0.,0.));
#2582=VECTOR('',#2581,1.);
#2583=CARTESIAN_POINT('',(6.,-17.0895581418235,-8.30343317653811));
#2584=LINE('',#2583,#2582);
#2585=EDGE_CURVE('E1420',#721,#1633,#2584,.T.);
#2586=ORIENTED_EDGE('',*,*,#2585,.F.);
#2587=ORIENTED_EDGE('',*,*,#722,.T.);
#2588=DIRECTION('',(-1.,0.,0.));
#2589=VECTOR('',#2588,1.);
#2590=CARTESIAN_POINT('',(6.,-17.3457550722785,-7.75401708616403));
#2591=LINE('',#2590,#2589);
#2592=EDGE_CURVE('E1400',#1637,#717,#2591,.F.);
#2593=ORIENTED_EDGE('',*,*,#2592,.F.);
#2594=ORIENTED_EDGE('',*,*,#1638,.F.);
#2595=EDGE_LOOP('',(#2586,#2587,#2593,#2594));
#2596=FACE_BOUND('',#2595,.T.);
#2597=ADVANCED_FACE('F3306',(#2596),#2325,.T.);
#2598=DIRECTION('',(-1.,0.,0.));
#2599=VECTOR('',#2598,1.);
#2600=CARTESIAN_POINT('',(6.,-18.2718053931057,-5.20971474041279));
#2601=LINE('',#2600,#2599);
#2602=EDGE_CURVE('E1398',#690,#1664,#2601,.T.);
#2603=ORIENTED_EDGE('',*,*,#2602,.F.);
#2604=ORIENTED_EDGE('',*,*,#691,.T.);
#2605=DIRECTION('',(-1.,0.,0.));
#2606=VECTOR('',#2605,1.);
#2607=CARTESIAN_POINT('',(6.,-18.4287050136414,-4.62415738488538));
#2608=LINE('',#2607,#2606);
#2609=EDGE_CURVE('E1378',#1668,#686,#2608,.F.);
#2610=ORIENTED_EDGE('',*,*,#2609,.F.);
#2611=ORIENTED_EDGE('',*,*,#1669,.F.);
#2612=EDGE_LOOP('',(#2603,#2604,#2610,#2611));
#2613=FACE_BOUND('',#2612,.T.);
#2614=ADVANCED_FACE('F3299',(#2613),#2325,.T.);
#2615=DIRECTION('',(-1.,0.,0.));
#2616=VECTOR('',#2615,1.);
#2617=CARTESIAN_POINT('',(6.,-18.898873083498,-1.9577017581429));
#2618=LINE('',#2617,#2616);
#2619=EDGE_CURVE('E1376',#659,#1695,#2618,.T.);
#2620=ORIENTED_EDGE('',*,*,#2619,.F.);
#2621=ORIENTED_EDGE('',*,*,#660,.T.);
#2622=DIRECTION('',(-1.,0.,0.));
#2623=VECTOR('',#2622,1.);
#2624=CARTESIAN_POINT('',(6.,-18.9517080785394,-1.35379500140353));
#2625=LINE('',#2624,#2623);
#2626=EDGE_CURVE('E1356',#1699,#655,#2625,.F.);
#2627=ORIENTED_EDGE('',*,*,#2626,.F.);
#2628=ORIENTED_EDGE('',*,*,#1700,.F.);
#2629=EDGE_LOOP('',(#2620,#2621,#2627,#2628));
#2630=FACE_BOUND('',#2629,.T.);
#2631=ADVANCED_FACE('F3292',(#2630),#2325,.T.);
#2632=DIRECTION('',(-1.,0.,0.));
#2633=VECTOR('',#2632,1.);
#2634=CARTESIAN_POINT('',(6.,-18.9517080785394,1.35379500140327));
#2635=LINE('',#2634,#2633);
#2636=EDGE_CURVE('E1354',#628,#1726,#2635,.T.);
#2637=ORIENTED_EDGE('',*,*,#2636,.F.);
#2638=ORIENTED_EDGE('',*,*,#629,.T.);
#2639=DIRECTION('',(-1.,0.,0.));
#2640=VECTOR('',#2639,1.);
#2641=CARTESIAN_POINT('',(6.,-18.898873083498,1.95770175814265));
#2642=LINE('',#2641,#2640);
#2643=EDGE_CURVE('E1334',#1730,#624,#2642,.F.);
#2644=ORIENTED_EDGE('',*,*,#2643,.F.);
#2645=ORIENTED_EDGE('',*,*,#1731,.F.);
#2646=EDGE_LOOP('',(#2637,#2638,#2644,#2645));
#2647=FACE_BOUND('',#2646,.T.);
#2648=ADVANCED_FACE('F3285',(#2647),#2325,.T.);
#2649=DIRECTION('',(-1.,0.,0.));
#2650=VECTOR('',#2649,1.);
#2651=CARTESIAN_POINT('',(6.,-18.4287050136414,4.62415738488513));
#2652=LINE('',#2651,#2650);
#2653=EDGE_CURVE('E1332',#597,#1757,#2652,.T.);
#2654=ORIENTED_EDGE('',*,*,#2653,.F.);
#2655=ORIENTED_EDGE('',*,*,#598,.T.);
#2656=DIRECTION('',(-1.,0.,0.));
#2657=VECTOR('',#2656,1.);
#2658=CARTESIAN_POINT('',(6.,-18.2718053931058,5.20971474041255));
#2659=LINE('',#2658,#2657);
#2660=EDGE_CURVE('E1312',#1761,#593,#2659,.F.);
#2661=ORIENTED_EDGE('',*,*,#2660,.F.);
#2662=ORIENTED_EDGE('',*,*,#1762,.F.);
#2663=EDGE_LOOP('',(#2654,#2655,#2661,#2662));
#2664=FACE_BOUND('',#2663,.T.);
#2665=ADVANCED_FACE('F3278',(#2664),#2325,.T.);
#2666=DIRECTION('',(-1.,0.,0.));
#2667=VECTOR('',#2666,1.);
#2668=CARTESIAN_POINT('',(6.,-17.3457550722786,7.75401708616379));
#2669=LINE('',#2668,#2667);
#2670=EDGE_CURVE('E1310',#566,#1788,#2669,.T.);
#2671=ORIENTED_EDGE('',*,*,#2670,.F.);
#2672=ORIENTED_EDGE('',*,*,#567,.T.);
#2673=DIRECTION('',(-1.,0.,0.));
#2674=VECTOR('',#2673,1.);
#2675=CARTESIAN_POINT('',(6.,-17.0895581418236,8.30343317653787));
#2676=LINE('',#2675,#2674);
#2677=EDGE_CURVE('E1290',#1792,#562,#2676,.F.);
#2678=ORIENTED_EDGE('',*,*,#2677,.F.);
#2679=ORIENTED_EDGE('',*,*,#1793,.F.);
#2680=EDGE_LOOP('',(#2671,#2672,#2678,#2679));
#2681=FACE_BOUND('',#2680,.T.);
#2682=ADVANCED_FACE('F3271',(#2681),#2325,.T.);
#2683=DIRECTION('',(-1.,0.,0.));
#2684=VECTOR('',#2683,1.);
#2685=CARTESIAN_POINT('',(6.,-15.7357631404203,10.6482749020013));
#2686=LINE('',#2685,#2684);
#2687=EDGE_CURVE('E1288',#535,#1819,#2686,.T.);
#2688=ORIENTED_EDGE('',*,*,#2687,.F.);
#2689=ORIENTED_EDGE('',*,*,#536,.T.);
#2690=DIRECTION('',(-1.,0.,0.));
#2691=VECTOR('',#2690,1.);
#2692=CARTESIAN_POINT('',(6.,-15.3880533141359,11.144855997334));
#2693=LINE('',#2692,#2691);
#2694=EDGE_CURVE('E1268',#1823,#531,#2693,.F.);
#2695=ORIENTED_EDGE('',*,*,#2694,.F.);
#2696=ORIENTED_EDGE('',*,*,#1824,.F.);
#2697=EDGE_LOOP('',(#2688,#2689,#2695,#2696));
#2698=FACE_BOUND('',#2697,.T.);
#2699=ADVANCED_FACE('F3264',(#2698),#2325,.T.);
#2700=DIRECTION('',(-1.,0.,0.));
#2701=VECTOR('',#2700,1.);
#2702=CARTESIAN_POINT('',(6.,-13.6476480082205,13.2189902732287));
#2703=LINE('',#2702,#2701);
#2704=EDGE_CURVE('E1266',#504,#1850,#2703,.T.);
#2705=ORIENTED_EDGE('',*,*,#2704,.F.);
#2706=ORIENTED_EDGE('',*,*,#505,.T.);
#2707=DIRECTION('',(-1.,0.,0.));
#2708=VECTOR('',#2707,1.);
#2709=CARTESIAN_POINT('',(6.,-13.2189902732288,13.6476480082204));
#2710=LINE('',#2709,#2708);
#2711=EDGE_CURVE('E1246',#1854,#500,#2710,.F.);
#2712=ORIENTED_EDGE('',*,*,#2711,.F.);
#2713=ORIENTED_EDGE('',*,*,#1855,.F.);
#2714=EDGE_LOOP('',(#2705,#2706,#2712,#2713));
#2715=FACE_BOUND('',#2714,.T.);
#2716=ADVANCED_FACE('F3257',(#2715),#2325,.T.);
#2717=DIRECTION('',(-1.,0.,0.));
#2718=VECTOR('',#2717,1.);
#2719=CARTESIAN_POINT('',(6.,-11.1448559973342,15.3880533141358));
#2720=LINE('',#2719,#2718);
#2721=EDGE_CURVE('E1244',#473,#1881,#2720,.T.);
#2722=ORIENTED_EDGE('',*,*,#2721,.F.);
#2723=ORIENTED_EDGE('',*,*,#474,.T.);
#2724=DIRECTION('',(-1.,0.,0.));
#2725=VECTOR('',#2724,1.);
#2726=CARTESIAN_POINT('',(6.,-10.6482749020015,15.7357631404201));
#2727=LINE('',#2726,#2725);
#2728=EDGE_CURVE('E1224',#1885,#469,#2727,.F.);
#2729=ORIENTED_EDGE('',*,*,#2728,.F.);
#2730=ORIENTED_EDGE('',*,*,#1886,.F.);
#2731=EDGE_LOOP('',(#2722,#2723,#2729,#2730));
#2732=FACE_BOUND('',#2731,.T.);
#2733=ADVANCED_FACE('F3250',(#2732),#2325,.T.);
#2734=DIRECTION('',(-1.,0.,0.));
#2735=VECTOR('',#2734,1.);
#2736=CARTESIAN_POINT('',(6.,-8.30343317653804,17.0895581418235));
#2737=LINE('',#2736,#2735);
#2738=EDGE_CURVE('E1222',#442,#1912,#2737,.T.);
#2739=ORIENTED_EDGE('',*,*,#2738,.F.);
#2740=ORIENTED_EDGE('',*,*,#443,.T.);
#2741=DIRECTION('',(-1.,0.,0.));
#2742=VECTOR('',#2741,1.);
#2743=CARTESIAN_POINT('',(6.,-7.75401708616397,17.3457550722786));
#2744=LINE('',#2743,#2742);
#2745=EDGE_CURVE('E1202',#1916,#438,#2744,.F.);
#2746=ORIENTED_EDGE('',*,*,#2745,.F.);
#2747=ORIENTED_EDGE('',*,*,#1917,.F.);
#2748=EDGE_LOOP('',(#2739,#2740,#2746,#2747));
#2749=FACE_BOUND('',#2748,.T.);
#2750=ADVANCED_FACE('F3243',(#2749),#2325,.T.);
#2751=DIRECTION('',(-1.,0.,0.));
#2752=VECTOR('',#2751,1.);
#2753=CARTESIAN_POINT('',(6.,-5.20971474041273,18.2718053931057));
#2754=LINE('',#2753,#2752);
#2755=EDGE_CURVE('E1200',#411,#1943,#2754,.T.);
#2756=ORIENTED_EDGE('',*,*,#2755,.F.);
#2757=ORIENTED_EDGE('',*,*,#412,.T.);
#2758=DIRECTION('',(-1.,0.,0.));
#2759=VECTOR('',#2758,1.);
#2760=CARTESIAN_POINT('',(6.,-4.62415738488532,18.4287050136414));
#2761=LINE('',#2760,#2759);
#2762=EDGE_CURVE('E1180',#1947,#407,#2761,.F.);
#2763=ORIENTED_EDGE('',*,*,#2762,.F.);
#2764=ORIENTED_EDGE('',*,*,#1948,.F.);
#2765=EDGE_LOOP('',(#2756,#2757,#2763,#2764));
#2766=FACE_BOUND('',#2765,.T.);
#2767=ADVANCED_FACE('F3236',(#2766),#2325,.T.);
#2768=DIRECTION('',(-1.,0.,0.));
#2769=VECTOR('',#2768,1.);
#2770=CARTESIAN_POINT('',(6.,-1.95770175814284,18.898873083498));
#2771=LINE('',#2770,#2769);
#2772=EDGE_CURVE('E1178',#380,#1974,#2771,.T.);
#2773=ORIENTED_EDGE('',*,*,#2772,.F.);
#2774=ORIENTED_EDGE('',*,*,#381,.T.);
#2775=DIRECTION('',(-1.,0.,0.));
#2776=VECTOR('',#2775,1.);
#2777=CARTESIAN_POINT('',(6.,-1.35379500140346,18.9517080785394));
#2778=LINE('',#2777,#2776);
#2779=EDGE_CURVE('E1158',#1978,#376,#2778,.F.);
#2780=ORIENTED_EDGE('',*,*,#2779,.F.);
#2781=ORIENTED_EDGE('',*,*,#1979,.F.);
#2782=EDGE_LOOP('',(#2773,#2774,#2780,#2781));
#2783=FACE_BOUND('',#2782,.T.);
#2784=ADVANCED_FACE('F3229',(#2783),#2325,.T.);
#2785=DIRECTION('',(-1.,0.,0.));
#2786=VECTOR('',#2785,1.);
#2787=CARTESIAN_POINT('',(6.,1.35379500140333,18.9517080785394));
#2788=LINE('',#2787,#2786);
#2789=EDGE_CURVE('E1156',#349,#2005,#2788,.T.);
#2790=ORIENTED_EDGE('',*,*,#2789,.F.);
#2791=ORIENTED_EDGE('',*,*,#350,.T.);
#2792=DIRECTION('',(-1.,0.,0.));
#2793=VECTOR('',#2792,1.);
#2794=CARTESIAN_POINT('',(6.,1.95770175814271,18.898873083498));
#2795=LINE('',#2794,#2793);
#2796=EDGE_CURVE('E1136',#2009,#345,#2795,.F.);
#2797=ORIENTED_EDGE('',*,*,#2796,.F.);
#2798=ORIENTED_EDGE('',*,*,#2010,.F.);
#2799=EDGE_LOOP('',(#2790,#2791,#2797,#2798));
#2800=FACE_BOUND('',#2799,.T.);
#2801=ADVANCED_FACE('F3222',(#2800),#2325,.T.);
#2802=DIRECTION('',(-1.,0.,0.));
#2803=VECTOR('',#2802,1.);
#2804=CARTESIAN_POINT('',(6.,4.62415738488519,18.4287050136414));
#2805=LINE('',#2804,#2803);
#2806=EDGE_CURVE('E1134',#318,#2036,#2805,.T.);
#2807=ORIENTED_EDGE('',*,*,#2806,.F.);
#2808=ORIENTED_EDGE('',*,*,#319,.T.);
#2809=DIRECTION('',(-1.,0.,0.));
#2810=VECTOR('',#2809,1.);
#2811=CARTESIAN_POINT('',(6.,5.20971474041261,18.2718053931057));
#2812=LINE('',#2811,#2810);
#2813=EDGE_CURVE('E1114',#2040,#314,#2812,.F.);
#2814=ORIENTED_EDGE('',*,*,#2813,.F.);
#2815=ORIENTED_EDGE('',*,*,#2041,.F.);
#2816=EDGE_LOOP('',(#2807,#2808,#2814,#2815));
#2817=FACE_BOUND('',#2816,.T.);
#2818=ADVANCED_FACE('F3215',(#2817),#2325,.T.);
#2819=DIRECTION('',(-1.,0.,0.));
#2820=VECTOR('',#2819,1.);
#2821=CARTESIAN_POINT('',(6.,7.75401708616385,17.3457550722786));
#2822=LINE('',#2821,#2820);
#2823=EDGE_CURVE('E1112',#287,#2067,#2822,.T.);
#2824=ORIENTED_EDGE('',*,*,#2823,.F.);
#2825=ORIENTED_EDGE('',*,*,#288,.T.);
#2826=DIRECTION('',(-1.,0.,0.));
#2827=VECTOR('',#2826,1.);
#2828=CARTESIAN_POINT('',(6.,8.30343317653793,17.0895581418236));
#2829=LINE('',#2828,#2827);
#2830=EDGE_CURVE('E1092',#2071,#283,#2829,.F.);
#2831=ORIENTED_EDGE('',*,*,#2830,.F.);
#2832=ORIENTED_EDGE('',*,*,#2072,.F.);
#2833=EDGE_LOOP('',(#2824,#2825,#2831,#2832));
#2834=FACE_BOUND('',#2833,.T.);
#2835=ADVANCED_FACE('F3208',(#2834),#2325,.T.);
#2836=DIRECTION('',(-1.,0.,0.));
#2837=VECTOR('',#2836,1.);
#2838=CARTESIAN_POINT('',(6.,10.6482749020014,15.7357631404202));
#2839=LINE('',#2838,#2837);
#2840=EDGE_CURVE('E1090',#256,#2098,#2839,.T.);
#2841=ORIENTED_EDGE('',*,*,#2840,.F.);
#2842=ORIENTED_EDGE('',*,*,#257,.T.);
#2843=DIRECTION('',(-1.,0.,0.));
#2844=VECTOR('',#2843,1.);
#2845=CARTESIAN_POINT('',(6.,11.1448559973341,15.3880533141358));
#2846=LINE('',#2845,#2844);
#2847=EDGE_CURVE('E1070',#2102,#252,#2846,.F.);
#2848=ORIENTED_EDGE('',*,*,#2847,.F.);
#2849=ORIENTED_EDGE('',*,*,#2103,.F.);
#2850=EDGE_LOOP('',(#2841,#2842,#2848,#2849));
#2851=FACE_BOUND('',#2850,.T.);
#2852=ADVANCED_FACE('F3201',(#2851),#2325,.T.);
#2853=DIRECTION('',(-1.,0.,0.));
#2854=VECTOR('',#2853,1.);
#2855=CARTESIAN_POINT('',(6.,13.2189902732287,13.6476480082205));
#2856=LINE('',#2855,#2854);
#2857=EDGE_CURVE('E1068',#225,#2129,#2856,.T.);
#2858=ORIENTED_EDGE('',*,*,#2857,.F.);
#2859=ORIENTED_EDGE('',*,*,#226,.T.);
#2860=DIRECTION('',(-1.,0.,0.));
#2861=VECTOR('',#2860,1.);
#2862=CARTESIAN_POINT('',(6.,13.6476480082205,13.2189902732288));
#2863=LINE('',#2862,#2861);
#2864=EDGE_CURVE('E1048',#2133,#221,#2863,.F.);
#2865=ORIENTED_EDGE('',*,*,#2864,.F.);
#2866=ORIENTED_EDGE('',*,*,#2134,.F.);
#2867=EDGE_LOOP('',(#2858,#2859,#2865,#2866));
#2868=FACE_BOUND('',#2867,.T.);
#2869=ADVANCED_FACE('F3194',(#2868),#2325,.T.);
#2870=DIRECTION('',(-1.,0.,0.));
#2871=VECTOR('',#2870,1.);
#2872=CARTESIAN_POINT('',(6.,15.3880533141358,11.1448559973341));
#2873=LINE('',#2872,#2871);
#2874=EDGE_CURVE('E1046',#194,#2160,#2873,.T.);
#2875=ORIENTED_EDGE('',*,*,#2874,.F.);
#2876=ORIENTED_EDGE('',*,*,#195,.T.);
#2877=DIRECTION('',(-1.,0.,0.));
#2878=VECTOR('',#2877,1.);
#2879=CARTESIAN_POINT('',(6.,15.7357631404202,10.6482749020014));
#2880=LINE('',#2879,#2878);
#2881=EDGE_CURVE('E1026',#2164,#190,#2880,.F.);
#2882=ORIENTED_EDGE('',*,*,#2881,.F.);
#2883=ORIENTED_EDGE('',*,*,#2165,.F.);
#2884=EDGE_LOOP('',(#2875,#2876,#2882,#2883));
#2885=FACE_BOUND('',#2884,.T.);
#2886=ADVANCED_FACE('F3186',(#2885),#2325,.T.);
#2887=DIRECTION('',(-1.,0.,0.));
#2888=VECTOR('',#2887,1.);
#2889=CARTESIAN_POINT('',(6.,17.0895581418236,8.30343317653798));
#2890=LINE('',#2889,#2888);
#2891=EDGE_CURVE('E1024',#163,#2191,#2890,.T.);
#2892=ORIENTED_EDGE('',*,*,#2891,.F.);
#2893=ORIENTED_EDGE('',*,*,#164,.T.);
#2894=DIRECTION('',(-1.,0.,0.));
#2895=VECTOR('',#2894,1.);
#2896=CARTESIAN_POINT('',(6.,17.3457550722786,7.75401708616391));
#2897=LINE('',#2896,#2895);
#2898=EDGE_CURVE('E1004',#2195,#159,#2897,.F.);
#2899=ORIENTED_EDGE('',*,*,#2898,.F.);
#2900=ORIENTED_EDGE('',*,*,#2196,.F.);
#2901=EDGE_LOOP('',(#2892,#2893,#2899,#2900));
#2902=FACE_BOUND('',#2901,.T.);
#2903=ADVANCED_FACE('F1772',(#2902),#2325,.T.);
#2904=DIRECTION('',(-1.,0.,0.));
#2905=VECTOR('',#2904,1.);
#2906=CARTESIAN_POINT('',(6.,18.2718053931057,5.20971474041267));
#2907=LINE('',#2906,#2905);
#2908=EDGE_CURVE('E1002',#132,#2222,#2907,.T.);
#2909=ORIENTED_EDGE('',*,*,#2908,.F.);
#2910=ORIENTED_EDGE('',*,*,#133,.T.);
#2911=DIRECTION('',(-1.,0.,0.));
#2912=VECTOR('',#2911,1.);
#2913=CARTESIAN_POINT('',(6.,18.4287050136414,4.62415738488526));
#2914=LINE('',#2913,#2912);
#2915=EDGE_CURVE('E983',#2226,#128,#2914,.F.);
#2916=ORIENTED_EDGE('',*,*,#2915,.F.);
#2917=ORIENTED_EDGE('',*,*,#2227,.F.);
#2918=EDGE_LOOP('',(#2909,#2910,#2916,#2917));
#2919=FACE_BOUND('',#2918,.T.);
#2920=ADVANCED_FACE('F1765',(#2919),#2325,.T.);
#2921=DIRECTION('',(-1.,0.,0.));
#2922=VECTOR('',#2921,1.);
#2923=CARTESIAN_POINT('',(6.,18.898873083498,1.95770175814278));
#2924=LINE('',#2923,#2922);
#2925=EDGE_CURVE('E981',#101,#2253,#2924,.T.);
#2926=ORIENTED_EDGE('',*,*,#2925,.F.);
#2927=ORIENTED_EDGE('',*,*,#102,.T.);
#2928=DIRECTION('',(-1.,0.,0.));
#2929=VECTOR('',#2928,1.);
#2930=CARTESIAN_POINT('',(6.,18.9517080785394,1.3537950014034));
#2931=LINE('',#2930,#2929);
#2932=EDGE_CURVE('E962',#2257,#97,#2931,.F.);
#2933=ORIENTED_EDGE('',*,*,#2932,.F.);
#2934=ORIENTED_EDGE('',*,*,#2258,.F.);
#2935=EDGE_LOOP('',(#2926,#2927,#2933,#2934));
#2936=FACE_BOUND('',#2935,.T.);
#2937=ADVANCED_FACE('F1759',(#2936),#2325,.T.);
#2938=CARTESIAN_POINT('',(12.,15.1702468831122,-7.48082945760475));
#2939=DIRECTION('',(-1.,0.,0.));
#2940=DIRECTION('',(0.,0.,1.));
#2941=AXIS2_PLACEMENT_3D('',#2938,#2939,#2940);
#2942=CYLINDRICAL_SURFACE('',#2941,7.2);
#2943=ORIENTED_EDGE('',*,*,#2354,.T.);
#2944=ORIENTED_EDGE('',*,*,#2285,.F.);
#2945=DIRECTION('',(-1.,0.,0.));
#2946=VECTOR('',#2945,1.);
#2947=CARTESIAN_POINT('',(12.,16.7428277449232,-0.454664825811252));
#2948=LINE('',#2947,#2946);
#2949=EDGE_CURVE('E969',#79,#2275,#2948,.T.);
#2950=ORIENTED_EDGE('',*,*,#2949,.F.);
#2951=ORIENTED_EDGE('',*,*,#80,.T.);
#2952=EDGE_LOOP('',(#2943,#2944,#2950,#2951));
#2953=FACE_BOUND('',#2952,.T.);
#2954=ADVANCED_FACE('F1762',(#2953),#2942,.T.);
#2955=CARTESIAN_POINT('',(12.,15.1702468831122,7.48082945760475));
#2956=DIRECTION('',(-1.,0.,0.));
#2957=DIRECTION('',(0.,0.,1.));
#2958=AXIS2_PLACEMENT_3D('',#2955,#2956,#2957);
#2959=CYLINDRICAL_SURFACE('',#2958,7.2);
#2960=ORIENTED_EDGE('',*,*,#2932,.T.);
#2961=ORIENTED_EDGE('',*,*,#98,.T.);
#2962=DIRECTION('',(-1.,0.,0.));
#2963=VECTOR('',#2962,1.);
#2964=CARTESIAN_POINT('',(12.,16.7428277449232,0.454664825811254));
#2965=LINE('',#2964,#2963);
#2966=EDGE_CURVE('E965',#88,#2266,#2965,.T.);
#2967=ORIENTED_EDGE('',*,*,#2966,.T.);
#2968=ORIENTED_EDGE('',*,*,#2267,.T.);
#2969=EDGE_LOOP('',(#2960,#2961,#2967,#2968));
#2970=FACE_BOUND('',#2969,.T.);
#2971=ADVANCED_FACE('F1771',(#2970),#2959,.T.);
#2972=CARTESIAN_POINT('',(12.,0.,0.));
#2973=DIRECTION('',(-1.,0.,0.));
#2974=DIRECTION('',(0.,0.,1.));
#2975=AXIS2_PLACEMENT_3D('',#2972,#2973,#2974);
#2976=CYLINDRICAL_SURFACE('',#2975,16.749);
#2977=ORIENTED_EDGE('',*,*,#2276,.F.);
#2978=ORIENTED_EDGE('',*,*,#2966,.F.);
#2979=ORIENTED_EDGE('',*,*,#89,.T.);
#2980=ORIENTED_EDGE('',*,*,#2949,.T.);
#2981=EDGE_LOOP('',(#2977,#2978,#2979,#2980));
#2982=FACE_BOUND('',#2981,.T.);
#2983=ADVANCED_FACE('F1790',(#2982),#2976,.T.);
#2984=CARTESIAN_POINT('',(12.,16.2388091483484,-4.73289312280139));
#2985=DIRECTION('',(-1.,0.,0.));
#2986=DIRECTION('',(0.,0.,1.));
#2987=AXIS2_PLACEMENT_3D('',#2984,#2985,#2986);
#2988=CYLINDRICAL_SURFACE('',#2987,7.2);
#2989=ORIENTED_EDGE('',*,*,#2925,.T.);
#2990=ORIENTED_EDGE('',*,*,#2254,.F.);
#2991=DIRECTION('',(-1.,0.,0.));
#2992=VECTOR('',#2991,1.);
#2993=CARTESIAN_POINT('',(12.,16.5674182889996,2.45960408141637));
#2994=LINE('',#2993,#2992);
#2995=EDGE_CURVE('E988',#110,#2244,#2994,.T.);
#2996=ORIENTED_EDGE('',*,*,#2995,.F.);
#2997=ORIENTED_EDGE('',*,*,#111,.T.);
#2998=EDGE_LOOP('',(#2989,#2990,#2996,#2997));
#2999=FACE_BOUND('',#2998,.T.);
#3000=ADVANCED_FACE('F2081',(#2999),#2988,.T.);
#3001=CARTESIAN_POINT('',(12.,13.6407443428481,10.0014645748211));
#3002=DIRECTION('',(-1.,0.,0.));
#3003=DIRECTION('',(0.,0.,1.));
#3004=AXIS2_PLACEMENT_3D('',#3001,#3002,#3003);
#3005=CYLINDRICAL_SURFACE('',#3004,7.2);
#3006=ORIENTED_EDGE('',*,*,#2915,.T.);
#3007=ORIENTED_EDGE('',*,*,#129,.T.);
#3008=DIRECTION('',(-1.,0.,0.));
#3009=VECTOR('',#3008,1.);
#3010=CARTESIAN_POINT('',(12.,16.4095148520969,3.35511897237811));
#3011=LINE('',#3010,#3009);
#3012=EDGE_CURVE('E986',#119,#2235,#3011,.T.);
#3013=ORIENTED_EDGE('',*,*,#3012,.T.);
#3014=ORIENTED_EDGE('',*,*,#2236,.T.);
#3015=EDGE_LOOP('',(#3006,#3007,#3013,#3014));
#3016=FACE_BOUND('',#3015,.T.);
#3017=ADVANCED_FACE('F2074',(#3016),#3005,.T.);
#3018=CARTESIAN_POINT('',(12.,0.,0.));
#3019=DIRECTION('',(-1.,0.,0.));
#3020=DIRECTION('',(0.,0.,1.));
#3021=AXIS2_PLACEMENT_3D('',#3018,#3019,#3020);
#3022=CYLINDRICAL_SURFACE('',#3021,16.749);
#3023=ORIENTED_EDGE('',*,*,#2245,.F.);
#3024=ORIENTED_EDGE('',*,*,#3012,.F.);
#3025=ORIENTED_EDGE('',*,*,#120,.T.);
#3026=ORIENTED_EDGE('',*,*,#2995,.T.);
#3027=EDGE_LOOP('',(#3023,#3024,#3025,#3026));
#3028=FACE_BOUND('',#3027,.T.);
#3029=ADVANCED_FACE('F2080',(#3028),#3022,.T.);
#3030=CARTESIAN_POINT('',(12.,16.8139634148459,-1.8411502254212));
#3031=DIRECTION('',(-1.,0.,0.));
#3032=DIRECTION('',(0.,0.,1.));
#3033=AXIS2_PLACEMENT_3D('',#3030,#3031,#3032);
#3034=CYLINDRICAL_SURFACE('',#3033,7.2);
#3035=ORIENTED_EDGE('',*,*,#2908,.T.);
#3036=ORIENTED_EDGE('',*,*,#2223,.F.);
#3037=DIRECTION('',(-1.,0.,0.));
#3038=VECTOR('',#3037,1.);
#3039=CARTESIAN_POINT('',(12.,15.888616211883,5.29913916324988));
#3040=LINE('',#3039,#3038);
#3041=EDGE_CURVE('E1009',#141,#2213,#3040,.T.);
#3042=ORIENTED_EDGE('',*,*,#3041,.F.);
#3043=ORIENTED_EDGE('',*,*,#142,.T.);
#3044=EDGE_LOOP('',(#3035,#3036,#3042,#3043));
#3045=FACE_BOUND('',#3044,.T.);
#3046=ADVANCED_FACE('F2086',(#3045),#3034,.T.);
#3047=CARTESIAN_POINT('',(12.,11.6967746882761,12.2182102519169));
#3048=DIRECTION('',(-1.,0.,0.));
#3049=DIRECTION('',(0.,0.,1.));
#3050=AXIS2_PLACEMENT_3D('',#3047,#3048,#3049);
#3051=CYLINDRICAL_SURFACE('',#3050,7.2);
#3052=ORIENTED_EDGE('',*,*,#2898,.T.);
#3053=ORIENTED_EDGE('',*,*,#160,.T.);
#3054=DIRECTION('',(-1.,0.,0.));
#3055=VECTOR('',#3054,1.);
#3056=CARTESIAN_POINT('',(12.,15.5776071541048,6.15362952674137));
#3057=LINE('',#3056,#3055);
#3058=EDGE_CURVE('E1007',#150,#2204,#3057,.T.);
#3059=ORIENTED_EDGE('',*,*,#3058,.T.);
#3060=ORIENTED_EDGE('',*,*,#2205,.T.);
#3061=EDGE_LOOP('',(#3052,#3053,#3059,#3060));
#3062=FACE_BOUND('',#3061,.T.);
#3063=ADVANCED_FACE('F2094',(#3062),#3051,.T.);
#3064=CARTESIAN_POINT('',(12.,0.,0.));
#3065=DIRECTION('',(-1.,0.,0.));
#3066=DIRECTION('',(0.,0.,1.));
#3067=AXIS2_PLACEMENT_3D('',#3064,#3065,#3066);
#3068=CYLINDRICAL_SURFACE('',#3067,16.749);
#3069=ORIENTED_EDGE('',*,*,#2214,.F.);
#3070=ORIENTED_EDGE('',*,*,#3058,.F.);
#3071=ORIENTED_EDGE('',*,*,#151,.T.);
#3072=ORIENTED_EDGE('',*,*,#3041,.T.);
#3073=EDGE_LOOP('',(#3069,#3070,#3071,#3072));
#3074=FACE_BOUND('',#3073,.T.);
#3075=ADVANCED_FACE('F2088',(#3074),#3068,.T.);
#3076=CARTESIAN_POINT('',(12.,16.8782339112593,1.10653508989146));
#3077=DIRECTION('',(-1.,0.,0.));
#3078=DIRECTION('',(0.,0.,1.));
#3079=AXIS2_PLACEMENT_3D('',#3076,#3077,#3078);
#3080=CYLINDRICAL_SURFACE('',#3079,7.2);
#3081=ORIENTED_EDGE('',*,*,#2891,.T.);
#3082=ORIENTED_EDGE('',*,*,#2192,.F.);
#3083=DIRECTION('',(-1.,0.,0.));
#3084=VECTOR('',#3083,1.);
#3085=CARTESIAN_POINT('',(12.,14.727046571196,7.97766258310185));
#3086=LINE('',#3085,#3084);
#3087=EDGE_CURVE('E1031',#172,#2182,#3086,.T.);
#3088=ORIENTED_EDGE('',*,*,#3087,.F.);
#3089=ORIENTED_EDGE('',*,*,#173,.T.);
#3090=EDGE_LOOP('',(#3081,#3082,#3088,#3089));
#3091=FACE_BOUND('',#3090,.T.);
#3092=ADVANCED_FACE('F2587',(#3091),#3080,.T.);
#3093=CARTESIAN_POINT('',(12.,9.3974044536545,14.0637117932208));
#3094=DIRECTION('',(-1.,0.,0.));
#3095=DIRECTION('',(0.,0.,1.));
#3096=AXIS2_PLACEMENT_3D('',#3093,#3094,#3095);
#3097=CYLINDRICAL_SURFACE('',#3096,7.2);
#3098=ORIENTED_EDGE('',*,*,#2881,.T.);
#3099=ORIENTED_EDGE('',*,*,#191,.T.);
#3100=DIRECTION('',(-1.,0.,0.));
#3101=VECTOR('',#3100,1.);
#3102=CARTESIAN_POINT('',(12.,14.2723817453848,8.76516516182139));
#3103=LINE('',#3102,#3101);
#3104=EDGE_CURVE('E1029',#181,#2173,#3103,.T.);
#3105=ORIENTED_EDGE('',*,*,#3104,.T.);
#3106=ORIENTED_EDGE('',*,*,#2174,.T.);
#3107=EDGE_LOOP('',(#3098,#3099,#3105,#3106));
#3108=FACE_BOUND('',#3107,.T.);
#3109=ADVANCED_FACE('F2583',(#3108),#3097,.T.);
#3110=CARTESIAN_POINT('',(12.,0.,0.));
#3111=DIRECTION('',(-1.,0.,0.));
#3112=DIRECTION('',(0.,0.,1.));
#3113=AXIS2_PLACEMENT_3D('',#3110,#3111,#3112);
#3114=CYLINDRICAL_SURFACE('',#3113,16.749);
#3115=ORIENTED_EDGE('',*,*,#2183,.F.);
#3116=ORIENTED_EDGE('',*,*,#3104,.F.);
#3117=ORIENTED_EDGE('',*,*,#182,.T.);
#3118=ORIENTED_EDGE('',*,*,#3087,.T.);
#3119=EDGE_LOOP('',(#3115,#3116,#3117,#3118));
#3120=FACE_BOUND('',#3119,.T.);
#3121=ADVANCED_FACE('F2579',(#3120),#3114,.T.);
#3122=CARTESIAN_POINT('',(12.,16.4296678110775,4.02059889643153));
#3123=DIRECTION('',(-1.,0.,0.));
#3124=DIRECTION('',(0.,0.,1.));
#3125=AXIS2_PLACEMENT_3D('',#3122,#3123,#3124);
#3126=CYLINDRICAL_SURFACE('',#3125,7.2);
#3127=ORIENTED_EDGE('',*,*,#2874,.T.);
#3128=ORIENTED_EDGE('',*,*,#2161,.F.);
#3129=DIRECTION('',(-1.,0.,0.));
#3130=VECTOR('',#3129,1.);
#3131=CARTESIAN_POINT('',(12.,13.1180030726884,10.4137887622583));
#3132=LINE('',#3131,#3130);
#3133=EDGE_CURVE('E1053',#203,#2151,#3132,.T.);
#3134=ORIENTED_EDGE('',*,*,#3133,.F.);
#3135=ORIENTED_EDGE('',*,*,#204,.T.);
#3136=EDGE_LOOP('',(#3127,#3128,#3134,#3135));
#3137=FACE_BOUND('',#3136,.T.);
#3138=ADVANCED_FACE('F2575',(#3137),#3126,.T.);
#3139=CARTESIAN_POINT('',(12.,6.8124988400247,15.4818945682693));
#3140=DIRECTION('',(-1.,0.,0.));
#3141=DIRECTION('',(0.,0.,1.));
#3142=AXIS2_PLACEMENT_3D('',#3139,#3140,#3141);
#3143=CYLINDRICAL_SURFACE('',#3142,7.2);
#3144=ORIENTED_EDGE('',*,*,#2864,.T.);
#3145=ORIENTED_EDGE('',*,*,#222,.T.);
#3146=DIRECTION('',(-1.,0.,0.));
#3147=VECTOR('',#3146,1.);
#3148=CARTESIAN_POINT('',(12.,12.5334972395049,11.110375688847));
#3149=LINE('',#3148,#3147);
#3150=EDGE_CURVE('E1051',#212,#2142,#3149,.T.);
#3151=ORIENTED_EDGE('',*,*,#3150,.T.);
#3152=ORIENTED_EDGE('',*,*,#2143,.T.);
#3153=EDGE_LOOP('',(#3144,#3145,#3151,#3152));
#3154=FACE_BOUND('',#3153,.T.);
#3155=ADVANCED_FACE('F2571',(#3154),#3143,.T.);
#3156=CARTESIAN_POINT('',(12.,0.,0.));
#3157=DIRECTION('',(-1.,0.,0.));
#3158=DIRECTION('',(0.,0.,1.));
#3159=AXIS2_PLACEMENT_3D('',#3156,#3157,#3158);
#3160=CYLINDRICAL_SURFACE('',#3159,16.749);
#3161=ORIENTED_EDGE('',*,*,#2152,.F.);
#3162=ORIENTED_EDGE('',*,*,#3150,.F.);
#3163=ORIENTED_EDGE('',*,*,#213,.T.);
#3164=ORIENTED_EDGE('',*,*,#3133,.T.);
#3165=EDGE_LOOP('',(#3161,#3162,#3163,#3164));
#3166=FACE_BOUND('',#3165,.T.);
#3167=ADVANCED_FACE('F2567',(#3166),#3160,.T.);
#3168=CARTESIAN_POINT('',(12.,15.4818945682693,6.81249884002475));
#3169=DIRECTION('',(-1.,0.,0.));
#3170=DIRECTION('',(0.,0.,1.));
#3171=AXIS2_PLACEMENT_3D('',#3168,#3169,#3170);
#3172=CYLINDRICAL_SURFACE('',#3171,7.2);
#3173=ORIENTED_EDGE('',*,*,#2857,.T.);
#3174=ORIENTED_EDGE('',*,*,#2130,.F.);
#3175=DIRECTION('',(-1.,0.,0.));
#3176=VECTOR('',#3175,1.);
#3177=CARTESIAN_POINT('',(12.,11.110375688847,12.5334972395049));
#3178=LINE('',#3177,#3176);
#3179=EDGE_CURVE('E1075',#234,#2120,#3178,.T.);
#3180=ORIENTED_EDGE('',*,*,#3179,.F.);
#3181=ORIENTED_EDGE('',*,*,#235,.T.);
#3182=EDGE_LOOP('',(#3173,#3174,#3180,#3181));
#3183=FACE_BOUND('',#3182,.T.);
#3184=ADVANCED_FACE('F2563',(#3183),#3172,.T.);
#3185=CARTESIAN_POINT('',(12.,4.02059889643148,16.4296678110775));
#3186=DIRECTION('',(-1.,0.,0.));
#3187=DIRECTION('',(0.,0.,1.));
#3188=AXIS2_PLACEMENT_3D('',#3185,#3186,#3187);
#3189=CYLINDRICAL_SURFACE('',#3188,7.2);
#3190=ORIENTED_EDGE('',*,*,#2847,.T.);
#3191=ORIENTED_EDGE('',*,*,#253,.T.);
#3192=DIRECTION('',(-1.,0.,0.));
#3193=VECTOR('',#3192,1.);
#3194=CARTESIAN_POINT('',(12.,10.4137887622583,13.1180030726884));
#3195=LINE('',#3194,#3193);
#3196=EDGE_CURVE('E1073',#243,#2111,#3195,.T.);
#3197=ORIENTED_EDGE('',*,*,#3196,.T.);
#3198=ORIENTED_EDGE('',*,*,#2112,.T.);
#3199=EDGE_LOOP('',(#3190,#3191,#3197,#3198));
#3200=FACE_BOUND('',#3199,.T.);
#3201=ADVANCED_FACE('F2559',(#3200),#3189,.T.);
#3202=CARTESIAN_POINT('',(12.,0.,0.));
#3203=DIRECTION('',(-1.,0.,0.));
#3204=DIRECTION('',(0.,0.,1.));
#3205=AXIS2_PLACEMENT_3D('',#3202,#3203,#3204);
#3206=CYLINDRICAL_SURFACE('',#3205,16.749);
#3207=ORIENTED_EDGE('',*,*,#2121,.F.);
#3208=ORIENTED_EDGE('',*,*,#3196,.F.);
#3209=ORIENTED_EDGE('',*,*,#244,.T.);
#3210=ORIENTED_EDGE('',*,*,#3179,.T.);
#3211=EDGE_LOOP('',(#3207,#3208,#3209,#3210));
#3212=FACE_BOUND('',#3211,.T.);
#3213=ADVANCED_FACE('F2555',(#3212),#3206,.T.);
#3214=CARTESIAN_POINT('',(12.,14.0637117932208,9.39740445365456));
#3215=DIRECTION('',(-1.,0.,0.));
#3216=DIRECTION('',(0.,0.,1.));
#3217=AXIS2_PLACEMENT_3D('',#3214,#3215,#3216);
#3218=CYLINDRICAL_SURFACE('',#3217,7.2);
#3219=ORIENTED_EDGE('',*,*,#2840,.T.);
#3220=ORIENTED_EDGE('',*,*,#2099,.F.);
#3221=DIRECTION('',(-1.,0.,0.));
#3222=VECTOR('',#3221,1.);
#3223=CARTESIAN_POINT('',(12.,8.76516516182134,14.2723817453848));
#3224=LINE('',#3223,#3222);
#3225=EDGE_CURVE('E1097',#265,#2089,#3224,.T.);
#3226=ORIENTED_EDGE('',*,*,#3225,.F.);
#3227=ORIENTED_EDGE('',*,*,#266,.T.);
#3228=EDGE_LOOP('',(#3219,#3220,#3226,#3227));
#3229=FACE_BOUND('',#3228,.T.);
#3230=ADVANCED_FACE('F2551',(#3229),#3218,.T.);
#3231=CARTESIAN_POINT('',(12.,1.1065350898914,16.8782339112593));
#3232=DIRECTION('',(-1.,0.,0.));
#3233=DIRECTION('',(0.,0.,1.));
#3234=AXIS2_PLACEMENT_3D('',#3231,#3232,#3233);
#3235=CYLINDRICAL_SURFACE('',#3234,7.2);
#3236=ORIENTED_EDGE('',*,*,#2830,.T.);
#3237=ORIENTED_EDGE('',*,*,#284,.T.);
#3238=DIRECTION('',(-1.,0.,0.));
#3239=VECTOR('',#3238,1.);
#3240=CARTESIAN_POINT('',(12.,7.97766258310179,14.7270465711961));
#3241=LINE('',#3240,#3239);
#3242=EDGE_CURVE('E1095',#274,#2080,#3241,.T.);
#3243=ORIENTED_EDGE('',*,*,#3242,.T.);
#3244=ORIENTED_EDGE('',*,*,#2081,.T.);
#3245=EDGE_LOOP('',(#3236,#3237,#3243,#3244));
#3246=FACE_BOUND('',#3245,.T.);
#3247=ADVANCED_FACE('F2547',(#3246),#3235,.T.);
#3248=CARTESIAN_POINT('',(12.,0.,0.));
#3249=DIRECTION('',(-1.,0.,0.));
#3250=DIRECTION('',(0.,0.,1.));
#3251=AXIS2_PLACEMENT_3D('',#3248,#3249,#3250);
#3252=CYLINDRICAL_SURFACE('',#3251,16.749);
#3253=ORIENTED_EDGE('',*,*,#2090,.F.);
#3254=ORIENTED_EDGE('',*,*,#3242,.F.);
#3255=ORIENTED_EDGE('',*,*,#275,.T.);
#3256=ORIENTED_EDGE('',*,*,#3225,.T.);
#3257=EDGE_LOOP('',(#3253,#3254,#3255,#3256));
#3258=FACE_BOUND('',#3257,.T.);
#3259=ADVANCED_FACE('F2543',(#3258),#3252,.T.);
#3260=CARTESIAN_POINT('',(12.,12.2182102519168,11.6967746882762));
#3261=DIRECTION('',(-1.,0.,0.));
#3262=DIRECTION('',(0.,0.,1.));
#3263=AXIS2_PLACEMENT_3D('',#3260,#3261,#3262);
#3264=CYLINDRICAL_SURFACE('',#3263,7.2);
#3265=ORIENTED_EDGE('',*,*,#2823,.T.);
#3266=ORIENTED_EDGE('',*,*,#2068,.F.);
#3267=DIRECTION('',(-1.,0.,0.));
#3268=VECTOR('',#3267,1.);
#3269=CARTESIAN_POINT('',(12.,6.15362952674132,15.5776071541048));
#3270=LINE('',#3269,#3268);
#3271=EDGE_CURVE('E1119',#296,#2058,#3270,.T.);
#3272=ORIENTED_EDGE('',*,*,#3271,.F.);
#3273=ORIENTED_EDGE('',*,*,#297,.T.);
#3274=EDGE_LOOP('',(#3265,#3266,#3272,#3273));
#3275=FACE_BOUND('',#3274,.T.);
#3276=ADVANCED_FACE('F2539',(#3275),#3264,.T.);
#3277=CARTESIAN_POINT('',(12.,-1.84115022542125,16.8139634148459));
#3278=DIRECTION('',(-1.,0.,0.));
#3279=DIRECTION('',(0.,0.,1.));
#3280=AXIS2_PLACEMENT_3D('',#3277,#3278,#3279);
#3281=CYLINDRICAL_SURFACE('',#3280,7.2);
#3282=ORIENTED_EDGE('',*,*,#2813,.T.);
#3283=ORIENTED_EDGE('',*,*,#315,.T.);
#3284=DIRECTION('',(-1.,0.,0.));
#3285=VECTOR('',#3284,1.);
#3286=CARTESIAN_POINT('',(12.,5.29913916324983,15.888616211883));
#3287=LINE('',#3286,#3285);
#3288=EDGE_CURVE('E1117',#305,#2049,#3287,.T.);
#3289=ORIENTED_EDGE('',*,*,#3288,.T.);
#3290=ORIENTED_EDGE('',*,*,#2050,.T.);
#3291=EDGE_LOOP('',(#3282,#3283,#3289,#3290));
#3292=FACE_BOUND('',#3291,.T.);
#3293=ADVANCED_FACE('F2535',(#3292),#3281,.T.);
#3294=CARTESIAN_POINT('',(12.,0.,0.));
#3295=DIRECTION('',(-1.,0.,0.));
#3296=DIRECTION('',(0.,0.,1.));
#3297=AXIS2_PLACEMENT_3D('',#3294,#3295,#3296);
#3298=CYLINDRICAL_SURFACE('',#3297,16.749);
#3299=ORIENTED_EDGE('',*,*,#2059,.F.);
#3300=ORIENTED_EDGE('',*,*,#3288,.F.);
#3301=ORIENTED_EDGE('',*,*,#306,.T.);
#3302=ORIENTED_EDGE('',*,*,#3271,.T.);
#3303=EDGE_LOOP('',(#3299,#3300,#3301,#3302));
#3304=FACE_BOUND('',#3303,.T.);
#3305=ADVANCED_FACE('F2531',(#3304),#3298,.T.);
#3306=CARTESIAN_POINT('',(12.,10.0014645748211,13.6407443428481));
#3307=DIRECTION('',(-1.,0.,0.));
#3308=DIRECTION('',(0.,0.,1.));
#3309=AXIS2_PLACEMENT_3D('',#3306,#3307,#3308);
#3310=CYLINDRICAL_SURFACE('',#3309,7.2);
#3311=ORIENTED_EDGE('',*,*,#2806,.T.);
#3312=ORIENTED_EDGE('',*,*,#2037,.F.);
#3313=DIRECTION('',(-1.,0.,0.));
#3314=VECTOR('',#3313,1.);
#3315=CARTESIAN_POINT('',(12.,3.35511897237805,16.4095148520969));
#3316=LINE('',#3315,#3314);
#3317=EDGE_CURVE('E1141',#327,#2027,#3316,.T.);
#3318=ORIENTED_EDGE('',*,*,#3317,.F.);
#3319=ORIENTED_EDGE('',*,*,#328,.T.);
#3320=EDGE_LOOP('',(#3311,#3312,#3318,#3319));
#3321=FACE_BOUND('',#3320,.T.);
#3322=ADVANCED_FACE('F2527',(#3321),#3310,.T.);
#3323=CARTESIAN_POINT('',(12.,-4.73289312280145,16.2388091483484));
#3324=DIRECTION('',(-1.,0.,0.));
#3325=DIRECTION('',(0.,0.,1.));
#3326=AXIS2_PLACEMENT_3D('',#3323,#3324,#3325);
#3327=CYLINDRICAL_SURFACE('',#3326,7.2);
#3328=ORIENTED_EDGE('',*,*,#2796,.T.);
#3329=ORIENTED_EDGE('',*,*,#346,.T.);
#3330=DIRECTION('',(-1.,0.,0.));
#3331=VECTOR('',#3330,1.);
#3332=CARTESIAN_POINT('',(12.,2.45960408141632,16.5674182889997));
#3333=LINE('',#3332,#3331);
#3334=EDGE_CURVE('E1139',#336,#2018,#3333,.T.);
#3335=ORIENTED_EDGE('',*,*,#3334,.T.);
#3336=ORIENTED_EDGE('',*,*,#2019,.T.);
#3337=EDGE_LOOP('',(#3328,#3329,#3335,#3336));
#3338=FACE_BOUND('',#3337,.T.);
#3339=ADVANCED_FACE('F2523',(#3338),#3327,.T.);
#3340=CARTESIAN_POINT('',(12.,0.,0.));
#3341=DIRECTION('',(-1.,0.,0.));
#3342=DIRECTION('',(0.,0.,1.));
#3343=AXIS2_PLACEMENT_3D('',#3340,#3341,#3342);
#3344=CYLINDRICAL_SURFACE('',#3343,16.749);
#3345=ORIENTED_EDGE('',*,*,#2028,.F.);
#3346=ORIENTED_EDGE('',*,*,#3334,.F.);
#3347=ORIENTED_EDGE('',*,*,#337,.T.);
#3348=ORIENTED_EDGE('',*,*,#3317,.T.);
#3349=EDGE_LOOP('',(#3345,#3346,#3347,#3348));
#3350=FACE_BOUND('',#3349,.T.);
#3351=ADVANCED_FACE('F2519',(#3350),#3344,.T.);
#3352=CARTESIAN_POINT('',(12.,7.4808294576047,15.1702468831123));
#3353=DIRECTION('',(-1.,0.,0.));
#3354=DIRECTION('',(0.,0.,1.));
#3355=AXIS2_PLACEMENT_3D('',#3352,#3353,#3354);
#3356=CYLINDRICAL_SURFACE('',#3355,7.2);
#3357=ORIENTED_EDGE('',*,*,#2789,.T.);
#3358=ORIENTED_EDGE('',*,*,#2006,.F.);
#3359=DIRECTION('',(-1.,0.,0.));
#3360=VECTOR('',#3359,1.);
#3361=CARTESIAN_POINT('',(12.,0.454664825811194,16.7428277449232));
#3362=LINE('',#3361,#3360);
#3363=EDGE_CURVE('E1163',#358,#1996,#3362,.T.);
#3364=ORIENTED_EDGE('',*,*,#3363,.F.);
#3365=ORIENTED_EDGE('',*,*,#359,.T.);
#3366=EDGE_LOOP('',(#3357,#3358,#3364,#3365));
#3367=FACE_BOUND('',#3366,.T.);
#3368=ADVANCED_FACE('F2515',(#3367),#3356,.T.);
#3369=CARTESIAN_POINT('',(12.,-7.48082945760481,15.1702468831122));
#3370=DIRECTION('',(-1.,0.,0.));
#3371=DIRECTION('',(0.,0.,1.));
#3372=AXIS2_PLACEMENT_3D('',#3369,#3370,#3371);
#3373=CYLINDRICAL_SURFACE('',#3372,7.2);
#3374=ORIENTED_EDGE('',*,*,#2779,.T.);
#3375=ORIENTED_EDGE('',*,*,#377,.T.);
#3376=DIRECTION('',(-1.,0.,0.));
#3377=VECTOR('',#3376,1.);
#3378=CARTESIAN_POINT('',(12.,-0.454664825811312,16.7428277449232));
#3379=LINE('',#3378,#3377);
#3380=EDGE_CURVE('E1161',#367,#1987,#3379,.T.);
#3381=ORIENTED_EDGE('',*,*,#3380,.T.);
#3382=ORIENTED_EDGE('',*,*,#1988,.T.);
#3383=EDGE_LOOP('',(#3374,#3375,#3381,#3382));
#3384=FACE_BOUND('',#3383,.T.);
#3385=ADVANCED_FACE('F2511',(#3384),#3373,.T.);
#3386=CARTESIAN_POINT('',(12.,0.,0.));
#3387=DIRECTION('',(-1.,0.,0.));
#3388=DIRECTION('',(0.,0.,1.));
#3389=AXIS2_PLACEMENT_3D('',#3386,#3387,#3388);
#3390=CYLINDRICAL_SURFACE('',#3389,16.749);
#3391=ORIENTED_EDGE('',*,*,#1997,.F.);
#3392=ORIENTED_EDGE('',*,*,#3380,.F.);
#3393=ORIENTED_EDGE('',*,*,#368,.T.);
#3394=ORIENTED_EDGE('',*,*,#3363,.T.);
#3395=EDGE_LOOP('',(#3391,#3392,#3393,#3394));
#3396=FACE_BOUND('',#3395,.T.);
#3397=ADVANCED_FACE('F2507',(#3396),#3390,.T.);
#3398=CARTESIAN_POINT('',(12.,4.73289312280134,16.2388091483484));
#3399=DIRECTION('',(-1.,0.,0.));
#3400=DIRECTION('',(0.,0.,1.));
#3401=AXIS2_PLACEMENT_3D('',#3398,#3399,#3400);
#3402=CYLINDRICAL_SURFACE('',#3401,7.2);
#3403=ORIENTED_EDGE('',*,*,#2772,.T.);
#3404=ORIENTED_EDGE('',*,*,#1975,.F.);
#3405=DIRECTION('',(-1.,0.,0.));
#3406=VECTOR('',#3405,1.);
#3407=CARTESIAN_POINT('',(12.,-2.45960408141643,16.5674182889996));
#3408=LINE('',#3407,#3406);
#3409=EDGE_CURVE('E1185',#389,#1965,#3408,.T.);
#3410=ORIENTED_EDGE('',*,*,#3409,.F.);
#3411=ORIENTED_EDGE('',*,*,#390,.T.);
#3412=EDGE_LOOP('',(#3403,#3404,#3410,#3411));
#3413=FACE_BOUND('',#3412,.T.);
#3414=ADVANCED_FACE('F2503',(#3413),#3402,.T.);
#3415=CARTESIAN_POINT('',(12.,-10.0014645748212,13.640744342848));
#3416=DIRECTION('',(-1.,0.,0.));
#3417=DIRECTION('',(0.,0.,1.));
#3418=AXIS2_PLACEMENT_3D('',#3415,#3416,#3417);
#3419=CYLINDRICAL_SURFACE('',#3418,7.2);
#3420=ORIENTED_EDGE('',*,*,#2762,.T.);
#3421=ORIENTED_EDGE('',*,*,#408,.T.);
#3422=DIRECTION('',(-1.,0.,0.));
#3423=VECTOR('',#3422,1.);
#3424=CARTESIAN_POINT('',(12.,-3.35511897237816,16.4095148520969));
#3425=LINE('',#3424,#3423);
#3426=EDGE_CURVE('E1183',#398,#1956,#3425,.T.);
#3427=ORIENTED_EDGE('',*,*,#3426,.T.);
#3428=ORIENTED_EDGE('',*,*,#1957,.T.);
#3429=EDGE_LOOP('',(#3420,#3421,#3427,#3428));
#3430=FACE_BOUND('',#3429,.T.);
#3431=ADVANCED_FACE('F2499',(#3430),#3419,.T.);
#3432=CARTESIAN_POINT('',(12.,0.,0.));
#3433=DIRECTION('',(-1.,0.,0.));
#3434=DIRECTION('',(0.,0.,1.));
#3435=AXIS2_PLACEMENT_3D('',#3432,#3433,#3434);
#3436=CYLINDRICAL_SURFACE('',#3435,16.749);
#3437=ORIENTED_EDGE('',*,*,#1966,.F.);
#3438=ORIENTED_EDGE('',*,*,#3426,.F.);
#3439=ORIENTED_EDGE('',*,*,#399,.T.);
#3440=ORIENTED_EDGE('',*,*,#3409,.T.);
#3441=EDGE_LOOP('',(#3437,#3438,#3439,#3440));
#3442=FACE_BOUND('',#3441,.T.);
#3443=ADVANCED_FACE('F2495',(#3442),#3436,.T.);
#3444=CARTESIAN_POINT('',(12.,1.84115022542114,16.8139634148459));
#3445=DIRECTION('',(-1.,0.,0.));
#3446=DIRECTION('',(0.,0.,1.));
#3447=AXIS2_PLACEMENT_3D('',#3444,#3445,#3446);
#3448=CYLINDRICAL_SURFACE('',#3447,7.2);
#3449=ORIENTED_EDGE('',*,*,#2755,.T.);
#3450=ORIENTED_EDGE('',*,*,#1944,.F.);
#3451=DIRECTION('',(-1.,0.,0.));
#3452=VECTOR('',#3451,1.);
#3453=CARTESIAN_POINT('',(12.,-5.29913916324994,15.888616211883));
#3454=LINE('',#3453,#3452);
#3455=EDGE_CURVE('E1207',#420,#1934,#3454,.T.);
#3456=ORIENTED_EDGE('',*,*,#3455,.F.);
#3457=ORIENTED_EDGE('',*,*,#421,.T.);
#3458=EDGE_LOOP('',(#3449,#3450,#3456,#3457));
#3459=FACE_BOUND('',#3458,.T.);
#3460=ADVANCED_FACE('F2491',(#3459),#3448,.T.);
#3461=CARTESIAN_POINT('',(12.,-12.2182102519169,11.6967746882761));
#3462=DIRECTION('',(-1.,0.,0.));
#3463=DIRECTION('',(0.,0.,1.));
#3464=AXIS2_PLACEMENT_3D('',#3461,#3462,#3463);
#3465=CYLINDRICAL_SURFACE('',#3464,7.2);
#3466=ORIENTED_EDGE('',*,*,#2745,.T.);
#3467=ORIENTED_EDGE('',*,*,#439,.T.);
#3468=DIRECTION('',(-1.,0.,0.));
#3469=VECTOR('',#3468,1.);
#3470=CARTESIAN_POINT('',(12.,-6.15362952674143,15.5776071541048));
#3471=LINE('',#3470,#3469);
#3472=EDGE_CURVE('E1205',#429,#1925,#3471,.T.);
#3473=ORIENTED_EDGE('',*,*,#3472,.T.);
#3474=ORIENTED_EDGE('',*,*,#1926,.T.);
#3475=EDGE_LOOP('',(#3466,#3467,#3473,#3474));
#3476=FACE_BOUND('',#3475,.T.);
#3477=ADVANCED_FACE('F2487',(#3476),#3465,.T.);
#3478=CARTESIAN_POINT('',(12.,0.,0.));
#3479=DIRECTION('',(-1.,0.,0.));
#3480=DIRECTION('',(0.,0.,1.));
#3481=AXIS2_PLACEMENT_3D('',#3478,#3479,#3480);
#3482=CYLINDRICAL_SURFACE('',#3481,16.749);
#3483=ORIENTED_EDGE('',*,*,#1935,.F.);
#3484=ORIENTED_EDGE('',*,*,#3472,.F.);
#3485=ORIENTED_EDGE('',*,*,#430,.T.);
#3486=ORIENTED_EDGE('',*,*,#3455,.T.);
#3487=EDGE_LOOP('',(#3483,#3484,#3485,#3486));
#3488=FACE_BOUND('',#3487,.T.);
#3489=ADVANCED_FACE('F2483',(#3488),#3482,.T.);
#3490=CARTESIAN_POINT('',(12.,-1.10653508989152,16.8782339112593));
#3491=DIRECTION('',(-1.,0.,0.));
#3492=DIRECTION('',(0.,0.,1.));
#3493=AXIS2_PLACEMENT_3D('',#3490,#3491,#3492);
#3494=CYLINDRICAL_SURFACE('',#3493,7.2);
#3495=ORIENTED_EDGE('',*,*,#2738,.T.);
#3496=ORIENTED_EDGE('',*,*,#1913,.F.);
#3497=DIRECTION('',(-1.,0.,0.));
#3498=VECTOR('',#3497,1.);
#3499=CARTESIAN_POINT('',(12.,-7.9776625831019,14.727046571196));
#3500=LINE('',#3499,#3498);
#3501=EDGE_CURVE('E1229',#451,#1903,#3500,.T.);
#3502=ORIENTED_EDGE('',*,*,#3501,.F.);
#3503=ORIENTED_EDGE('',*,*,#452,.T.);
#3504=EDGE_LOOP('',(#3495,#3496,#3502,#3503));
#3505=FACE_BOUND('',#3504,.T.);
#3506=ADVANCED_FACE('F2479',(#3505),#3494,.T.);
#3507=CARTESIAN_POINT('',(12.,-14.0637117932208,9.39740445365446));
#3508=DIRECTION('',(-1.,0.,0.));
#3509=DIRECTION('',(0.,0.,1.));
#3510=AXIS2_PLACEMENT_3D('',#3507,#3508,#3509);
#3511=CYLINDRICAL_SURFACE('',#3510,7.2);
#3512=ORIENTED_EDGE('',*,*,#2728,.T.);
#3513=ORIENTED_EDGE('',*,*,#470,.T.);
#3514=DIRECTION('',(-1.,0.,0.));
#3515=VECTOR('',#3514,1.);
#3516=CARTESIAN_POINT('',(12.,-8.76516516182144,14.2723817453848));
#3517=LINE('',#3516,#3515);
#3518=EDGE_CURVE('E1227',#460,#1894,#3517,.T.);
#3519=ORIENTED_EDGE('',*,*,#3518,.T.);
#3520=ORIENTED_EDGE('',*,*,#1895,.T.);
#3521=EDGE_LOOP('',(#3512,#3513,#3519,#3520));
#3522=FACE_BOUND('',#3521,.T.);
#3523=ADVANCED_FACE('F2475',(#3522),#3511,.T.);
#3524=CARTESIAN_POINT('',(12.,0.,0.));
#3525=DIRECTION('',(-1.,0.,0.));
#3526=DIRECTION('',(0.,0.,1.));
#3527=AXIS2_PLACEMENT_3D('',#3524,#3525,#3526);
#3528=CYLINDRICAL_SURFACE('',#3527,16.749);
#3529=ORIENTED_EDGE('',*,*,#1904,.F.);
#3530=ORIENTED_EDGE('',*,*,#3518,.F.);
#3531=ORIENTED_EDGE('',*,*,#461,.T.);
#3532=ORIENTED_EDGE('',*,*,#3501,.T.);
#3533=EDGE_LOOP('',(#3529,#3530,#3531,#3532));
#3534=FACE_BOUND('',#3533,.T.);
#3535=ADVANCED_FACE('F2471',(#3534),#3528,.T.);
#3536=CARTESIAN_POINT('',(12.,-4.02059889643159,16.4296678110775));
#3537=DIRECTION('',(-1.,0.,0.));
#3538=DIRECTION('',(0.,0.,1.));
#3539=AXIS2_PLACEMENT_3D('',#3536,#3537,#3538);
#3540=CYLINDRICAL_SURFACE('',#3539,7.2);
#3541=ORIENTED_EDGE('',*,*,#2721,.T.);
#3542=ORIENTED_EDGE('',*,*,#1882,.F.);
#3543=DIRECTION('',(-1.,0.,0.));
#3544=VECTOR('',#3543,1.);
#3545=CARTESIAN_POINT('',(12.,-10.4137887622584,13.1180030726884));
#3546=LINE('',#3545,#3544);
#3547=EDGE_CURVE('E1251',#482,#1872,#3546,.T.);
#3548=ORIENTED_EDGE('',*,*,#3547,.F.);
#3549=ORIENTED_EDGE('',*,*,#483,.T.);
#3550=EDGE_LOOP('',(#3541,#3542,#3548,#3549));
#3551=FACE_BOUND('',#3550,.T.);
#3552=ADVANCED_FACE('F2467',(#3551),#3540,.T.);
#3553=CARTESIAN_POINT('',(12.,-15.4818945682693,6.81249884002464));
#3554=DIRECTION('',(-1.,0.,0.));
#3555=DIRECTION('',(0.,0.,1.));
#3556=AXIS2_PLACEMENT_3D('',#3553,#3554,#3555);
#3557=CYLINDRICAL_SURFACE('',#3556,7.2);
#3558=ORIENTED_EDGE('',*,*,#2711,.T.);
#3559=ORIENTED_EDGE('',*,*,#501,.T.);
#3560=DIRECTION('',(-1.,0.,0.));
#3561=VECTOR('',#3560,1.);
#3562=CARTESIAN_POINT('',(12.,-11.1103756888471,12.5334972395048));
#3563=LINE('',#3562,#3561);
#3564=EDGE_CURVE('E1249',#491,#1863,#3563,.T.);
#3565=ORIENTED_EDGE('',*,*,#3564,.T.);
#3566=ORIENTED_EDGE('',*,*,#1864,.T.);
#3567=EDGE_LOOP('',(#3558,#3559,#3565,#3566));
#3568=FACE_BOUND('',#3567,.T.);
#3569=ADVANCED_FACE('F2463',(#3568),#3557,.T.);
#3570=CARTESIAN_POINT('',(12.,0.,0.));
#3571=DIRECTION('',(-1.,0.,0.));
#3572=DIRECTION('',(0.,0.,1.));
#3573=AXIS2_PLACEMENT_3D('',#3570,#3571,#3572);
#3574=CYLINDRICAL_SURFACE('',#3573,16.749);
#3575=ORIENTED_EDGE('',*,*,#1873,.F.);
#3576=ORIENTED_EDGE('',*,*,#3564,.F.);
#3577=ORIENTED_EDGE('',*,*,#492,.T.);
#3578=ORIENTED_EDGE('',*,*,#3547,.T.);
#3579=EDGE_LOOP('',(#3575,#3576,#3577,#3578));
#3580=FACE_BOUND('',#3579,.T.);
#3581=ADVANCED_FACE('F2459',(#3580),#3574,.T.);
#3582=CARTESIAN_POINT('',(12.,-6.8124988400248,15.4818945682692));
#3583=DIRECTION('',(-1.,0.,0.));
#3584=DIRECTION('',(0.,0.,1.));
#3585=AXIS2_PLACEMENT_3D('',#3582,#3583,#3584);
#3586=CYLINDRICAL_SURFACE('',#3585,7.2);
#3587=ORIENTED_EDGE('',*,*,#2704,.T.);
#3588=ORIENTED_EDGE('',*,*,#1851,.F.);
#3589=DIRECTION('',(-1.,0.,0.));
#3590=VECTOR('',#3589,1.);
#3591=CARTESIAN_POINT('',(12.,-12.533497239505,11.110375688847));
#3592=LINE('',#3591,#3590);
#3593=EDGE_CURVE('E1273',#513,#1841,#3592,.T.);
#3594=ORIENTED_EDGE('',*,*,#3593,.F.);
#3595=ORIENTED_EDGE('',*,*,#514,.T.);
#3596=EDGE_LOOP('',(#3587,#3588,#3594,#3595));
#3597=FACE_BOUND('',#3596,.T.);
#3598=ADVANCED_FACE('F2455',(#3597),#3586,.T.);
#3599=CARTESIAN_POINT('',(12.,-16.4296678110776,4.02059889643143));
#3600=DIRECTION('',(-1.,0.,0.));
#3601=DIRECTION('',(0.,0.,1.));
#3602=AXIS2_PLACEMENT_3D('',#3599,#3600,#3601);
#3603=CYLINDRICAL_SURFACE('',#3602,7.2);
#3604=ORIENTED_EDGE('',*,*,#2694,.T.);
#3605=ORIENTED_EDGE('',*,*,#532,.T.);
#3606=DIRECTION('',(-1.,0.,0.));
#3607=VECTOR('',#3606,1.);
#3608=CARTESIAN_POINT('',(12.,-13.1180030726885,10.4137887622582));
#3609=LINE('',#3608,#3607);
#3610=EDGE_CURVE('E1271',#522,#1832,#3609,.T.);
#3611=ORIENTED_EDGE('',*,*,#3610,.T.);
#3612=ORIENTED_EDGE('',*,*,#1833,.T.);
#3613=EDGE_LOOP('',(#3604,#3605,#3611,#3612));
#3614=FACE_BOUND('',#3613,.T.);
#3615=ADVANCED_FACE('F2451',(#3614),#3603,.T.);
#3616=CARTESIAN_POINT('',(12.,0.,0.));
#3617=DIRECTION('',(-1.,0.,0.));
#3618=DIRECTION('',(0.,0.,1.));
#3619=AXIS2_PLACEMENT_3D('',#3616,#3617,#3618);
#3620=CYLINDRICAL_SURFACE('',#3619,16.749);
#3621=ORIENTED_EDGE('',*,*,#1842,.F.);
#3622=ORIENTED_EDGE('',*,*,#3610,.F.);
#3623=ORIENTED_EDGE('',*,*,#523,.T.);
#3624=ORIENTED_EDGE('',*,*,#3593,.T.);
#3625=EDGE_LOOP('',(#3621,#3622,#3623,#3624));
#3626=FACE_BOUND('',#3625,.T.);
#3627=ADVANCED_FACE('F2447',(#3626),#3620,.T.);
#3628=CARTESIAN_POINT('',(12.,-9.3974044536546,14.0637117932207));
#3629=DIRECTION('',(-1.,0.,0.));
#3630=DIRECTION('',(0.,0.,1.));
#3631=AXIS2_PLACEMENT_3D('',#3628,#3629,#3630);
#3632=CYLINDRICAL_SURFACE('',#3631,7.2);
#3633=ORIENTED_EDGE('',*,*,#2687,.T.);
#3634=ORIENTED_EDGE('',*,*,#1820,.F.);
#3635=DIRECTION('',(-1.,0.,0.));
#3636=VECTOR('',#3635,1.);
#3637=CARTESIAN_POINT('',(12.,-14.2723817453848,8.76516516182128));
#3638=LINE('',#3637,#3636);
#3639=EDGE_CURVE('E1295',#544,#1810,#3638,.T.);
#3640=ORIENTED_EDGE('',*,*,#3639,.F.);
#3641=ORIENTED_EDGE('',*,*,#545,.T.);
#3642=EDGE_LOOP('',(#3633,#3634,#3640,#3641));
#3643=FACE_BOUND('',#3642,.T.);
#3644=ADVANCED_FACE('F2443',(#3643),#3632,.T.);
#3645=CARTESIAN_POINT('',(12.,-16.8782339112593,1.10653508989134));
#3646=DIRECTION('',(-1.,0.,0.));
#3647=DIRECTION('',(0.,0.,1.));
#3648=AXIS2_PLACEMENT_3D('',#3645,#3646,#3647);
#3649=CYLINDRICAL_SURFACE('',#3648,7.2);
#3650=ORIENTED_EDGE('',*,*,#2677,.T.);
#3651=ORIENTED_EDGE('',*,*,#563,.T.);
#3652=DIRECTION('',(-1.,0.,0.));
#3653=VECTOR('',#3652,1.);
#3654=CARTESIAN_POINT('',(12.,-14.7270465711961,7.97766258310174));
#3655=LINE('',#3654,#3653);
#3656=EDGE_CURVE('E1293',#553,#1801,#3655,.T.);
#3657=ORIENTED_EDGE('',*,*,#3656,.T.);
#3658=ORIENTED_EDGE('',*,*,#1802,.T.);
#3659=EDGE_LOOP('',(#3650,#3651,#3657,#3658));
#3660=FACE_BOUND('',#3659,.T.);
#3661=ADVANCED_FACE('F2439',(#3660),#3649,.T.);
#3662=CARTESIAN_POINT('',(12.,0.,0.));
#3663=DIRECTION('',(-1.,0.,0.));
#3664=DIRECTION('',(0.,0.,1.));
#3665=AXIS2_PLACEMENT_3D('',#3662,#3663,#3664);
#3666=CYLINDRICAL_SURFACE('',#3665,16.749);
#3667=ORIENTED_EDGE('',*,*,#1811,.F.);
#3668=ORIENTED_EDGE('',*,*,#3656,.F.);
#3669=ORIENTED_EDGE('',*,*,#554,.T.);
#3670=ORIENTED_EDGE('',*,*,#3639,.T.);
#3671=EDGE_LOOP('',(#3667,#3668,#3669,#3670));
#3672=FACE_BOUND('',#3671,.T.);
#3673=ADVANCED_FACE('F2435',(#3672),#3666,.T.);
#3674=CARTESIAN_POINT('',(12.,-11.6967746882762,12.2182102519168));
#3675=DIRECTION('',(-1.,0.,0.));
#3676=DIRECTION('',(0.,0.,1.));
#3677=AXIS2_PLACEMENT_3D('',#3674,#3675,#3676);
#3678=CYLINDRICAL_SURFACE('',#3677,7.2);
#3679=ORIENTED_EDGE('',*,*,#2670,.T.);
#3680=ORIENTED_EDGE('',*,*,#1789,.F.);
#3681=DIRECTION('',(-1.,0.,0.));
#3682=VECTOR('',#3681,1.);
#3683=CARTESIAN_POINT('',(12.,-15.5776071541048,6.15362952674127));
#3684=LINE('',#3683,#3682);
#3685=EDGE_CURVE('E1317',#575,#1779,#3684,.T.);
#3686=ORIENTED_EDGE('',*,*,#3685,.F.);
#3687=ORIENTED_EDGE('',*,*,#576,.T.);
#3688=EDGE_LOOP('',(#3679,#3680,#3686,#3687));
#3689=FACE_BOUND('',#3688,.T.);
#3690=ADVANCED_FACE('F2431',(#3689),#3678,.T.);
#3691=CARTESIAN_POINT('',(12.,-16.8139634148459,-1.84115022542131));
#3692=DIRECTION('',(-1.,0.,0.));
#3693=DIRECTION('',(0.,0.,1.));
#3694=AXIS2_PLACEMENT_3D('',#3691,#3692,#3693);
#3695=CYLINDRICAL_SURFACE('',#3694,7.2);
#3696=ORIENTED_EDGE('',*,*,#2660,.T.);
#3697=ORIENTED_EDGE('',*,*,#594,.T.);
#3698=DIRECTION('',(-1.,0.,0.));
#3699=VECTOR('',#3698,1.);
#3700=CARTESIAN_POINT('',(12.,-15.888616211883,5.29913916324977));
#3701=LINE('',#3700,#3699);
#3702=EDGE_CURVE('E1315',#584,#1770,#3701,.T.);
#3703=ORIENTED_EDGE('',*,*,#3702,.T.);
#3704=ORIENTED_EDGE('',*,*,#1771,.T.);
#3705=EDGE_LOOP('',(#3696,#3697,#3703,#3704));
#3706=FACE_BOUND('',#3705,.T.);
#3707=ADVANCED_FACE('F2427',(#3706),#3695,.T.);
#3708=CARTESIAN_POINT('',(12.,0.,0.));
#3709=DIRECTION('',(-1.,0.,0.));
#3710=DIRECTION('',(0.,0.,1.));
#3711=AXIS2_PLACEMENT_3D('',#3708,#3709,#3710);
#3712=CYLINDRICAL_SURFACE('',#3711,16.749);
#3713=ORIENTED_EDGE('',*,*,#1780,.F.);
#3714=ORIENTED_EDGE('',*,*,#3702,.F.);
#3715=ORIENTED_EDGE('',*,*,#585,.T.);
#3716=ORIENTED_EDGE('',*,*,#3685,.T.);
#3717=EDGE_LOOP('',(#3713,#3714,#3715,#3716));
#3718=FACE_BOUND('',#3717,.T.);
#3719=ADVANCED_FACE('F2423',(#3718),#3712,.T.);
#3720=CARTESIAN_POINT('',(12.,-13.6407443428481,10.0014645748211));
#3721=DIRECTION('',(-1.,0.,0.));
#3722=DIRECTION('',(0.,0.,1.));
#3723=AXIS2_PLACEMENT_3D('',#3720,#3721,#3722);
#3724=CYLINDRICAL_SURFACE('',#3723,7.2);
#3725=ORIENTED_EDGE('',*,*,#2653,.T.);
#3726=ORIENTED_EDGE('',*,*,#1758,.F.);
#3727=DIRECTION('',(-1.,0.,0.));
#3728=VECTOR('',#3727,1.);
#3729=CARTESIAN_POINT('',(12.,-16.4095148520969,3.355118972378));
#3730=LINE('',#3729,#3728);
#3731=EDGE_CURVE('E1339',#606,#1748,#3730,.T.);
#3732=ORIENTED_EDGE('',*,*,#3731,.F.);
#3733=ORIENTED_EDGE('',*,*,#607,.T.);
#3734=EDGE_LOOP('',(#3725,#3726,#3732,#3733));
#3735=FACE_BOUND('',#3734,.T.);
#3736=ADVANCED_FACE('F2419',(#3735),#3724,.T.);
#3737=CARTESIAN_POINT('',(12.,-16.2388091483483,-4.7328931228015));
#3738=DIRECTION('',(-1.,0.,0.));
#3739=DIRECTION('',(0.,0.,1.));
#3740=AXIS2_PLACEMENT_3D('',#3737,#3738,#3739);
#3741=CYLINDRICAL_SURFACE('',#3740,7.2);
#3742=ORIENTED_EDGE('',*,*,#2643,.T.);
#3743=ORIENTED_EDGE('',*,*,#625,.T.);
#3744=DIRECTION('',(-1.,0.,0.));
#3745=VECTOR('',#3744,1.);
#3746=CARTESIAN_POINT('',(12.,-16.5674182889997,2.45960408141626));
#3747=LINE('',#3746,#3745);
#3748=EDGE_CURVE('E1337',#615,#1739,#3747,.T.);
#3749=ORIENTED_EDGE('',*,*,#3748,.T.);
#3750=ORIENTED_EDGE('',*,*,#1740,.T.);
#3751=EDGE_LOOP('',(#3742,#3743,#3749,#3750));
#3752=FACE_BOUND('',#3751,.T.);
#3753=ADVANCED_FACE('F2415',(#3752),#3741,.T.);
#3754=CARTESIAN_POINT('',(12.,0.,0.));
#3755=DIRECTION('',(-1.,0.,0.));
#3756=DIRECTION('',(0.,0.,1.));
#3757=AXIS2_PLACEMENT_3D('',#3754,#3755,#3756);
#3758=CYLINDRICAL_SURFACE('',#3757,16.749);
#3759=ORIENTED_EDGE('',*,*,#1749,.F.);
#3760=ORIENTED_EDGE('',*,*,#3748,.F.);
#3761=ORIENTED_EDGE('',*,*,#616,.T.);
#3762=ORIENTED_EDGE('',*,*,#3731,.T.);
#3763=EDGE_LOOP('',(#3759,#3760,#3761,#3762));
#3764=FACE_BOUND('',#3763,.T.);
#3765=ADVANCED_FACE('F2411',(#3764),#3758,.T.);
#3766=CARTESIAN_POINT('',(12.,-15.1702468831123,7.48082945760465));
#3767=DIRECTION('',(-1.,0.,0.));
#3768=DIRECTION('',(0.,0.,1.));
#3769=AXIS2_PLACEMENT_3D('',#3766,#3767,#3768);
#3770=CYLINDRICAL_SURFACE('',#3769,7.2);
#3771=ORIENTED_EDGE('',*,*,#2636,.T.);
#3772=ORIENTED_EDGE('',*,*,#1727,.F.);
#3773=DIRECTION('',(-1.,0.,0.));
#3774=VECTOR('',#3773,1.);
#3775=CARTESIAN_POINT('',(12.,-16.7428277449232,0.454664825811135));
#3776=LINE('',#3775,#3774);
#3777=EDGE_CURVE('E1361',#637,#1717,#3776,.T.);
#3778=ORIENTED_EDGE('',*,*,#3777,.F.);
#3779=ORIENTED_EDGE('',*,*,#638,.T.);
#3780=EDGE_LOOP('',(#3771,#3772,#3778,#3779));
#3781=FACE_BOUND('',#3780,.T.);
#3782=ADVANCED_FACE('F2407',(#3781),#3770,.T.);
#3783=CARTESIAN_POINT('',(12.,-15.1702468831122,-7.48082945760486));
#3784=DIRECTION('',(-1.,0.,0.));
#3785=DIRECTION('',(0.,0.,1.));
#3786=AXIS2_PLACEMENT_3D('',#3783,#3784,#3785);
#3787=CYLINDRICAL_SURFACE('',#3786,7.2);
#3788=ORIENTED_EDGE('',*,*,#2626,.T.);
#3789=ORIENTED_EDGE('',*,*,#656,.T.);
#3790=DIRECTION('',(-1.,0.,0.));
#3791=VECTOR('',#3790,1.);
#3792=CARTESIAN_POINT('',(12.,-16.7428277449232,-0.454664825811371));
#3793=LINE('',#3792,#3791);
#3794=EDGE_CURVE('E1359',#646,#1708,#3793,.T.);
#3795=ORIENTED_EDGE('',*,*,#3794,.T.);
#3796=ORIENTED_EDGE('',*,*,#1709,.T.);
#3797=EDGE_LOOP('',(#3788,#3789,#3795,#3796));
#3798=FACE_BOUND('',#3797,.T.);
#3799=ADVANCED_FACE('F2403',(#3798),#3787,.T.);
#3800=CARTESIAN_POINT('',(12.,0.,0.));
#3801=DIRECTION('',(-1.,0.,0.));
#3802=DIRECTION('',(0.,0.,1.));
#3803=AXIS2_PLACEMENT_3D('',#3800,#3801,#3802);
#3804=CYLINDRICAL_SURFACE('',#3803,16.749);
#3805=ORIENTED_EDGE('',*,*,#1718,.F.);
#3806=ORIENTED_EDGE('',*,*,#3794,.F.);
#3807=ORIENTED_EDGE('',*,*,#647,.T.);
#3808=ORIENTED_EDGE('',*,*,#3777,.T.);
#3809=EDGE_LOOP('',(#3805,#3806,#3807,#3808));
#3810=FACE_BOUND('',#3809,.T.);
#3811=ADVANCED_FACE('F2399',(#3810),#3804,.T.);
#3812=CARTESIAN_POINT('',(12.,-16.2388091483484,4.73289312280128));
#3813=DIRECTION('',(-1.,0.,0.));
#3814=DIRECTION('',(0.,0.,1.));
#3815=AXIS2_PLACEMENT_3D('',#3812,#3813,#3814);
#3816=CYLINDRICAL_SURFACE('',#3815,7.2);
#3817=ORIENTED_EDGE('',*,*,#2619,.T.);
#3818=ORIENTED_EDGE('',*,*,#1696,.F.);
#3819=DIRECTION('',(-1.,0.,0.));
#3820=VECTOR('',#3819,1.);
#3821=CARTESIAN_POINT('',(12.,-16.5674182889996,-2.45960408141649));
#3822=LINE('',#3821,#3820);
#3823=EDGE_CURVE('E1383',#668,#1686,#3822,.T.);
#3824=ORIENTED_EDGE('',*,*,#3823,.F.);
#3825=ORIENTED_EDGE('',*,*,#669,.T.);
#3826=EDGE_LOOP('',(#3817,#3818,#3824,#3825));
#3827=FACE_BOUND('',#3826,.T.);
#3828=ADVANCED_FACE('F2395',(#3827),#3816,.T.);
#3829=CARTESIAN_POINT('',(12.,-13.640744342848,-10.0014645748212));
#3830=DIRECTION('',(-1.,0.,0.));
#3831=DIRECTION('',(0.,0.,1.));
#3832=AXIS2_PLACEMENT_3D('',#3829,#3830,#3831);
#3833=CYLINDRICAL_SURFACE('',#3832,7.2);
#3834=ORIENTED_EDGE('',*,*,#2609,.T.);
#3835=ORIENTED_EDGE('',*,*,#687,.T.);
#3836=DIRECTION('',(-1.,0.,0.));
#3837=VECTOR('',#3836,1.);
#3838=CARTESIAN_POINT('',(12.,-16.4095148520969,-3.35511897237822));
#3839=LINE('',#3838,#3837);
#3840=EDGE_CURVE('E1381',#677,#1677,#3839,.T.);
#3841=ORIENTED_EDGE('',*,*,#3840,.T.);
#3842=ORIENTED_EDGE('',*,*,#1678,.T.);
#3843=EDGE_LOOP('',(#3834,#3835,#3841,#3842));
#3844=FACE_BOUND('',#3843,.T.);
#3845=ADVANCED_FACE('F2391',(#3844),#3833,.T.);
#3846=CARTESIAN_POINT('',(12.,0.,0.));
#3847=DIRECTION('',(-1.,0.,0.));
#3848=DIRECTION('',(0.,0.,1.));
#3849=AXIS2_PLACEMENT_3D('',#3846,#3847,#3848);
#3850=CYLINDRICAL_SURFACE('',#3849,16.749);
#3851=ORIENTED_EDGE('',*,*,#1687,.F.);
#3852=ORIENTED_EDGE('',*,*,#3840,.F.);
#3853=ORIENTED_EDGE('',*,*,#678,.T.);
#3854=ORIENTED_EDGE('',*,*,#3823,.T.);
#3855=EDGE_LOOP('',(#3851,#3852,#3853,#3854));
#3856=FACE_BOUND('',#3855,.T.);
#3857=ADVANCED_FACE('F2387',(#3856),#3850,.T.);
#3858=CARTESIAN_POINT('',(12.,-16.8139634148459,1.84115022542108));
#3859=DIRECTION('',(-1.,0.,0.));
#3860=DIRECTION('',(0.,0.,1.));
#3861=AXIS2_PLACEMENT_3D('',#3858,#3859,#3860);
#3862=CYLINDRICAL_SURFACE('',#3861,7.2);
#3863=ORIENTED_EDGE('',*,*,#2602,.T.);
#3864=ORIENTED_EDGE('',*,*,#1665,.F.);
#3865=DIRECTION('',(-1.,0.,0.));
#3866=VECTOR('',#3865,1.);
#3867=CARTESIAN_POINT('',(12.,-15.888616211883,-5.29913916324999));
#3868=LINE('',#3867,#3866);
#3869=EDGE_CURVE('E1405',#699,#1655,#3868,.T.);
#3870=ORIENTED_EDGE('',*,*,#3869,.F.);
#3871=ORIENTED_EDGE('',*,*,#700,.T.);
#3872=EDGE_LOOP('',(#3863,#3864,#3870,#3871));
#3873=FACE_BOUND('',#3872,.T.);
#3874=ADVANCED_FACE('F2383',(#3873),#3862,.T.);
#3875=CARTESIAN_POINT('',(12.,-11.696774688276,-12.2182102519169));
#3876=DIRECTION('',(-1.,0.,0.));
#3877=DIRECTION('',(0.,0.,1.));
#3878=AXIS2_PLACEMENT_3D('',#3875,#3876,#3877);
#3879=CYLINDRICAL_SURFACE('',#3878,7.2);
#3880=ORIENTED_EDGE('',*,*,#2592,.T.);
#3881=ORIENTED_EDGE('',*,*,#718,.T.);
#3882=DIRECTION('',(-1.,0.,0.));
#3883=VECTOR('',#3882,1.);
#3884=CARTESIAN_POINT('',(12.,-15.5776071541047,-6.15362952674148));
#3885=LINE('',#3884,#3883);
#3886=EDGE_CURVE('E1403',#708,#1646,#3885,.T.);
#3887=ORIENTED_EDGE('',*,*,#3886,.T.);
#3888=ORIENTED_EDGE('',*,*,#1647,.T.);
#3889=EDGE_LOOP('',(#3880,#3881,#3887,#3888));
#3890=FACE_BOUND('',#3889,.T.);
#3891=ADVANCED_FACE('F2379',(#3890),#3879,.T.);
#3892=CARTESIAN_POINT('',(12.,0.,0.));
#3893=DIRECTION('',(-1.,0.,0.));
#3894=DIRECTION('',(0.,0.,1.));
#3895=AXIS2_PLACEMENT_3D('',#3892,#3893,#3894);
#3896=CYLINDRICAL_SURFACE('',#3895,16.749);
#3897=ORIENTED_EDGE('',*,*,#1656,.F.);
#3898=ORIENTED_EDGE('',*,*,#3886,.F.);
#3899=ORIENTED_EDGE('',*,*,#709,.T.);
#3900=ORIENTED_EDGE('',*,*,#3869,.T.);
#3901=EDGE_LOOP('',(#3897,#3898,#3899,#3900));
#3902=FACE_BOUND('',#3901,.T.);
#3903=ADVANCED_FACE('F2375',(#3902),#3896,.T.);
#3904=CARTESIAN_POINT('',(12.,-16.8782339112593,-1.10653508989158));
#3905=DIRECTION('',(-1.,0.,0.));
#3906=DIRECTION('',(0.,0.,1.));
#3907=AXIS2_PLACEMENT_3D('',#3904,#3905,#3906);
#3908=CYLINDRICAL_SURFACE('',#3907,7.2);
#3909=ORIENTED_EDGE('',*,*,#2585,.T.);
#3910=ORIENTED_EDGE('',*,*,#1634,.F.);
#3911=DIRECTION('',(-1.,0.,0.));
#3912=VECTOR('',#3911,1.);
#3913=CARTESIAN_POINT('',(12.,-14.727046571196,-7.97766258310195));
#3914=LINE('',#3913,#3912);
#3915=EDGE_CURVE('E1427',#730,#1624,#3914,.T.);
#3916=ORIENTED_EDGE('',*,*,#3915,.F.);
#3917=ORIENTED_EDGE('',*,*,#731,.T.);
#3918=EDGE_LOOP('',(#3909,#3910,#3916,#3917));
#3919=FACE_BOUND('',#3918,.T.);
#3920=ADVANCED_FACE('F2371',(#3919),#3908,.T.);
#3921=CARTESIAN_POINT('',(12.,-9.39740445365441,-14.0637117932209));
#3922=DIRECTION('',(-1.,0.,0.));
#3923=DIRECTION('',(0.,0.,1.));
#3924=AXIS2_PLACEMENT_3D('',#3921,#3922,#3923);
#3925=CYLINDRICAL_SURFACE('',#3924,7.2);
#3926=ORIENTED_EDGE('',*,*,#2575,.T.);
#3927=ORIENTED_EDGE('',*,*,#749,.T.);
#3928=DIRECTION('',(-1.,0.,0.));
#3929=VECTOR('',#3928,1.);
#3930=CARTESIAN_POINT('',(12.,-14.2723817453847,-8.76516516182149));
#3931=LINE('',#3930,#3929);
#3932=EDGE_CURVE('E1425',#739,#1615,#3931,.T.);
#3933=ORIENTED_EDGE('',*,*,#3932,.T.);
#3934=ORIENTED_EDGE('',*,*,#1616,.T.);
#3935=EDGE_LOOP('',(#3926,#3927,#3933,#3934));
#3936=FACE_BOUND('',#3935,.T.);
#3937=ADVANCED_FACE('F2367',(#3936),#3925,.T.);
#3938=CARTESIAN_POINT('',(12.,0.,0.));
#3939=DIRECTION('',(-1.,0.,0.));
#3940=DIRECTION('',(0.,0.,1.));
#3941=AXIS2_PLACEMENT_3D('',#3938,#3939,#3940);
#3942=CYLINDRICAL_SURFACE('',#3941,16.749);
#3943=ORIENTED_EDGE('',*,*,#1625,.F.);
#3944=ORIENTED_EDGE('',*,*,#3932,.F.);
#3945=ORIENTED_EDGE('',*,*,#740,.T.);
#3946=ORIENTED_EDGE('',*,*,#3915,.T.);
#3947=EDGE_LOOP('',(#3943,#3944,#3945,#3946));
#3948=FACE_BOUND('',#3947,.T.);
#3949=ADVANCED_FACE('F2363',(#3948),#3942,.T.);
#3950=CARTESIAN_POINT('',(12.,-16.4296678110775,-4.02059889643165));
#3951=DIRECTION('',(-1.,0.,0.));
#3952=DIRECTION('',(0.,0.,1.));
#3953=AXIS2_PLACEMENT_3D('',#3950,#3951,#3952);
#3954=CYLINDRICAL_SURFACE('',#3953,7.2);
#3955=ORIENTED_EDGE('',*,*,#2568,.T.);
#3956=ORIENTED_EDGE('',*,*,#1603,.F.);
#3957=DIRECTION('',(-1.,0.,0.));
#3958=VECTOR('',#3957,1.);
#3959=CARTESIAN_POINT('',(12.,-13.1180030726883,-10.4137887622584));
#3960=LINE('',#3959,#3958);
#3961=EDGE_CURVE('E1449',#761,#1593,#3960,.T.);
#3962=ORIENTED_EDGE('',*,*,#3961,.F.);
#3963=ORIENTED_EDGE('',*,*,#762,.T.);
#3964=EDGE_LOOP('',(#3955,#3956,#3962,#3963));
#3965=FACE_BOUND('',#3964,.T.);
#3966=ADVANCED_FACE('F2359',(#3965),#3954,.T.);
#3967=CARTESIAN_POINT('',(12.,-6.81249884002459,-15.4818945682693));
#3968=DIRECTION('',(-1.,0.,0.));
#3969=DIRECTION('',(0.,0.,1.));
#3970=AXIS2_PLACEMENT_3D('',#3967,#3968,#3969);
#3971=CYLINDRICAL_SURFACE('',#3970,7.2);
#3972=ORIENTED_EDGE('',*,*,#2558,.T.);
#3973=ORIENTED_EDGE('',*,*,#780,.T.);
#3974=DIRECTION('',(-1.,0.,0.));
#3975=VECTOR('',#3974,1.);
#3976=CARTESIAN_POINT('',(12.,-12.5334972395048,-11.1103756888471));
#3977=LINE('',#3976,#3975);
#3978=EDGE_CURVE('E1447',#770,#1584,#3977,.T.);
#3979=ORIENTED_EDGE('',*,*,#3978,.T.);
#3980=ORIENTED_EDGE('',*,*,#1585,.T.);
#3981=EDGE_LOOP('',(#3972,#3973,#3979,#3980));
#3982=FACE_BOUND('',#3981,.T.);
#3983=ADVANCED_FACE('F2355',(#3982),#3971,.T.);
#3984=CARTESIAN_POINT('',(12.,0.,0.));
#3985=DIRECTION('',(-1.,0.,0.));
#3986=DIRECTION('',(0.,0.,1.));
#3987=AXIS2_PLACEMENT_3D('',#3984,#3985,#3986);
#3988=CYLINDRICAL_SURFACE('',#3987,16.749);
#3989=ORIENTED_EDGE('',*,*,#1594,.F.);
#3990=ORIENTED_EDGE('',*,*,#3978,.F.);
#3991=ORIENTED_EDGE('',*,*,#771,.T.);
#3992=ORIENTED_EDGE('',*,*,#3961,.T.);
#3993=EDGE_LOOP('',(#3989,#3990,#3991,#3992));
#3994=FACE_BOUND('',#3993,.T.);
#3995=ADVANCED_FACE('F2351',(#3994),#3988,.T.);
#3996=CARTESIAN_POINT('',(12.,-15.4818945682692,-6.81249884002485));
#3997=DIRECTION('',(-1.,0.,0.));
#3998=DIRECTION('',(0.,0.,1.));
#3999=AXIS2_PLACEMENT_3D('',#3996,#3997,#3998);
#4000=CYLINDRICAL_SURFACE('',#3999,7.2);
#4001=ORIENTED_EDGE('',*,*,#2551,.T.);
#4002=ORIENTED_EDGE('',*,*,#1572,.F.);
#4003=DIRECTION('',(-1.,0.,0.));
#4004=VECTOR('',#4003,1.);
#4005=CARTESIAN_POINT('',(12.,-11.1103756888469,-12.533497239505));
#4006=LINE('',#4005,#4004);
#4007=EDGE_CURVE('E1471',#792,#1562,#4006,.T.);
#4008=ORIENTED_EDGE('',*,*,#4007,.F.);
#4009=ORIENTED_EDGE('',*,*,#793,.T.);
#4010=EDGE_LOOP('',(#4001,#4002,#4008,#4009));
#4011=FACE_BOUND('',#4010,.T.);
#4012=ADVANCED_FACE('F2347',(#4011),#4000,.T.);
#4013=CARTESIAN_POINT('',(12.,-4.02059889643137,-16.4296678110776));
#4014=DIRECTION('',(-1.,0.,0.));
#4015=DIRECTION('',(0.,0.,1.));
#4016=AXIS2_PLACEMENT_3D('',#4013,#4014,#4015);
#4017=CYLINDRICAL_SURFACE('',#4016,7.2);
#4018=ORIENTED_EDGE('',*,*,#2541,.T.);
#4019=ORIENTED_EDGE('',*,*,#811,.T.);
#4020=DIRECTION('',(-1.,0.,0.));
#4021=VECTOR('',#4020,1.);
#4022=CARTESIAN_POINT('',(12.,-10.4137887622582,-13.1180030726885));
#4023=LINE('',#4022,#4021);
#4024=EDGE_CURVE('E1469',#801,#1553,#4023,.T.);
#4025=ORIENTED_EDGE('',*,*,#4024,.T.);
#4026=ORIENTED_EDGE('',*,*,#1554,.T.);
#4027=EDGE_LOOP('',(#4018,#4019,#4025,#4026));
#4028=FACE_BOUND('',#4027,.T.);
#4029=ADVANCED_FACE('F2343',(#4028),#4017,.T.);
#4030=CARTESIAN_POINT('',(12.,0.,0.));
#4031=DIRECTION('',(-1.,0.,0.));
#4032=DIRECTION('',(0.,0.,1.));
#4033=AXIS2_PLACEMENT_3D('',#4030,#4031,#4032);
#4034=CYLINDRICAL_SURFACE('',#4033,16.749);
#4035=ORIENTED_EDGE('',*,*,#1563,.F.);
#4036=ORIENTED_EDGE('',*,*,#4024,.F.);
#4037=ORIENTED_EDGE('',*,*,#802,.T.);
#4038=ORIENTED_EDGE('',*,*,#4007,.T.);
#4039=EDGE_LOOP('',(#4035,#4036,#4037,#4038));
#4040=FACE_BOUND('',#4039,.T.);
#4041=ADVANCED_FACE('F2339',(#4040),#4034,.T.);
#4042=CARTESIAN_POINT('',(12.,-14.0637117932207,-9.39740445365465));
#4043=DIRECTION('',(-1.,0.,0.));
#4044=DIRECTION('',(0.,0.,1.));
#4045=AXIS2_PLACEMENT_3D('',#4042,#4043,#4044);
#4046=CYLINDRICAL_SURFACE('',#4045,7.2);
#4047=ORIENTED_EDGE('',*,*,#2534,.T.);
#4048=ORIENTED_EDGE('',*,*,#1541,.F.);
#4049=DIRECTION('',(-1.,0.,0.));
#4050=VECTOR('',#4049,1.);
#4051=CARTESIAN_POINT('',(12.,-8.76516516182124,-14.2723817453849));
#4052=LINE('',#4051,#4050);
#4053=EDGE_CURVE('E1493',#823,#1531,#4052,.T.);
#4054=ORIENTED_EDGE('',*,*,#4053,.F.);
#4055=ORIENTED_EDGE('',*,*,#824,.T.);
#4056=EDGE_LOOP('',(#4047,#4048,#4054,#4055));
#4057=FACE_BOUND('',#4056,.T.);
#4058=ADVANCED_FACE('F2335',(#4057),#4046,.T.);
#4059=CARTESIAN_POINT('',(12.,-1.10653508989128,-16.8782339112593));
#4060=DIRECTION('',(-1.,0.,0.));
#4061=DIRECTION('',(0.,0.,1.));
#4062=AXIS2_PLACEMENT_3D('',#4059,#4060,#4061);
#4063=CYLINDRICAL_SURFACE('',#4062,7.2);
#4064=ORIENTED_EDGE('',*,*,#2524,.T.);
#4065=ORIENTED_EDGE('',*,*,#842,.T.);
#4066=DIRECTION('',(-1.,0.,0.));
#4067=VECTOR('',#4066,1.);
#4068=CARTESIAN_POINT('',(12.,-7.97766258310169,-14.7270465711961));
#4069=LINE('',#4068,#4067);
#4070=EDGE_CURVE('E1491',#832,#1522,#4069,.T.);
#4071=ORIENTED_EDGE('',*,*,#4070,.T.);
#4072=ORIENTED_EDGE('',*,*,#1523,.T.);
#4073=EDGE_LOOP('',(#4064,#4065,#4071,#4072));
#4074=FACE_BOUND('',#4073,.T.);
#4075=ADVANCED_FACE('F2331',(#4074),#4063,.T.);
#4076=CARTESIAN_POINT('',(12.,0.,0.));
#4077=DIRECTION('',(-1.,0.,0.));
#4078=DIRECTION('',(0.,0.,1.));
#4079=AXIS2_PLACEMENT_3D('',#4076,#4077,#4078);
#4080=CYLINDRICAL_SURFACE('',#4079,16.749);
#4081=ORIENTED_EDGE('',*,*,#1532,.F.);
#4082=ORIENTED_EDGE('',*,*,#4070,.F.);
#4083=ORIENTED_EDGE('',*,*,#833,.T.);
#4084=ORIENTED_EDGE('',*,*,#4053,.T.);
#4085=EDGE_LOOP('',(#4081,#4082,#4083,#4084));
#4086=FACE_BOUND('',#4085,.T.);
#4087=ADVANCED_FACE('F2327',(#4086),#4080,.T.);
#4088=CARTESIAN_POINT('',(12.,-12.2182102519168,-11.6967746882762));
#4089=DIRECTION('',(-1.,0.,0.));
#4090=DIRECTION('',(0.,0.,1.));
#4091=AXIS2_PLACEMENT_3D('',#4088,#4089,#4090);
#4092=CYLINDRICAL_SURFACE('',#4091,7.2);
#4093=ORIENTED_EDGE('',*,*,#2517,.T.);
#4094=ORIENTED_EDGE('',*,*,#1510,.F.);
#4095=DIRECTION('',(-1.,0.,0.));
#4096=VECTOR('',#4095,1.);
#4097=CARTESIAN_POINT('',(12.,-6.15362952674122,-15.5776071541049));
#4098=LINE('',#4097,#4096);
#4099=EDGE_CURVE('E1515',#854,#1500,#4098,.T.);
#4100=ORIENTED_EDGE('',*,*,#4099,.F.);
#4101=ORIENTED_EDGE('',*,*,#855,.T.);
#4102=EDGE_LOOP('',(#4093,#4094,#4100,#4101));
#4103=FACE_BOUND('',#4102,.T.);
#4104=ADVANCED_FACE('F2323',(#4103),#4092,.T.);
#4105=CARTESIAN_POINT('',(12.,1.84115022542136,-16.8139634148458));
#4106=DIRECTION('',(-1.,0.,0.));
#4107=DIRECTION('',(0.,0.,1.));
#4108=AXIS2_PLACEMENT_3D('',#4105,#4106,#4107);
#4109=CYLINDRICAL_SURFACE('',#4108,7.2);
#4110=ORIENTED_EDGE('',*,*,#2507,.T.);
#4111=ORIENTED_EDGE('',*,*,#873,.T.);
#4112=DIRECTION('',(-1.,0.,0.));
#4113=VECTOR('',#4112,1.);
#4114=CARTESIAN_POINT('',(12.,-5.29913916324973,-15.8886162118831));
#4115=LINE('',#4114,#4113);
#4116=EDGE_CURVE('E1513',#863,#1491,#4115,.T.);
#4117=ORIENTED_EDGE('',*,*,#4116,.T.);
#4118=ORIENTED_EDGE('',*,*,#1492,.T.);
#4119=EDGE_LOOP('',(#4110,#4111,#4117,#4118));
#4120=FACE_BOUND('',#4119,.T.);
#4121=ADVANCED_FACE('F2319',(#4120),#4109,.T.);
#4122=CARTESIAN_POINT('',(12.,0.,0.));
#4123=DIRECTION('',(-1.,0.,0.));
#4124=DIRECTION('',(0.,0.,1.));
#4125=AXIS2_PLACEMENT_3D('',#4122,#4123,#4124);
#4126=CYLINDRICAL_SURFACE('',#4125,16.749);
#4127=ORIENTED_EDGE('',*,*,#1501,.F.);
#4128=ORIENTED_EDGE('',*,*,#4116,.F.);
#4129=ORIENTED_EDGE('',*,*,#864,.T.);
#4130=ORIENTED_EDGE('',*,*,#4099,.T.);
#4131=EDGE_LOOP('',(#4127,#4128,#4129,#4130));
#4132=FACE_BOUND('',#4131,.T.);
#4133=ADVANCED_FACE('F2315',(#4132),#4126,.T.);
#4134=CARTESIAN_POINT('',(12.,-10.001464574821,-13.6407443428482));
#4135=DIRECTION('',(-1.,0.,0.));
#4136=DIRECTION('',(0.,0.,1.));
#4137=AXIS2_PLACEMENT_3D('',#4134,#4135,#4136);
#4138=CYLINDRICAL_SURFACE('',#4137,7.2);
#4139=ORIENTED_EDGE('',*,*,#2500,.T.);
#4140=ORIENTED_EDGE('',*,*,#1479,.F.);
#4141=DIRECTION('',(-1.,0.,0.));
#4142=VECTOR('',#4141,1.);
#4143=CARTESIAN_POINT('',(12.,-3.35511897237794,-16.4095148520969));
#4144=LINE('',#4143,#4142);
#4145=EDGE_CURVE('E1537',#885,#1469,#4144,.T.);
#4146=ORIENTED_EDGE('',*,*,#4145,.F.);
#4147=ORIENTED_EDGE('',*,*,#886,.T.);
#4148=EDGE_LOOP('',(#4139,#4140,#4146,#4147));
#4149=FACE_BOUND('',#4148,.T.);
#4150=ADVANCED_FACE('F2311',(#4149),#4138,.T.);
#4151=CARTESIAN_POINT('',(12.,4.73289312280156,-16.2388091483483));
#4152=DIRECTION('',(-1.,0.,0.));
#4153=DIRECTION('',(0.,0.,1.));
#4154=AXIS2_PLACEMENT_3D('',#4151,#4152,#4153);
#4155=CYLINDRICAL_SURFACE('',#4154,7.2);
#4156=ORIENTED_EDGE('',*,*,#2490,.T.);
#4157=ORIENTED_EDGE('',*,*,#904,.T.);
#4158=DIRECTION('',(-1.,0.,0.));
#4159=VECTOR('',#4158,1.);
#4160=CARTESIAN_POINT('',(12.,-2.4596040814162,-16.5674182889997));
#4161=LINE('',#4160,#4159);
#4162=EDGE_CURVE('E1535',#894,#1460,#4161,.T.);
#4163=ORIENTED_EDGE('',*,*,#4162,.T.);
#4164=ORIENTED_EDGE('',*,*,#1461,.T.);
#4165=EDGE_LOOP('',(#4156,#4157,#4163,#4164));
#4166=FACE_BOUND('',#4165,.T.);
#4167=ADVANCED_FACE('F2307',(#4166),#4155,.T.);
#4168=CARTESIAN_POINT('',(12.,0.,0.));
#4169=DIRECTION('',(-1.,0.,0.));
#4170=DIRECTION('',(0.,0.,1.));
#4171=AXIS2_PLACEMENT_3D('',#4168,#4169,#4170);
#4172=CYLINDRICAL_SURFACE('',#4171,16.749);
#4173=ORIENTED_EDGE('',*,*,#1470,.F.);
#4174=ORIENTED_EDGE('',*,*,#4162,.F.);
#4175=ORIENTED_EDGE('',*,*,#895,.T.);
#4176=ORIENTED_EDGE('',*,*,#4145,.T.);
#4177=EDGE_LOOP('',(#4173,#4174,#4175,#4176));
#4178=FACE_BOUND('',#4177,.T.);
#4179=ADVANCED_FACE('F2303',(#4178),#4172,.T.);
#4180=CARTESIAN_POINT('',(12.,-7.48082945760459,-15.1702468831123));
#4181=DIRECTION('',(-1.,0.,0.));
#4182=DIRECTION('',(0.,0.,1.));
#4183=AXIS2_PLACEMENT_3D('',#4180,#4181,#4182);
#4184=CYLINDRICAL_SURFACE('',#4183,7.2);
#4185=ORIENTED_EDGE('',*,*,#2483,.T.);
#4186=ORIENTED_EDGE('',*,*,#1448,.F.);
#4187=DIRECTION('',(-1.,0.,0.));
#4188=VECTOR('',#4187,1.);
#4189=CARTESIAN_POINT('',(12.,-0.454664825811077,-16.7428277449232));
#4190=LINE('',#4189,#4188);
#4191=EDGE_CURVE('E1559',#916,#1438,#4190,.T.);
#4192=ORIENTED_EDGE('',*,*,#4191,.F.);
#4193=ORIENTED_EDGE('',*,*,#917,.T.);
#4194=EDGE_LOOP('',(#4185,#4186,#4192,#4193));
#4195=FACE_BOUND('',#4194,.T.);
#4196=ADVANCED_FACE('F2299',(#4195),#4184,.T.);
#4197=CARTESIAN_POINT('',(12.,7.48082945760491,-15.1702468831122));
#4198=DIRECTION('',(-1.,0.,0.));
#4199=DIRECTION('',(0.,0.,1.));
#4200=AXIS2_PLACEMENT_3D('',#4197,#4198,#4199);
#4201=CYLINDRICAL_SURFACE('',#4200,7.2);
#4202=ORIENTED_EDGE('',*,*,#2473,.T.);
#4203=ORIENTED_EDGE('',*,*,#935,.T.);
#4204=DIRECTION('',(-1.,0.,0.));
#4205=VECTOR('',#4204,1.);
#4206=CARTESIAN_POINT('',(12.,0.454664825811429,-16.7428277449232));
#4207=LINE('',#4206,#4205);
#4208=EDGE_CURVE('E1557',#925,#1429,#4207,.T.);
#4209=ORIENTED_EDGE('',*,*,#4208,.T.);
#4210=ORIENTED_EDGE('',*,*,#1430,.T.);
#4211=EDGE_LOOP('',(#4202,#4203,#4209,#4210));
#4212=FACE_BOUND('',#4211,.T.);
#4213=ADVANCED_FACE('F2295',(#4212),#4201,.T.);
#4214=CARTESIAN_POINT('',(12.,0.,0.));
#4215=DIRECTION('',(-1.,0.,0.));
#4216=DIRECTION('',(0.,0.,1.));
#4217=AXIS2_PLACEMENT_3D('',#4214,#4215,#4216);
#4218=CYLINDRICAL_SURFACE('',#4217,16.749);
#4219=ORIENTED_EDGE('',*,*,#1439,.F.);
#4220=ORIENTED_EDGE('',*,*,#4208,.F.);
#4221=ORIENTED_EDGE('',*,*,#926,.T.);
#4222=ORIENTED_EDGE('',*,*,#4191,.T.);
#4223=EDGE_LOOP('',(#4219,#4220,#4221,#4222));
#4224=FACE_BOUND('',#4223,.T.);
#4225=ADVANCED_FACE('F2291',(#4224),#4218,.T.);
#4226=CARTESIAN_POINT('',(12.,-4.73289312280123,-16.2388091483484));
#4227=DIRECTION('',(-1.,0.,0.));
#4228=DIRECTION('',(0.,0.,1.));
#4229=AXIS2_PLACEMENT_3D('',#4226,#4227,#4228);
#4230=CYLINDRICAL_SURFACE('',#4229,7.2);
#4231=ORIENTED_EDGE('',*,*,#2466,.T.);
#4232=ORIENTED_EDGE('',*,*,#1417,.F.);
#4233=DIRECTION('',(-1.,0.,0.));
#4234=VECTOR('',#4233,1.);
#4235=CARTESIAN_POINT('',(12.,2.45960408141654,-16.5674182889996));
#4236=LINE('',#4235,#4234);
#4237=EDGE_CURVE('E1581',#947,#1407,#4236,.T.);
#4238=ORIENTED_EDGE('',*,*,#4237,.F.);
#4239=ORIENTED_EDGE('',*,*,#948,.T.);
#4240=EDGE_LOOP('',(#4231,#4232,#4238,#4239));
#4241=FACE_BOUND('',#4240,.T.);
#4242=ADVANCED_FACE('F2287',(#4241),#4230,.T.);
#4243=CARTESIAN_POINT('',(12.,10.0014645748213,-13.640744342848));
#4244=DIRECTION('',(-1.,0.,0.));
#4245=DIRECTION('',(0.,0.,1.));
#4246=AXIS2_PLACEMENT_3D('',#4243,#4244,#4245);
#4247=CYLINDRICAL_SURFACE('',#4246,7.2);
#4248=ORIENTED_EDGE('',*,*,#2456,.T.);
#4249=ORIENTED_EDGE('',*,*,#966,.T.);
#4250=DIRECTION('',(-1.,0.,0.));
#4251=VECTOR('',#4250,1.);
#4252=CARTESIAN_POINT('',(12.,3.35511897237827,-16.4095148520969));
#4253=LINE('',#4252,#4251);
#4254=EDGE_CURVE('E1579',#956,#1398,#4253,.T.);
#4255=ORIENTED_EDGE('',*,*,#4254,.T.);
#4256=ORIENTED_EDGE('',*,*,#1399,.T.);
#4257=EDGE_LOOP('',(#4248,#4249,#4255,#4256));
#4258=FACE_BOUND('',#4257,.T.);
#4259=ADVANCED_FACE('F2283',(#4258),#4247,.T.);
#4260=CARTESIAN_POINT('',(12.,0.,0.));
#4261=DIRECTION('',(-1.,0.,0.));
#4262=DIRECTION('',(0.,0.,1.));
#4263=AXIS2_PLACEMENT_3D('',#4260,#4261,#4262);
#4264=CYLINDRICAL_SURFACE('',#4263,16.749);
#4265=ORIENTED_EDGE('',*,*,#1408,.F.);
#4266=ORIENTED_EDGE('',*,*,#4254,.F.);
#4267=ORIENTED_EDGE('',*,*,#957,.T.);
#4268=ORIENTED_EDGE('',*,*,#4237,.T.);
#4269=EDGE_LOOP('',(#4265,#4266,#4267,#4268));
#4270=FACE_BOUND('',#4269,.T.);
#4271=ADVANCED_FACE('F2279',(#4270),#4264,.T.);
#4272=CARTESIAN_POINT('',(12.,-1.84115022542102,-16.8139634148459));
#4273=DIRECTION('',(-1.,0.,0.));
#4274=DIRECTION('',(0.,0.,1.));
#4275=AXIS2_PLACEMENT_3D('',#4272,#4273,#4274);
#4276=CYLINDRICAL_SURFACE('',#4275,7.2);
#4277=ORIENTED_EDGE('',*,*,#2449,.T.);
#4278=ORIENTED_EDGE('',*,*,#1386,.F.);
#4279=DIRECTION('',(-1.,0.,0.));
#4280=VECTOR('',#4279,1.);
#4281=CARTESIAN_POINT('',(12.,5.29913916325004,-15.8886162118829));
#4282=LINE('',#4281,#4280);
#4283=EDGE_CURVE('E1603',#978,#1376,#4282,.T.);
#4284=ORIENTED_EDGE('',*,*,#4283,.F.);
#4285=ORIENTED_EDGE('',*,*,#979,.T.);
#4286=EDGE_LOOP('',(#4277,#4278,#4284,#4285));
#4287=FACE_BOUND('',#4286,.T.);
#4288=ADVANCED_FACE('F2275',(#4287),#4276,.T.);
#4289=CARTESIAN_POINT('',(12.,12.218210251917,-11.696774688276));
#4290=DIRECTION('',(-1.,0.,0.));
#4291=DIRECTION('',(0.,0.,1.));
#4292=AXIS2_PLACEMENT_3D('',#4289,#4290,#4291);
#4293=CYLINDRICAL_SURFACE('',#4292,7.2);
#4294=ORIENTED_EDGE('',*,*,#2439,.T.);
#4295=ORIENTED_EDGE('',*,*,#997,.T.);
#4296=DIRECTION('',(-1.,0.,0.));
#4297=VECTOR('',#4296,1.);
#4298=CARTESIAN_POINT('',(12.,6.15362952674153,-15.5776071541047));
#4299=LINE('',#4298,#4297);
#4300=EDGE_CURVE('E1601',#987,#1367,#4299,.T.);
#4301=ORIENTED_EDGE('',*,*,#4300,.T.);
#4302=ORIENTED_EDGE('',*,*,#1368,.T.);
#4303=EDGE_LOOP('',(#4294,#4295,#4301,#4302));
#4304=FACE_BOUND('',#4303,.T.);
#4305=ADVANCED_FACE('F2271',(#4304),#4293,.T.);
#4306=CARTESIAN_POINT('',(12.,0.,0.));
#4307=DIRECTION('',(-1.,0.,0.));
#4308=DIRECTION('',(0.,0.,1.));
#4309=AXIS2_PLACEMENT_3D('',#4306,#4307,#4308);
#4310=CYLINDRICAL_SURFACE('',#4309,16.749);
#4311=ORIENTED_EDGE('',*,*,#1377,.F.);
#4312=ORIENTED_EDGE('',*,*,#4300,.F.);
#4313=ORIENTED_EDGE('',*,*,#988,.T.);
#4314=ORIENTED_EDGE('',*,*,#4283,.T.);
#4315=EDGE_LOOP('',(#4311,#4312,#4313,#4314));
#4316=FACE_BOUND('',#4315,.T.);
#4317=ADVANCED_FACE('F2267',(#4316),#4310,.T.);
#4318=CARTESIAN_POINT('',(12.,1.10653508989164,-16.8782339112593));
#4319=DIRECTION('',(-1.,0.,0.));
#4320=DIRECTION('',(0.,0.,1.));
#4321=AXIS2_PLACEMENT_3D('',#4318,#4319,#4320);
#4322=CYLINDRICAL_SURFACE('',#4321,7.2);
#4323=ORIENTED_EDGE('',*,*,#2432,.T.);
#4324=ORIENTED_EDGE('',*,*,#1355,.F.);
#4325=DIRECTION('',(-1.,0.,0.));
#4326=VECTOR('',#4325,1.);
#4327=CARTESIAN_POINT('',(12.,7.977662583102,-14.7270465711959));
#4328=LINE('',#4327,#4326);
#4329=EDGE_CURVE('E1625',#1009,#1345,#4328,.T.);
#4330=ORIENTED_EDGE('',*,*,#4329,.F.);
#4331=ORIENTED_EDGE('',*,*,#1010,.T.);
#4332=EDGE_LOOP('',(#4323,#4324,#4330,#4331));
#4333=FACE_BOUND('',#4332,.T.);
#4334=ADVANCED_FACE('F2263',(#4333),#4322,.T.);
#4335=CARTESIAN_POINT('',(12.,14.0637117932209,-9.39740445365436));
#4336=DIRECTION('',(-1.,0.,0.));
#4337=DIRECTION('',(0.,0.,1.));
#4338=AXIS2_PLACEMENT_3D('',#4335,#4336,#4337);
#4339=CYLINDRICAL_SURFACE('',#4338,7.2);
#4340=ORIENTED_EDGE('',*,*,#2422,.T.);
#4341=ORIENTED_EDGE('',*,*,#1028,.T.);
#4342=DIRECTION('',(-1.,0.,0.));
#4343=VECTOR('',#4342,1.);
#4344=CARTESIAN_POINT('',(12.,8.76516516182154,-14.2723817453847));
#4345=LINE('',#4344,#4343);
#4346=EDGE_CURVE('E1623',#1018,#1336,#4345,.T.);
#4347=ORIENTED_EDGE('',*,*,#4346,.T.);
#4348=ORIENTED_EDGE('',*,*,#1337,.T.);
#4349=EDGE_LOOP('',(#4340,#4341,#4347,#4348));
#4350=FACE_BOUND('',#4349,.T.);
#4351=ADVANCED_FACE('F2259',(#4350),#4339,.T.);
#4352=CARTESIAN_POINT('',(12.,0.,0.));
#4353=DIRECTION('',(-1.,0.,0.));
#4354=DIRECTION('',(0.,0.,1.));
#4355=AXIS2_PLACEMENT_3D('',#4352,#4353,#4354);
#4356=CYLINDRICAL_SURFACE('',#4355,16.749);
#4357=ORIENTED_EDGE('',*,*,#1346,.F.);
#4358=ORIENTED_EDGE('',*,*,#4346,.F.);
#4359=ORIENTED_EDGE('',*,*,#1019,.T.);
#4360=ORIENTED_EDGE('',*,*,#4329,.T.);
#4361=EDGE_LOOP('',(#4357,#4358,#4359,#4360));
#4362=FACE_BOUND('',#4361,.T.);
#4363=ADVANCED_FACE('F2255',(#4362),#4356,.T.);
#4364=CARTESIAN_POINT('',(12.,4.0205988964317,-16.4296678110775));
#4365=DIRECTION('',(-1.,0.,0.));
#4366=DIRECTION('',(0.,0.,1.));
#4367=AXIS2_PLACEMENT_3D('',#4364,#4365,#4366);
#4368=CYLINDRICAL_SURFACE('',#4367,7.2);
#4369=ORIENTED_EDGE('',*,*,#2415,.T.);
#4370=ORIENTED_EDGE('',*,*,#1324,.F.);
#4371=DIRECTION('',(-1.,0.,0.));
#4372=VECTOR('',#4371,1.);
#4373=CARTESIAN_POINT('',(12.,10.4137887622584,-13.1180030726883));
#4374=LINE('',#4373,#4372);
#4375=EDGE_CURVE('E1647',#1040,#1314,#4374,.T.);
#4376=ORIENTED_EDGE('',*,*,#4375,.F.);
#4377=ORIENTED_EDGE('',*,*,#1041,.T.);
#4378=EDGE_LOOP('',(#4369,#4370,#4376,#4377));
#4379=FACE_BOUND('',#4378,.T.);
#4380=ADVANCED_FACE('F2251',(#4379),#4368,.T.);
#4381=CARTESIAN_POINT('',(12.,15.4818945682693,-6.81249884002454));
#4382=DIRECTION('',(-1.,0.,0.));
#4383=DIRECTION('',(0.,0.,1.));
#4384=AXIS2_PLACEMENT_3D('',#4381,#4382,#4383);
#4385=CYLINDRICAL_SURFACE('',#4384,7.2);
#4386=ORIENTED_EDGE('',*,*,#2405,.T.);
#4387=ORIENTED_EDGE('',*,*,#1059,.T.);
#4388=DIRECTION('',(-1.,0.,0.));
#4389=VECTOR('',#4388,1.);
#4390=CARTESIAN_POINT('',(12.,11.1103756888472,-12.5334972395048));
#4391=LINE('',#4390,#4389);
#4392=EDGE_CURVE('E1645',#1049,#1305,#4391,.T.);
#4393=ORIENTED_EDGE('',*,*,#4392,.T.);
#4394=ORIENTED_EDGE('',*,*,#1306,.T.);
#4395=EDGE_LOOP('',(#4386,#4387,#4393,#4394));
#4396=FACE_BOUND('',#4395,.T.);
#4397=ADVANCED_FACE('F2247',(#4396),#4385,.T.);
#4398=CARTESIAN_POINT('',(12.,0.,0.));
#4399=DIRECTION('',(-1.,0.,0.));
#4400=DIRECTION('',(0.,0.,1.));
#4401=AXIS2_PLACEMENT_3D('',#4398,#4399,#4400);
#4402=CYLINDRICAL_SURFACE('',#4401,16.749);
#4403=ORIENTED_EDGE('',*,*,#1315,.F.);
#4404=ORIENTED_EDGE('',*,*,#4392,.F.);
#4405=ORIENTED_EDGE('',*,*,#1050,.T.);
#4406=ORIENTED_EDGE('',*,*,#4375,.T.);
#4407=EDGE_LOOP('',(#4403,#4404,#4405,#4406));
#4408=FACE_BOUND('',#4407,.T.);
#4409=ADVANCED_FACE('F2243',(#4408),#4402,.T.);
#4410=CARTESIAN_POINT('',(12.,6.81249884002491,-15.4818945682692));
#4411=DIRECTION('',(-1.,0.,0.));
#4412=DIRECTION('',(0.,0.,1.));
#4413=AXIS2_PLACEMENT_3D('',#4410,#4411,#4412);
#4414=CYLINDRICAL_SURFACE('',#4413,7.2);
#4415=ORIENTED_EDGE('',*,*,#2398,.T.);
#4416=ORIENTED_EDGE('',*,*,#1293,.F.);
#4417=DIRECTION('',(-1.,0.,0.));
#4418=VECTOR('',#4417,1.);
#4419=CARTESIAN_POINT('',(12.,12.533497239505,-11.1103756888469));
#4420=LINE('',#4419,#4418);
#4421=EDGE_CURVE('E1669',#1071,#1283,#4420,.T.);
#4422=ORIENTED_EDGE('',*,*,#4421,.F.);
#4423=ORIENTED_EDGE('',*,*,#1072,.T.);
#4424=EDGE_LOOP('',(#4415,#4416,#4422,#4423));
#4425=FACE_BOUND('',#4424,.T.);
#4426=ADVANCED_FACE('F2239',(#4425),#4414,.T.);
#4427=CARTESIAN_POINT('',(12.,16.4296678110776,-4.02059889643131));
#4428=DIRECTION('',(-1.,0.,0.));
#4429=DIRECTION('',(0.,0.,1.));
#4430=AXIS2_PLACEMENT_3D('',#4427,#4428,#4429);
#4431=CYLINDRICAL_SURFACE('',#4430,7.2);
#4432=ORIENTED_EDGE('',*,*,#2388,.T.);
#4433=ORIENTED_EDGE('',*,*,#1090,.T.);
#4434=DIRECTION('',(-1.,0.,0.));
#4435=VECTOR('',#4434,1.);
#4436=CARTESIAN_POINT('',(12.,13.1180030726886,-10.4137887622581));
#4437=LINE('',#4436,#4435);
#4438=EDGE_CURVE('E1667',#1080,#1274,#4437,.T.);
#4439=ORIENTED_EDGE('',*,*,#4438,.T.);
#4440=ORIENTED_EDGE('',*,*,#1275,.T.);
#4441=EDGE_LOOP('',(#4432,#4433,#4439,#4440));
#4442=FACE_BOUND('',#4441,.T.);
#4443=ADVANCED_FACE('F2235',(#4442),#4431,.T.);
#4444=CARTESIAN_POINT('',(12.,0.,0.));
#4445=DIRECTION('',(-1.,0.,0.));
#4446=DIRECTION('',(0.,0.,1.));
#4447=AXIS2_PLACEMENT_3D('',#4444,#4445,#4446);
#4448=CYLINDRICAL_SURFACE('',#4447,16.749);
#4449=ORIENTED_EDGE('',*,*,#1284,.F.);
#4450=ORIENTED_EDGE('',*,*,#4438,.F.);
#4451=ORIENTED_EDGE('',*,*,#1081,.T.);
#4452=ORIENTED_EDGE('',*,*,#4421,.T.);
#4453=EDGE_LOOP('',(#4449,#4450,#4451,#4452));
#4454=FACE_BOUND('',#4453,.T.);
#4455=ADVANCED_FACE('F2231',(#4454),#4448,.T.);
#4456=CARTESIAN_POINT('',(12.,9.3974044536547,-14.0637117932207));
#4457=DIRECTION('',(-1.,0.,0.));
#4458=DIRECTION('',(0.,0.,1.));
#4459=AXIS2_PLACEMENT_3D('',#4456,#4457,#4458);
#4460=CYLINDRICAL_SURFACE('',#4459,7.2);
#4461=ORIENTED_EDGE('',*,*,#2381,.T.);
#4462=ORIENTED_EDGE('',*,*,#1262,.F.);
#4463=DIRECTION('',(-1.,0.,0.));
#4464=VECTOR('',#4463,1.);
#4465=CARTESIAN_POINT('',(12.,14.2723817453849,-8.76516516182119));
#4466=LINE('',#4465,#4464);
#4467=EDGE_CURVE('E1691',#1102,#1252,#4466,.T.);
#4468=ORIENTED_EDGE('',*,*,#4467,.F.);
#4469=ORIENTED_EDGE('',*,*,#1103,.T.);
#4470=EDGE_LOOP('',(#4461,#4462,#4468,#4469));
#4471=FACE_BOUND('',#4470,.T.);
#4472=ADVANCED_FACE('F2228',(#4471),#4460,.T.);
#4473=CARTESIAN_POINT('',(12.,16.8782339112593,-1.10653508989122));
#4474=DIRECTION('',(-1.,0.,0.));
#4475=DIRECTION('',(0.,0.,1.));
#4476=AXIS2_PLACEMENT_3D('',#4473,#4474,#4475);
#4477=CYLINDRICAL_SURFACE('',#4476,7.2);
#4478=ORIENTED_EDGE('',*,*,#2371,.T.);
#4479=ORIENTED_EDGE('',*,*,#1121,.T.);
#4480=DIRECTION('',(-1.,0.,0.));
#4481=VECTOR('',#4480,1.);
#4482=CARTESIAN_POINT('',(12.,14.7270465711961,-7.97766258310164));
#4483=LINE('',#4482,#4481);
#4484=EDGE_CURVE('E1689',#1111,#1243,#4483,.T.);
#4485=ORIENTED_EDGE('',*,*,#4484,.T.);
#4486=ORIENTED_EDGE('',*,*,#1244,.T.);
#4487=EDGE_LOOP('',(#4478,#4479,#4485,#4486));
#4488=FACE_BOUND('',#4487,.T.);
#4489=ADVANCED_FACE('F2189',(#4488),#4477,.T.);
#4490=CARTESIAN_POINT('',(12.,0.,0.));
#4491=DIRECTION('',(-1.,0.,0.));
#4492=DIRECTION('',(0.,0.,1.));
#4493=AXIS2_PLACEMENT_3D('',#4490,#4491,#4492);
#4494=CYLINDRICAL_SURFACE('',#4493,16.749);
#4495=ORIENTED_EDGE('',*,*,#1253,.F.);
#4496=ORIENTED_EDGE('',*,*,#4484,.F.);
#4497=ORIENTED_EDGE('',*,*,#1112,.T.);
#4498=ORIENTED_EDGE('',*,*,#4467,.T.);
#4499=EDGE_LOOP('',(#4495,#4496,#4497,#4498));
#4500=FACE_BOUND('',#4499,.T.);
#4501=ADVANCED_FACE('F2222',(#4500),#4494,.T.);
#4502=CARTESIAN_POINT('',(12.,11.6967746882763,-12.2182102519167));
#4503=DIRECTION('',(-1.,0.,0.));
#4504=DIRECTION('',(0.,0.,1.));
#4505=AXIS2_PLACEMENT_3D('',#4502,#4503,#4504);
#4506=CYLINDRICAL_SURFACE('',#4505,7.2);
#4507=ORIENTED_EDGE('',*,*,#2364,.T.);
#4508=ORIENTED_EDGE('',*,*,#1231,.F.);
#4509=DIRECTION('',(-1.,0.,0.));
#4510=VECTOR('',#4509,1.);
#4511=CARTESIAN_POINT('',(12.,15.5776071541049,-6.15362952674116));
#4512=LINE('',#4511,#4510);
#4513=EDGE_CURVE('E1713',#1133,#1221,#4512,.T.);
#4514=ORIENTED_EDGE('',*,*,#4513,.F.);
#4515=ORIENTED_EDGE('',*,*,#1134,.T.);
#4516=EDGE_LOOP('',(#4507,#4508,#4514,#4515));
#4517=FACE_BOUND('',#4516,.T.);
#4518=ADVANCED_FACE('F2219',(#4517),#4506,.T.);
#4519=CARTESIAN_POINT('',(12.,16.8139634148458,1.84115022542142));
#4520=DIRECTION('',(-1.,0.,0.));
#4521=DIRECTION('',(0.,0.,1.));
#4522=AXIS2_PLACEMENT_3D('',#4519,#4520,#4521);
#4523=CYLINDRICAL_SURFACE('',#4522,7.2);
#4524=ORIENTED_EDGE('',*,*,#2337,.T.);
#4525=ORIENTED_EDGE('',*,*,#1152,.T.);
#4526=DIRECTION('',(-1.,0.,0.));
#4527=VECTOR('',#4526,1.);
#4528=CARTESIAN_POINT('',(12.,15.8886162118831,-5.29913916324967));
#4529=LINE('',#4528,#4527);
#4530=EDGE_CURVE('E1711',#1142,#1212,#4529,.T.);
#4531=ORIENTED_EDGE('',*,*,#4530,.T.);
#4532=ORIENTED_EDGE('',*,*,#1213,.T.);
#4533=EDGE_LOOP('',(#4524,#4525,#4531,#4532));
#4534=FACE_BOUND('',#4533,.T.);
#4535=ADVANCED_FACE('F1900',(#4534),#4523,.T.);
#4536=CARTESIAN_POINT('',(12.,0.,0.));
#4537=DIRECTION('',(-1.,0.,0.));
#4538=DIRECTION('',(0.,0.,1.));
#4539=AXIS2_PLACEMENT_3D('',#4536,#4537,#4538);
#4540=CYLINDRICAL_SURFACE('',#4539,16.749);
#4541=ORIENTED_EDGE('',*,*,#1222,.F.);
#4542=ORIENTED_EDGE('',*,*,#4530,.F.);
#4543=ORIENTED_EDGE('',*,*,#1143,.T.);
#4544=ORIENTED_EDGE('',*,*,#4513,.T.);
#4545=EDGE_LOOP('',(#4541,#4542,#4543,#4544));
#4546=FACE_BOUND('',#4545,.T.);
#4547=ADVANCED_FACE('F2206',(#4546),#4540,.T.);
#4548=CARTESIAN_POINT('',(12.,13.6407443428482,-10.001464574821));
#4549=DIRECTION('',(-1.,0.,0.));
#4550=DIRECTION('',(0.,0.,1.));
#4551=AXIS2_PLACEMENT_3D('',#4548,#4549,#4550);
#4552=CYLINDRICAL_SURFACE('',#4551,7.2);
#4553=ORIENTED_EDGE('',*,*,#2330,.T.);
#4554=ORIENTED_EDGE('',*,*,#1195,.F.);
#4555=DIRECTION('',(-1.,0.,0.));
#4556=VECTOR('',#4555,1.);
#4557=CARTESIAN_POINT('',(12.,16.4095148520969,-3.35511897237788));
#4558=LINE('',#4557,#4556);
#4559=EDGE_CURVE('E928',#41,#1192,#4558,.T.);
#4560=ORIENTED_EDGE('',*,*,#4559,.F.);
#4561=ORIENTED_EDGE('',*,*,#44,.T.);
#4562=EDGE_LOOP('',(#4553,#4554,#4560,#4561));
#4563=FACE_BOUND('',#4562,.T.);
#4564=ADVANCED_FACE('F2204',(#4563),#4552,.T.);
#4565=CARTESIAN_POINT('',(12.,16.2388091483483,4.73289312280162));
#4566=DIRECTION('',(-1.,0.,0.));
#4567=DIRECTION('',(0.,0.,1.));
#4568=AXIS2_PLACEMENT_3D('',#4565,#4566,#4567);
#4569=CYLINDRICAL_SURFACE('',#4568,7.2);
#4570=ORIENTED_EDGE('',*,*,#2347,.T.);
#4571=ORIENTED_EDGE('',*,*,#62,.T.);
#4572=DIRECTION('',(-1.,0.,0.));
#4573=VECTOR('',#4572,1.);
#4574=CARTESIAN_POINT('',(12.,16.5674182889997,-2.45960408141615));
#4575=LINE('',#4574,#4573);
#4576=EDGE_CURVE('E918',#52,#2297,#4575,.T.);
#4577=ORIENTED_EDGE('',*,*,#4576,.T.);
#4578=ORIENTED_EDGE('',*,*,#2298,.T.);
#4579=EDGE_LOOP('',(#4570,#4571,#4577,#4578));
#4580=FACE_BOUND('',#4579,.T.);
#4581=ADVANCED_FACE('F920',(#4580),#4569,.T.);
#4582=CARTESIAN_POINT('',(12.,0.,0.));
#4583=DIRECTION('',(-1.,0.,0.));
#4584=DIRECTION('',(0.,0.,1.));
#4585=AXIS2_PLACEMENT_3D('',#4582,#4583,#4584);
#4586=CYLINDRICAL_SURFACE('',#4585,16.749);
#4587=ORIENTED_EDGE('',*,*,#2305,.F.);
#4588=ORIENTED_EDGE('',*,*,#4576,.F.);
#4589=ORIENTED_EDGE('',*,*,#53,.T.);
#4590=ORIENTED_EDGE('',*,*,#4559,.T.);
#4591=EDGE_LOOP('',(#4587,#4588,#4589,#4590));
#4592=FACE_BOUND('',#4591,.T.);
#4593=ADVANCED_FACE('F932',(#4592),#4586,.T.);
#4594=CARTESIAN_POINT('',(50.0000508,0.,0.));
#4595=DIRECTION('',(-1.,0.,0.));
#4596=DIRECTION('',(0.,0.,1.));
#4597=AXIS2_PLACEMENT_3D('',#4594,#4595,#4596);
#4598=CYLINDRICAL_SURFACE('',#4597,6.);
#4599=ORIENTED_EDGE('',*,*,#2316,.T.);
#4600=EDGE_LOOP('',(#4599));
#4601=FACE_BOUND('',#4600,.T.);
#4602=ORIENTED_EDGE('',*,*,#1165,.T.);
#4603=EDGE_LOOP('',(#4602));
#4604=FACE_BOUND('',#4603,.T.);
#4605=ADVANCED_FACE('F1747',(#4601,#4604),#4598,.F.);
#4606=CARTESIAN_POINT('',(12.,12.2072193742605,0.));
#4607=DIRECTION('',(-1.,0.,0.));
#4608=DIRECTION('',(0.,0.,1.));
#4609=AXIS2_PLACEMENT_3D('',#4606,#4607,#4608);
#4610=CYLINDRICAL_SURFACE('',#4609,1.74146852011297);
#4611=ORIENTED_EDGE('',*,*,#31,.F.);
#4612=EDGE_LOOP('',(#4611));
#4613=FACE_BOUND('',#4612,.T.);
#4614=ORIENTED_EDGE('',*,*,#1182,.T.);
#4615=EDGE_LOOP('',(#4614));
#4616=FACE_BOUND('',#4615,.T.);
#4617=ADVANCED_FACE('F3154',(#4613,#4616),#4610,.F.);
#4618=CLOSED_SHELL('',(#1169,#2320,#2342,#2359,#2376,#2393,#2410,#2427,#2444,#2461,#2478,#2495,
#2512,#2529,#2546,#2563,#2580,#2597,#2614,#2631,#2648,#2665,#2682,#2699,#2716,#2733,#2750,#2767,
#2784,#2801,#2818,#2835,#2852,#2869,#2886,#2903,#2920,#2937,#2954,#2971,#2983,#3000,#3017,#3029,
#3046,#3063,#3075,#3092,#3109,#3121,#3138,#3155,#3167,#3184,#3201,#3213,#3230,#3247,#3259,#3276,
#3293,#3305,#3322,#3339,#3351,#3368,#3385,#3397,#3414,#3431,#3443,#3460,#3477,#3489,#3506,#3523,
#3535,#3552,#3569,#3581,#3598,#3615,#3627,#3644,#3661,#3673,#3690,#3707,#3719,#3736,#3753,#3765,
#3782,#3799,#3811,#3828,#3845,#3857,#3874,#3891,#3903,#3920,#3937,#3949,#3966,#3983,#3995,#4012,
#4029,#4041,#4058,#4075,#4087,#4104,#4121,#4133,#4150,#4167,#4179,#4196,#4213,#4225,#4242,#4259,
#4271,#4288,#4305,#4317,#4334,#4351,#4363,#4380,#4397,#4409,#4426,#4443,#4455,#4472,#4489,#4501,
#4518,#4535,#4547,#4564,#4581,#4593,#4605,#4617));
#4619=MANIFOLD_SOLID_BREP('B2',#4618);
#4620=ADVANCED_BREP_SHAPE_REPRESENTATION('',(#18,#4619),#14);
#4621=SHAPE_DEFINITION_REPRESENTATION(#9,#4620);
ENDSEC;
END-ISO-10303-21;
